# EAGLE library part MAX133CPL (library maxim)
3 3/4-digit DMM CIRCUIT

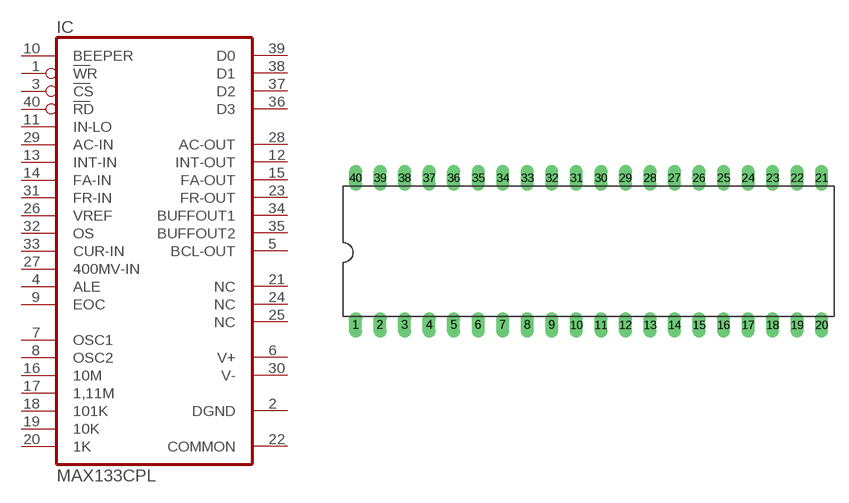
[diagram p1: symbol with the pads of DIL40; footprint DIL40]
Designator prefix IC

## MAX133CPL (MPN: MAX133CPL+; OC_FARNELL: unknown; OC_NEWARK: 99K2893)  [DIL40]
1  WR  in
2  DGND  pwr
3  CS  in
4  ALE  in
5  BCL-OUT  out
6  V+  pwr
7  OSC1  pas
8  OSC2  pas
9  EOC  in
10  BEEPER  in
11  IN-LO  in
12  INT-OUT  out
13  INT-IN  in
14  FA-IN  in
15  FA-OUT  out
16  10M  pas
17  1,11M  pas
18  101K  pas
19  10K  pas
20  1K  pas
21  NC  nc
22  COMMON  pwr
23  FR-OUT  out
24  NC  nc
25  NC  nc
26  VREF  in
27  400MV-IN  in
28  AC-OUT  out
29  AC-IN  in
30  V-  pwr
31  FR-IN  in
32  OS  in
33  CUR-IN  in
34  BUFFOUT1  out
35  BUFFOUT2  out
36  D3  out
37  D2  out
38  D1  out
39  D0  out
40  RD  in

## Footprint DIL40 (pad centres in mm)
Dual In Line Package
drill 0.813 long: 1 -24.13,-7.62; 2 -21.59,-7.62; 3 -19.05,-7.62; 4 -16.51,-7.62; 5 -13.97,-7.62; 6 -11.43,-7.62; 7 -8.89,-7.62; 8 -6.35,-7.62; 9 -3.81,-7.62; 10 -1.27,-7.62; 11 1.27,-7.62; 12 3.81,-7.62; 13 6.35,-7.62; 14 8.89,-7.62; 15 11.43,-7.62; 16 13.97,-7.62; 17 16.51,-7.62; 18 19.05,-7.62; 19 21.59,-7.62; 20 24.13,-7.62; 21 24.13,7.62; 22 21.59,7.62; 23 19.05,7.62; 24 16.51,7.62; 25 13.97,7.62; 26 11.43,7.62; 27 8.89,7.62; 28 6.35,7.62; 29 3.81,7.62; 30 1.27,7.62; 31 -1.27,7.62; 32 -3.81,7.62; 33 -6.35,7.62; 34 -8.89,7.62; 35 -11.43,7.62; 36 -13.97,7.62; 37 -16.51,7.62; 38 -19.05,7.62; 39 -21.59,7.62; 40 -24.13,7.62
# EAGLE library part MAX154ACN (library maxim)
ANALOG/DIGITAL CONVERTER

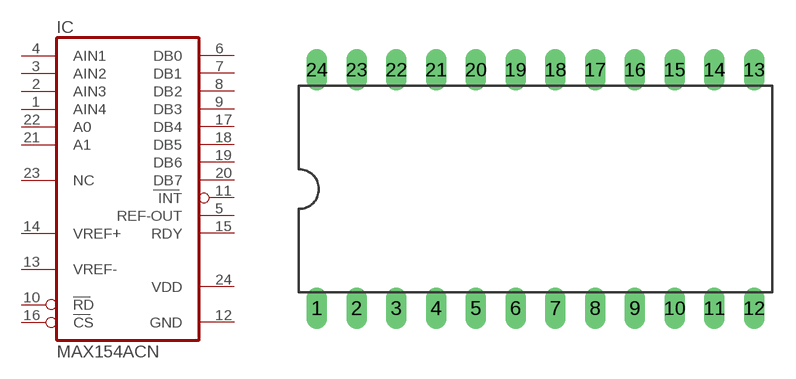
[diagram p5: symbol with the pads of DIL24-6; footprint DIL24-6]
Designator prefix IC

## MAX154ACN (MPN: MAX154ACNG+; OC_FARNELL: unknown; OC_NEWARK: 67K4138)  [DIL24-6]
1  AIN4  in
2  AIN3  in
3  AIN2  in
4  AIN1  in
5  REF-OUT  out
6  DB0  hiz
7  DB1  hiz
8  DB2  hiz
9  DB3  hiz
10  RD  in
11  INT  out
12  GND  pwr
13  VREF-  pas
14  VREF+  pas
15  RDY  out
16  CS  in
17  DB4  hiz
18  DB5  hiz
19  DB6  hiz
20  DB7  hiz
21  A1  in
22  A0  in
23  NC  nc
24  VDD  pwr

## Footprint DIL24-6 (pad centres in mm)
Dual In Line Package 0.6 inch
drill 0.813 long: 1 -13.97,-7.62; 2 -11.43,-7.62; 3 -8.89,-7.62; 4 -6.35,-7.62; 5 -3.81,-7.62; 6 -1.27,-7.62; 7 1.27,-7.62; 8 3.81,-7.62; 9 6.35,-7.62; 10 8.89,-7.62; 11 11.43,-7.62; 12 13.97,-7.62; 13 13.97,7.62; 14 11.43,7.62; 15 8.89,7.62; 16 6.35,7.62; 17 3.81,7.62; 18 1.27,7.62; 19 -1.27,7.62; 20 -3.81,7.62; 21 -6.35,7.62; 22 -8.89,7.62; 23 -11.43,7.62; 24 -13.97,7.62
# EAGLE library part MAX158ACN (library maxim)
ANALOG/DIGITAL CONVERTER

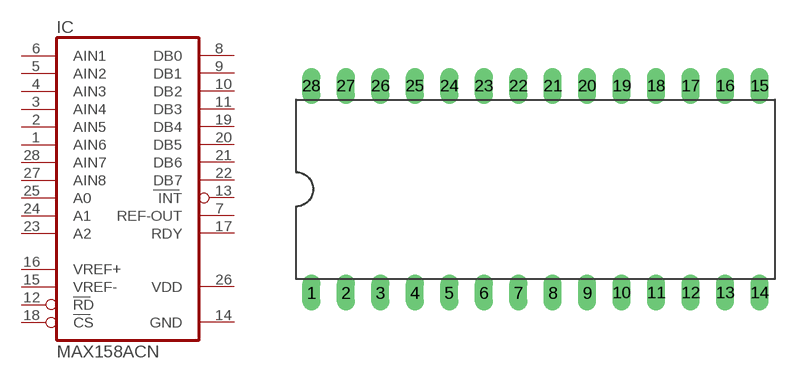
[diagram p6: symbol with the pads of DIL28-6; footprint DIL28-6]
Designator prefix IC

## MAX158ACN (OC_FARNELL: unknown; OC_NEWARK: unknown)  [DIL28-6]
1  AIN6  in
2  AIN5  in
3  AIN4  in
4  AIN3  in
5  AIN2  in
6  AIN1  in
7  REF-OUT  out
8  DB0  hiz
9  DB1  hiz
10  DB2  hiz
11  DB3  hiz
12  RD  in
13  INT  out
14  GND  pwr
15  VREF-  pas
16  VREF+  pas
17  RDY  out
18  CS  in
19  DB4  hiz
20  DB5  hiz
21  DB6  hiz
22  DB7  hiz
23  A2  in
24  A1  in
25  A0  in
26  VDD  pwr
27  AIN8  in
28  AIN7  in

## Footprint DIL28-6 (pad centres in mm)
Dual In Line Package 0.6 inch
drill 0.813 long: 1 -16.51,-7.62; 2 -13.97,-7.62; 3 -11.43,-7.62; 4 -8.89,-7.62; 5 -6.35,-7.62; 6 -3.81,-7.62; 7 -1.27,-7.62; 8 1.27,-7.62; 9 3.81,-7.62; 10 6.35,-7.62; 11 8.89,-7.62; 12 11.43,-7.62; 13 13.97,-7.62; 14 16.51,-7.62; 15 16.51,7.62; 16 13.97,7.62; 17 11.43,7.62; 18 8.89,7.62; 19 6.35,7.62; 20 3.81,7.62; 21 1.27,7.62; 22 -1.27,7.62; 23 -3.81,7.62; 24 -6.35,7.62; 25 -8.89,7.62; 26 -11.43,7.62; 27 -13.97,7.62; 28 -16.51,7.62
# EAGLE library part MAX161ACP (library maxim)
ANALOG/DIGITAL CONVERTER

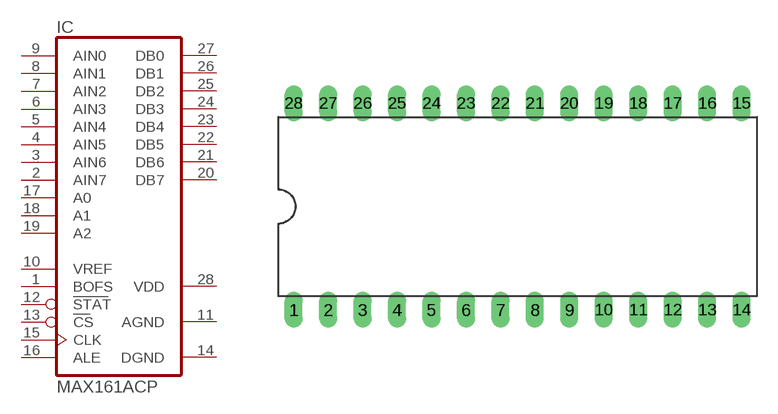
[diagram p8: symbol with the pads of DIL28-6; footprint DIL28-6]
Designator prefix IC

## MAX161ACP (MPN: MAX161ACPI+; OC_FARNELL: unknown; OC_NEWARK: 99K3007)  [DIL28-6]
1  BOFS  in
2  AIN7  in
3  AIN6  in
4  AIN5  in
5  AIN4  in
6  AIN3  in
7  AIN2  in
8  AIN1  in
9  AIN0  in
10  VREF  pas
11  AGND  pwr
12  STAT  in
13  CS  in
14  DGND  pwr
15  CLK  in
16  ALE  in
17  A0  in
18  A1  in
19  A2  in
20  DB7  hiz
21  DB6  hiz
22  DB5  hiz
23  DB4  hiz
24  DB3  hiz
25  DB2  hiz
26  DB1  hiz
27  DB0  hiz
28  VDD  pwr

## Footprint DIL28-6 (pad centres in mm)
Dual In Line Package 0.6 inch
drill 0.813 long: 1 -16.51,-7.62; 2 -13.97,-7.62; 3 -11.43,-7.62; 4 -8.89,-7.62; 5 -6.35,-7.62; 6 -3.81,-7.62; 7 -1.27,-7.62; 8 1.27,-7.62; 9 3.81,-7.62; 10 6.35,-7.62; 11 8.89,-7.62; 12 11.43,-7.62; 13 13.97,-7.62; 14 16.51,-7.62; 15 16.51,7.62; 16 13.97,7.62; 17 11.43,7.62; 18 8.89,7.62; 19 6.35,7.62; 20 3.81,7.62; 21 1.27,7.62; 22 -1.27,7.62; 23 -3.81,7.62; 24 -6.35,7.62; 25 -8.89,7.62; 26 -11.43,7.62; 27 -13.97,7.62; 28 -16.51,7.62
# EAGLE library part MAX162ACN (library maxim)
ANALOG/DIGITAL CONVERTER

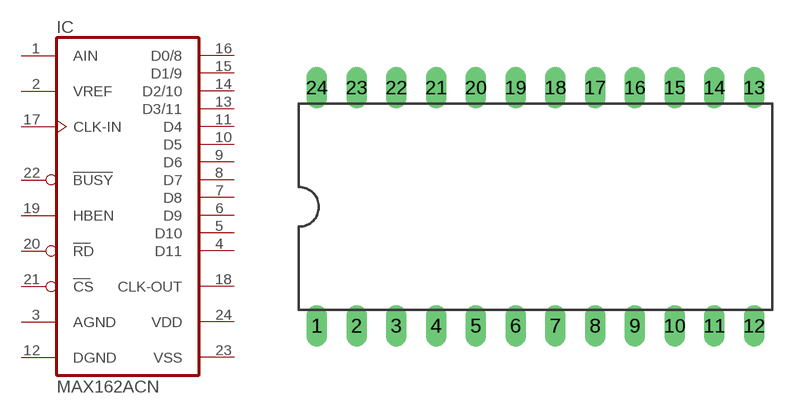
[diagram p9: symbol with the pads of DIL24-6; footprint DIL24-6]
Designator prefix IC

## MAX162ACN (MPN: MAX162ACNG+; OC_FARNELL: unknown; OC_NEWARK: 89K3211)  [DIL24-6]
1  AIN  in
2  VREF  in
3  AGND  pas
4  D11  hiz
5  D10  hiz
6  D9  hiz
7  D8  hiz
8  D7  hiz
9  D6  hiz
10  D5  hiz
11  D4  hiz
12  DGND  pas
13  D3/11  hiz
14  D2/10  hiz
15  D1/9  hiz
16  D0/8  hiz
17  CLK-IN  in
18  CLK-OUT  out
19  HBEN  in
20  RD  in
21  CS  in
22  BUSY  in
23  VSS  pwr
24  VDD  pwr

## Footprint DIL24-6 (pad centres in mm)
Dual In Line Package 0.6 inch
drill 0.813 long: 1 -13.97,-7.62; 2 -11.43,-7.62; 3 -8.89,-7.62; 4 -6.35,-7.62; 5 -3.81,-7.62; 6 -1.27,-7.62; 7 1.27,-7.62; 8 3.81,-7.62; 9 6.35,-7.62; 10 8.89,-7.62; 11 11.43,-7.62; 12 13.97,-7.62; 13 13.97,7.62; 14 11.43,7.62; 15 8.89,7.62; 16 6.35,7.62; 17 3.81,7.62; 18 1.27,7.62; 19 -1.27,7.62; 20 -3.81,7.62; 21 -6.35,7.62; 22 -8.89,7.62; 23 -11.43,7.62; 24 -13.97,7.62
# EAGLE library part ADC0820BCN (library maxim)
ANALOG/DIGITAL CONVERTER

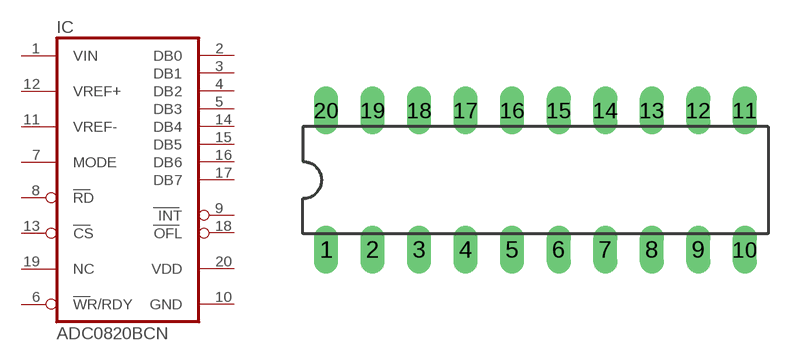
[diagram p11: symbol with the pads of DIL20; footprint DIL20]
Designator prefix IC

## ADC0820BCN (MF: NATIONAL SEMICONDUCTOR; MPN: ADC0820CCN/NOPB.; OC_FARNELL: 1189415; OC_NEWARK: unknown)  [DIL20]
1  VIN  in
2  DB0  hiz
3  DB1  hiz
4  DB2  hiz
5  DB3  hiz
6  WR/RDY
7  MODE  in
8  RD  in
9  INT  out
10  GND  pwr
11  VREF-  pas
12  VREF+  pas
13  CS  in
14  DB4  hiz
15  DB5  hiz
16  DB6  hiz
17  DB7  hiz
18  OFL  out
19  NC  nc
20  VDD  pwr

## Footprint DIL20 (pad centres in mm)
Dual In Line Package
drill 0.813 long: 1 -11.43,-3.81; 2 -8.89,-3.81; 3 -6.35,-3.81; 4 -3.81,-3.81; 5 -1.27,-3.81; 6 1.27,-3.81; 7 3.81,-3.81; 8 6.35,-3.81; 9 8.89,-3.81; 10 11.43,-3.81; 11 11.43,3.81; 12 8.89,3.81; 13 6.35,3.81; 14 3.81,3.81; 15 1.27,3.81; 16 -1.27,3.81; 17 -3.81,3.81; 18 -6.35,3.81; 19 -8.89,3.81; 20 -11.43,3.81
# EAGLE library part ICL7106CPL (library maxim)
LCD DRIVER

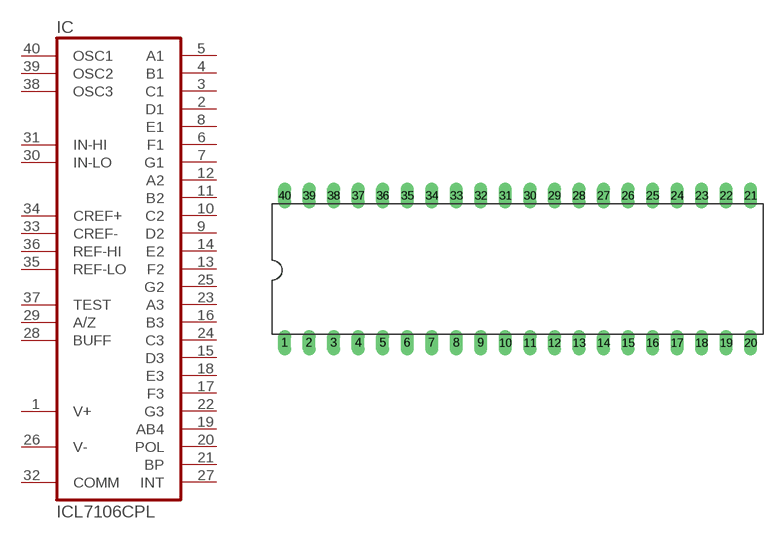
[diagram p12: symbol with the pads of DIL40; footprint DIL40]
Designator prefix IC

## ICL7106CPL (MF: INTERSIL; MPN: ICL7106CPL; OC_FARNELL: 9663550; OC_NEWARK: 06F7355)  [DIL40]
1  V+  pwr
2  D1  hiz
3  C1  hiz
4  B1  hiz
5  A1  hiz
6  F1  hiz
7  G1  hiz
8  E1  hiz
9  D2  hiz
10  C2  hiz
11  B2  hiz
12  A2  hiz
13  F2  hiz
14  E2  hiz
15  D3  hiz
16  B3  hiz
17  F3  hiz
18  E3  hiz
19  AB4  hiz
20  POL  out
21  BP  out
22  G3  hiz
23  A3  hiz
24  C3  hiz
25  G2  hiz
26  V-  pwr
27  INT  out
28  BUFF  pas
29  A/Z  pas
30  IN-LO  in
31  IN-HI  in
32  COMM  pwr
33  CREF-  pas
34  CREF+  pas
35  REF-LO  in
36  REF-HI  in
37  TEST  pas
38  OSC3  pas
39  OSC2  pas
40  OSC1  pas

## Footprint DIL40 (pad centres in mm)
Dual In Line Package
drill 0.813 long: 1 -24.13,-7.62; 2 -21.59,-7.62; 3 -19.05,-7.62; 4 -16.51,-7.62; 5 -13.97,-7.62; 6 -11.43,-7.62; 7 -8.89,-7.62; 8 -6.35,-7.62; 9 -3.81,-7.62; 10 -1.27,-7.62; 11 1.27,-7.62; 12 3.81,-7.62; 13 6.35,-7.62; 14 8.89,-7.62; 15 11.43,-7.62; 16 13.97,-7.62; 17 16.51,-7.62; 18 19.05,-7.62; 19 21.59,-7.62; 20 24.13,-7.62; 21 24.13,7.62; 22 21.59,7.62; 23 19.05,7.62; 24 16.51,7.62; 25 13.97,7.62; 26 11.43,7.62; 27 8.89,7.62; 28 6.35,7.62; 29 3.81,7.62; 30 1.27,7.62; 31 -1.27,7.62; 32 -3.81,7.62; 33 -6.35,7.62; 34 -8.89,7.62; 35 -11.43,7.62; 36 -13.97,7.62; 37 -16.51,7.62; 38 -19.05,7.62; 39 -21.59,7.62; 40 -24.13,7.62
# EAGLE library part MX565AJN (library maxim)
DIGITAL/ANALOG CONVERTER

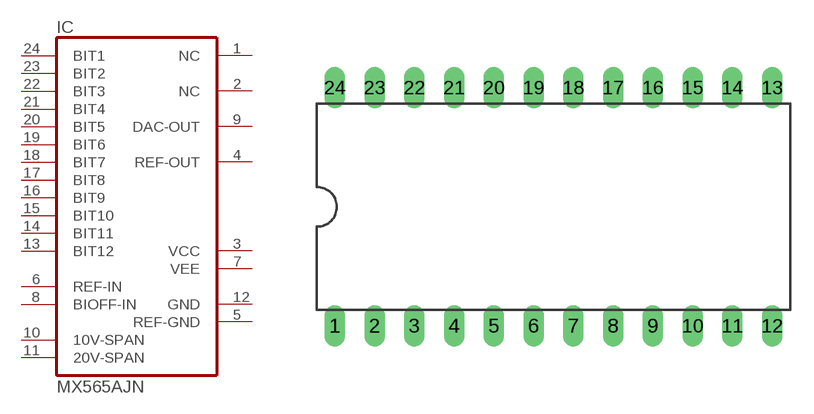
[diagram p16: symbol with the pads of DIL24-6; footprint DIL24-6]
Designator prefix IC

## MX565AJN (OC_FARNELL: unknown; OC_NEWARK: unknown)  [DIL24-6]
1  NC  nc
2  NC  nc
3  VCC  pwr
4  REF-OUT  out
5  REF-GND  pwr
6  REF-IN  in
7  VEE  pwr
8  BIOFF-IN  in
9  DAC-OUT  out
10  10V-SPAN  pas
11  20V-SPAN  pas
12  GND  pwr
13  BIT12  in
14  BIT11  in
15  BIT10  in
16  BIT9  in
17  BIT8  in
18  BIT7  in
19  BIT6  in
20  BIT5  in
21  BIT4  in
22  BIT3  in
23  BIT2  in
24  BIT1  in

## Footprint DIL24-6 (pad centres in mm)
Dual In Line Package 0.6 inch
drill 0.813 long: 1 -13.97,-7.62; 2 -11.43,-7.62; 3 -8.89,-7.62; 4 -6.35,-7.62; 5 -3.81,-7.62; 6 -1.27,-7.62; 7 1.27,-7.62; 8 3.81,-7.62; 9 6.35,-7.62; 10 8.89,-7.62; 11 11.43,-7.62; 12 13.97,-7.62; 13 13.97,7.62; 14 11.43,7.62; 15 8.89,7.62; 16 6.35,7.62; 17 3.81,7.62; 18 1.27,7.62; 19 -1.27,7.62; 20 -3.81,7.62; 21 -6.35,7.62; 22 -8.89,7.62; 23 -11.43,7.62; 24 -13.97,7.62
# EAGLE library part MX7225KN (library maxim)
DIGITAL/ANALOG CONVERTER

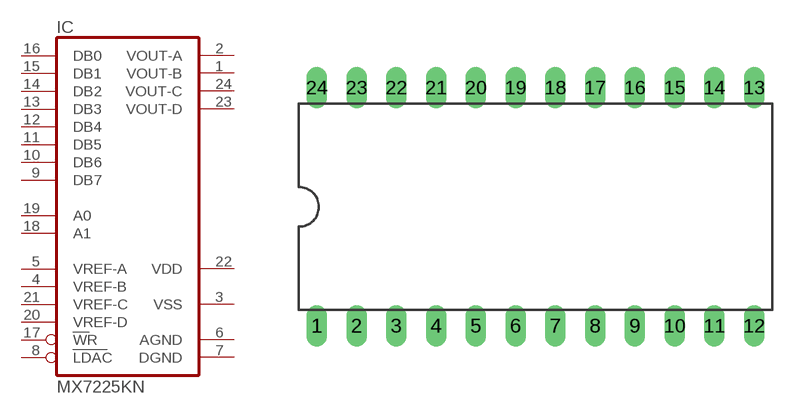
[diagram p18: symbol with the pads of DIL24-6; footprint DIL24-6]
Designator prefix IC

## MX7225KN (MPN: MX7225KN+; OC_FARNELL: unknown; OC_NEWARK: 67K7165)  [DIL24-6]
1  VOUT-B  out
2  VOUT-A  out
3  VSS  pwr
4  VREF-B  in
5  VREF-A  in
6  AGND  pwr
7  DGND  pwr
8  LDAC  in
9  DB7  in
10  DB6  in
11  DB5  in
12  DB4  in
13  DB3  in
14  DB2  in
15  DB1  in
16  DB0  in
17  WR  in
18  A1  in
19  A0  in
20  VREF-D  in
21  VREF-C  in
22  VDD  pwr
23  VOUT-D  out
24  VOUT-C  out

## Footprint DIL24-6 (pad centres in mm)
Dual In Line Package 0.6 inch
drill 0.813 long: 1 -13.97,-7.62; 2 -11.43,-7.62; 3 -8.89,-7.62; 4 -6.35,-7.62; 5 -3.81,-7.62; 6 -1.27,-7.62; 7 1.27,-7.62; 8 3.81,-7.62; 9 6.35,-7.62; 10 8.89,-7.62; 11 11.43,-7.62; 12 13.97,-7.62; 13 13.97,7.62; 14 11.43,7.62; 15 8.89,7.62; 16 6.35,7.62; 17 3.81,7.62; 18 1.27,7.62; 19 -1.27,7.62; 20 -3.81,7.62; 21 -6.35,7.62; 22 -8.89,7.62; 23 -11.43,7.62; 24 -13.97,7.62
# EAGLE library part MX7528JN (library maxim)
DIGITAL/ANALOG CONVERTER

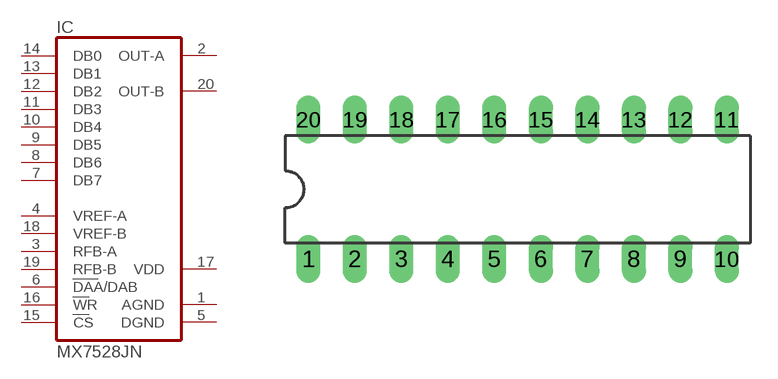
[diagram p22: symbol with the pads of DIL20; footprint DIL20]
Designator prefix IC

## MX7528JN (MPN: MX7528JN; OC_FARNELL: 1187979; OC_NEWARK: 34C4061)  [DIL20]
1  AGND  pwr
2  OUT-A  out
3  RFB-A  in
4  VREF-A  in
5  DGND  pwr
6  DAA/DAB  in
7  DB7  in
8  DB6  in
9  DB5  in
10  DB4  in
11  DB3  in
12  DB2  in
13  DB1  in
14  DB0  in
15  CS  in
16  WR  in
17  VDD  pwr
18  VREF-B  in
19  RFB-B  in
20  OUT-B  out

## Footprint DIL20 (pad centres in mm)
Dual In Line Package
drill 0.813 long: 1 -11.43,-3.81; 2 -8.89,-3.81; 3 -6.35,-3.81; 4 -3.81,-3.81; 5 -1.27,-3.81; 6 1.27,-3.81; 7 3.81,-3.81; 8 6.35,-3.81; 9 8.89,-3.81; 10 11.43,-3.81; 11 11.43,3.81; 12 8.89,3.81; 13 6.35,3.81; 14 3.81,3.81; 15 1.27,3.81; 16 -1.27,3.81; 17 -3.81,3.81; 18 -6.35,3.81; 19 -8.89,3.81; 20 -11.43,3.81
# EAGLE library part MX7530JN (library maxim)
DIGITAL/ANALOG CONVERTER

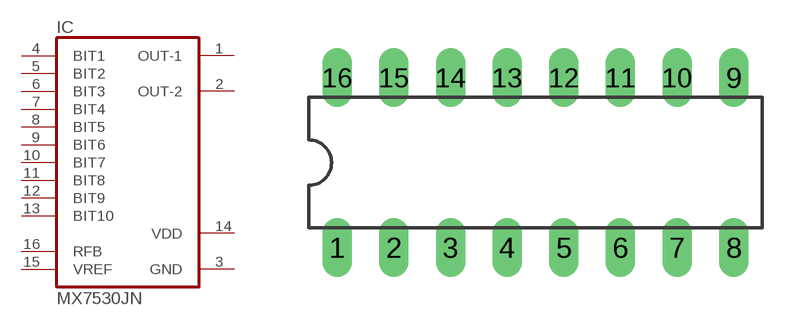
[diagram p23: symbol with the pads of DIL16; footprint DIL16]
Designator prefix IC

## MX7530JN (MPN: MX7530JN+; OC_FARNELL: unknown; OC_NEWARK: 99K3933)  [DIL16]
1  OUT-1  out
2  OUT-2  out
3  GND  pwr
4  BIT1  in
5  BIT2  in
6  BIT3  in
7  BIT4  in
8  BIT5  in
9  BIT6  in
10  BIT7  in
11  BIT8  in
12  BIT9  in
13  BIT10  in
14  VDD  pwr
15  VREF  in
16  RFB  in

## Footprint DIL16 (pad centres in mm)
Dual In Line Package
drill 0.813 long: 1 -8.89,-3.81; 2 -6.35,-3.81; 3 -3.81,-3.81; 4 -1.27,-3.81; 5 1.27,-3.81; 6 3.81,-3.81; 7 6.35,-3.81; 8 8.89,-3.81; 9 8.89,3.81; 10 6.35,3.81; 11 3.81,3.81; 12 1.27,3.81; 13 -1.27,3.81; 14 -3.81,3.81; 15 -6.35,3.81; 16 -8.89,3.81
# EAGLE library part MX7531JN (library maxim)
DIGITAL/ANALOG CONVERTER

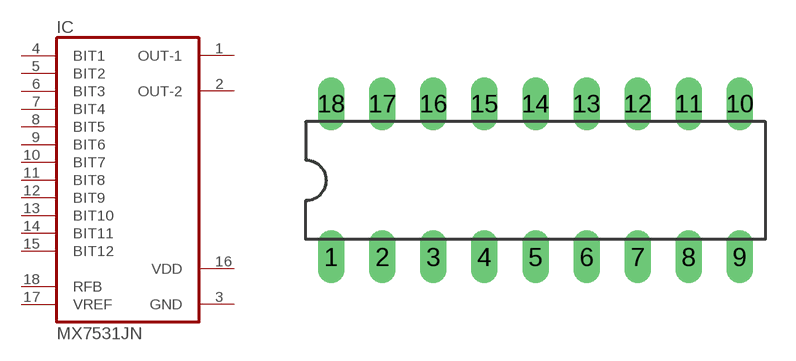
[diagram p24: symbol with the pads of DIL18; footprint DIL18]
Designator prefix IC

## MX7531JN (OC_FARNELL: unknown; OC_NEWARK: unknown)  [DIL18]
1  OUT-1  out
2  OUT-2  out
3  GND  pwr
4  BIT1  in
5  BIT2  in
6  BIT3  in
7  BIT4  in
8  BIT5  in
9  BIT6  in
10  BIT7  in
11  BIT8  in
12  BIT9  in
13  BIT10  in
14  BIT11  in
15  BIT12  in
16  VDD  pwr
17  VREF  in
18  RFB  in

## Footprint DIL18 (pad centres in mm)
Dual In Line Package
drill 0.813 long: 1 -10.16,-3.81; 2 -7.62,-3.81; 3 -5.08,-3.81; 4 -2.54,-3.81; 5 0,-3.81; 6 2.54,-3.81; 7 5.08,-3.81; 8 7.62,-3.81; 9 10.16,-3.81; 10 10.16,3.81; 11 7.62,3.81; 12 5.08,3.81; 13 2.54,3.81; 14 0,3.81; 15 -2.54,3.81; 16 -5.08,3.81; 17 -7.62,3.81; 18 -10.16,3.81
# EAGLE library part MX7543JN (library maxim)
DIGITAL/ANALOG CONVERTER

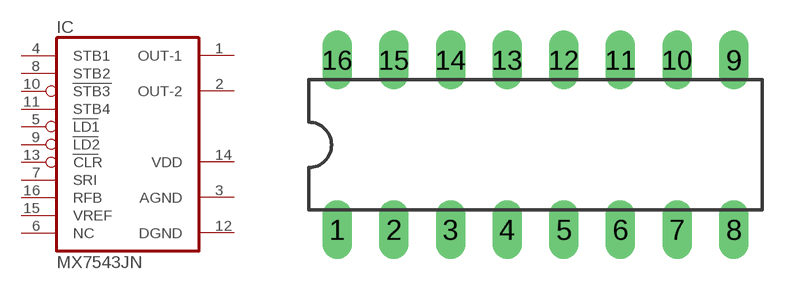
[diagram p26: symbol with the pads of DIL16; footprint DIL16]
Designator prefix IC

## MX7543JN (MF: MAXIM; MPN: MX7543JN; OC_FARNELL: 1187981; OC_NEWARK: 91C3519)  [DIL16]
1  OUT-1  out
2  OUT-2  out
3  AGND  pwr
4  STB1  in
5  LD1  in
6  NC  nc
7  SRI  in
8  STB2  in
9  LD2  in
10  STB3  in
11  STB4  in
12  DGND  pwr
13  CLR  in
14  VDD  pwr
15  VREF  in
16  RFB  in

## Footprint DIL16 (pad centres in mm)
Dual In Line Package
drill 0.813 long: 1 -8.89,-3.81; 2 -6.35,-3.81; 3 -3.81,-3.81; 4 -1.27,-3.81; 5 1.27,-3.81; 6 3.81,-3.81; 7 6.35,-3.81; 8 8.89,-3.81; 9 8.89,3.81; 10 6.35,3.81; 11 3.81,3.81; 12 1.27,3.81; 13 -1.27,3.81; 14 -3.81,3.81; 15 -6.35,3.81; 16 -8.89,3.81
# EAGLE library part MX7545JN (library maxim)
DIGITAL/ANALOG CONVERTER

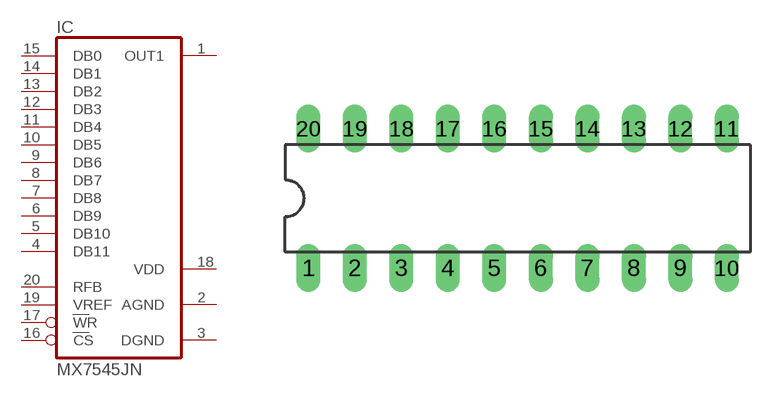
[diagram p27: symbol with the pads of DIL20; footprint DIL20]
Designator prefix IC

## MX7545JN (MPN: MX7545JN+; OC_FARNELL: unknown; OC_NEWARK: 61K1015)  [DIL20]
1  OUT1  out
2  AGND  pwr
3  DGND  pwr
4  DB11  in
5  DB10  in
6  DB9  in
7  DB8  in
8  DB7  in
9  DB6  in
10  DB5  in
11  DB4  in
12  DB3  in
13  DB2  in
14  DB1  in
15  DB0  in
16  CS  in
17  WR  in
18  VDD  pwr
19  VREF  in
20  RFB  in

## Footprint DIL20 (pad centres in mm)
Dual In Line Package
drill 0.813 long: 1 -11.43,-3.81; 2 -8.89,-3.81; 3 -6.35,-3.81; 4 -3.81,-3.81; 5 -1.27,-3.81; 6 1.27,-3.81; 7 3.81,-3.81; 8 6.35,-3.81; 9 8.89,-3.81; 10 11.43,-3.81; 11 11.43,3.81; 12 8.89,3.81; 13 6.35,3.81; 14 3.81,3.81; 15 1.27,3.81; 16 -1.27,3.81; 17 -3.81,3.81; 18 -6.35,3.81; 19 -8.89,3.81; 20 -11.43,3.81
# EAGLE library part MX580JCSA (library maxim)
VOLTAGE REFERENCE

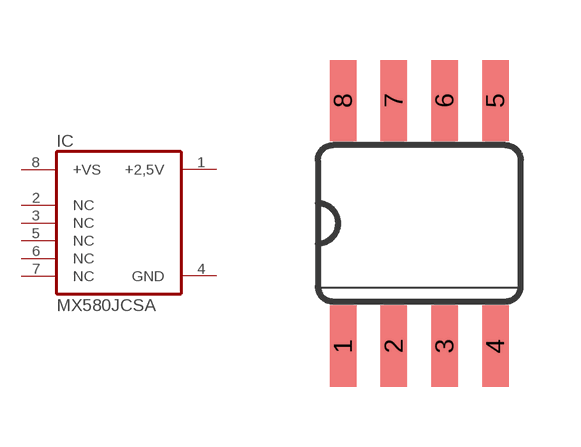
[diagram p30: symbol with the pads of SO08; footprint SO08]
Designator prefix IC

## MX580JCSA (OC_FARNELL: unknown; OC_NEWARK: unknown)  [SO08]
1  +2,5V  out
2  NC  nc
3  NC  nc
4  GND  pwr
5  NC  nc
6  NC  nc
7  NC  nc
8  +VS  in

## Footprint SO08 (pad centres in mm)
Small Outline Package SOIC 150 mil
smd 0.66 x 2.032: 1 -1.905,-3.073; 2 -0.635,-3.073; 3 0.635,-3.073; 4 1.905,-3.073; 5 1.905,3.073; 6 0.635,3.073; 7 -0.635,3.073; 8 -1.905,3.073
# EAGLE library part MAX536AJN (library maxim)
DIGITAL/ANALOG CONVERTER

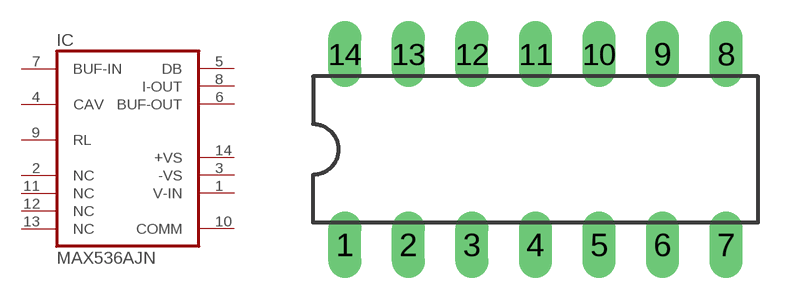
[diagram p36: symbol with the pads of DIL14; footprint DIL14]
Designator prefix IC

## MAX536AJN (OC_FARNELL: unknown; OC_NEWARK: unknown)  [DIL14]
1  V-IN  pwr
2  NC  nc
3  -VS  pwr
4  CAV  pas
5  DB  out
6  BUF-OUT  out
7  BUF-IN  in
8  I-OUT  out
9  RL  pas
10  COMM  pwr
11  NC  nc
12  NC  nc
13  NC  nc
14  +VS  pwr

## Footprint DIL14 (pad centres in mm)
Dual In Line Package
drill 0.813 long: 1 -7.62,-3.81; 2 -5.08,-3.81; 3 -2.54,-3.81; 4 0,-3.81; 5 2.54,-3.81; 6 5.08,-3.81; 7 7.62,-3.81; 8 7.62,3.81; 9 5.08,3.81; 10 2.54,3.81; 11 0,3.81; 12 -2.54,3.81; 13 -5.08,3.81; 14 -7.62,3.81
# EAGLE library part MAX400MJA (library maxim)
OP AMP

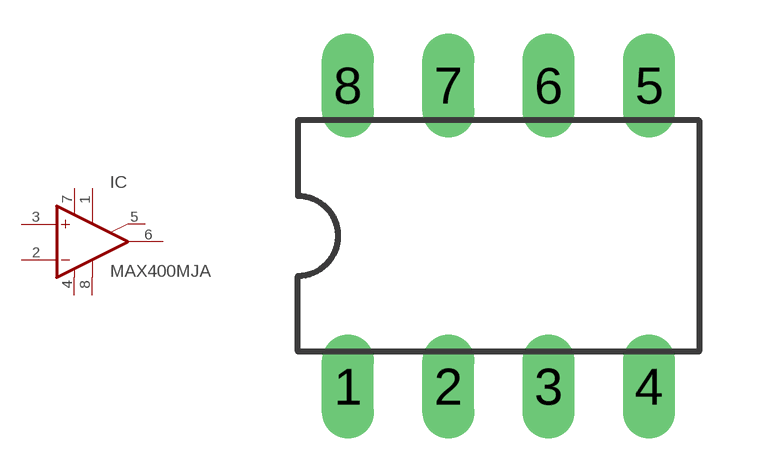
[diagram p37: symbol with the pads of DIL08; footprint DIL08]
Designator prefix IC

## MAX400MJA (OC_FARNELL: unknown; OC_NEWARK: unknown)  [DIL08]
1  VOS  pas
2  -IN  in
3  +IN  in
4  V-  pwr
5  NC  nc
6  OUT  out
7  V+  pwr
8  VOS  pas

## Footprint DIL08 (pad centres in mm)
Dual In Line Package
drill 0.813 long: 1 -3.81,-3.81; 2 -1.27,-3.81; 3 1.27,-3.81; 4 3.81,-3.81; 5 3.81,3.81; 6 1.27,3.81; 7 -1.27,3.81; 8 -3.81,3.81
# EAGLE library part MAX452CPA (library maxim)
VIDEO AMPLIFIER

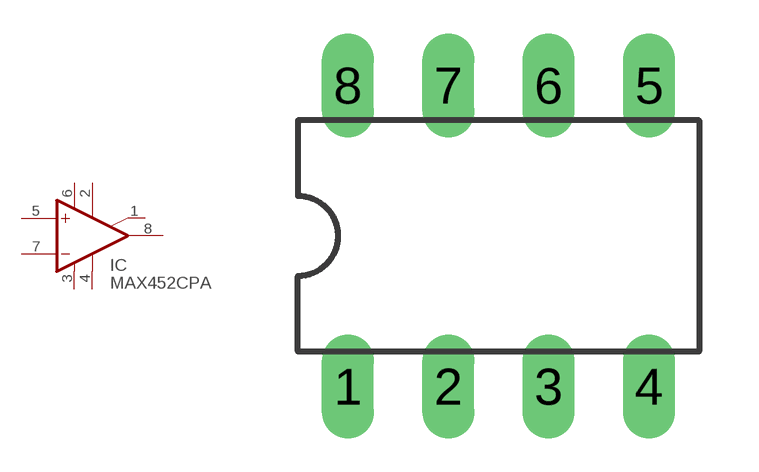
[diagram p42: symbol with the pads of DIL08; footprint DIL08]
Designator prefix IC

## MAX452CPA (MPN: MAX452CPA+; OC_FARNELL: 788910; OC_NEWARK: 99K3387)  [DIL08]
1  NC  nc
2  NC  nc
3  V-  pwr
4  NC  nc
5  +IN  in
6  V+  pwr
7  -IN  in
8  OUT  out

## Footprint DIL08 (pad centres in mm)
Dual In Line Package
drill 0.813 long: 1 -3.81,-3.81; 2 -1.27,-3.81; 3 1.27,-3.81; 4 3.81,-3.81; 5 3.81,3.81; 6 1.27,3.81; 7 -1.27,3.81; 8 -3.81,3.81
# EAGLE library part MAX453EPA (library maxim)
MULTIPLEXER

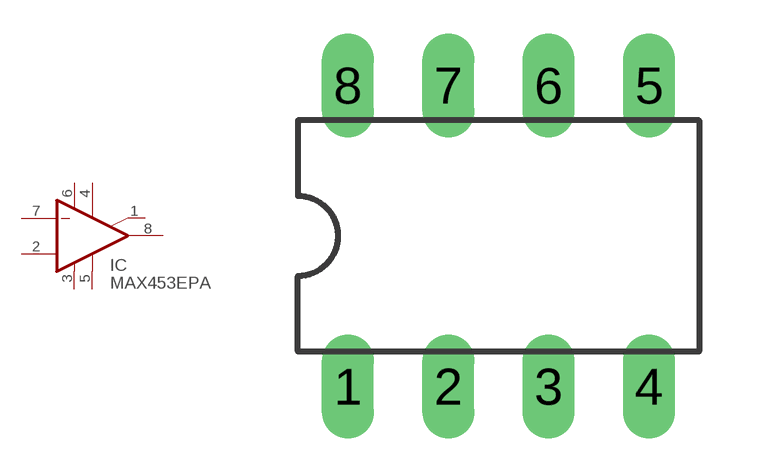
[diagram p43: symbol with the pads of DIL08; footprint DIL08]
Designator prefix IC

## MAX453EPA (OC_FARNELL: unknown; OC_NEWARK: unknown)  [DIL08]
1  A0  in
2  GND  pwr
3  V-  pwr
4  IN0  in
5  IN1  in
6  V+  pwr
7  -IN  in
8  OUT  out

## Footprint DIL08 (pad centres in mm)
Dual In Line Package
drill 0.813 long: 1 -3.81,-3.81; 2 -1.27,-3.81; 3 1.27,-3.81; 4 3.81,-3.81; 5 3.81,3.81; 6 1.27,3.81; 7 -1.27,3.81; 8 -3.81,3.81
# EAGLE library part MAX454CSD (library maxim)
MULTIPLEXER

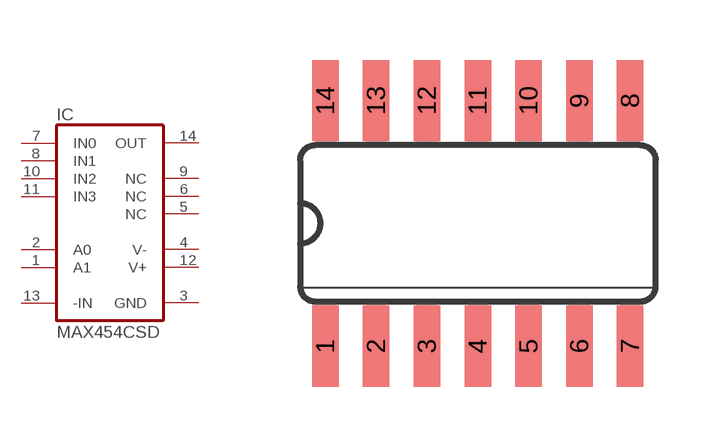
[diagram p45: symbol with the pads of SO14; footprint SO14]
Designator prefix IC

## MAX454CSD (MPN: MAX454CSD+; OC_FARNELL: unknown; OC_NEWARK: 67K5327)  [SO14]
1  A1  in
2  A0  in
3  GND  pwr
4  V-  pwr
5  NC  nc
6  NC  nc
7  IN0  in
8  IN1  in
9  NC  nc
10  IN2  in
11  IN3  in
12  V+  pwr
13  -IN  in
14  OUT  out

## Footprint SO14 (pad centres in mm)
Small Outline Package
smd 0.66 x 2.032: 1 -3.81,-3.073; 2 -2.54,-3.073; 3 -1.27,-3.073; 4 0,-3.073; 5 1.27,-3.073; 6 2.54,-3.073; 7 3.81,-3.073; 8 3.81,3.073; 9 2.54,3.073; 10 1.27,3.073; 11 0,3.073; 12 -1.27,3.073; 13 -2.54,3.073; 14 -3.81,3.073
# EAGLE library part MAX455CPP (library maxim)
MULTIPLEXER

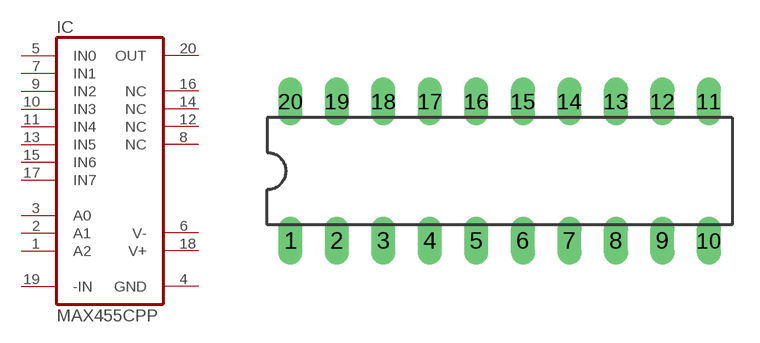
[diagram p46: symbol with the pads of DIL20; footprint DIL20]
Designator prefix IC

## MAX455CPP (MF: MAXIM; MPN: MAX455CPP+; OC_FARNELL: 1422330; OC_NEWARK: 68K4740)  [DIL20]
1  A2  in
2  A1  in
3  A0  in
4  GND  pwr
5  IN0  in
6  V-  pwr
7  IN1  in
8  NC  nc
9  IN2  in
10  IN3  in
11  IN4  in
12  NC  nc
13  IN5  in
14  NC  nc
15  IN6  in
16  NC  nc
17  IN7  in
18  V+  pwr
19  -IN  in
20  OUT  out

## Footprint DIL20 (pad centres in mm)
Dual In Line Package
drill 0.813 long: 1 -11.43,-3.81; 2 -8.89,-3.81; 3 -6.35,-3.81; 4 -3.81,-3.81; 5 -1.27,-3.81; 6 1.27,-3.81; 7 3.81,-3.81; 8 6.35,-3.81; 9 8.89,-3.81; 10 11.43,-3.81; 11 11.43,3.81; 12 8.89,3.81; 13 6.35,3.81; 14 3.81,3.81; 15 1.27,3.81; 16 -1.27,3.81; 17 -3.81,3.81; 18 -6.35,3.81; 19 -8.89,3.81; 20 -11.43,3.81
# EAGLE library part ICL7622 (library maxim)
Dual Operational Amplifiers Source: http://datasheets.maxim-ic.com/en/ds/ICL7612-ICL764X.pdf

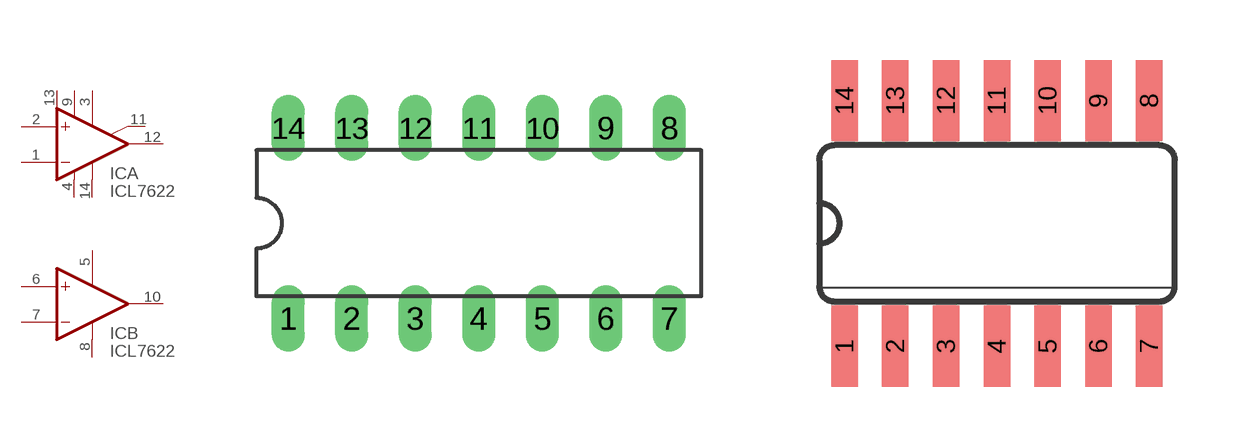
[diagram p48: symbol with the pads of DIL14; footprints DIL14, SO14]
Designator prefix IC; gates A=OPOFF+NC P=2V+V- B=OPOFF

## ICL7622PD (OC_FARNELL: unknown; OC_NEWARK: unknown)  [DIL14]
1  A:-IN  in
2  A:+IN  in
3  A:OFF1  pas
4  P:V-  pwr
5  B:OFF1  pas
6  B:+IN  in
7  B:-IN  in
8  B:OFF2  pas
9  P:V+  pwr
10  B:OUT  out
11  A:NC  pas
12  A:OUT  out
13  P:V+  pwr
14  A:OFF2  pas

## ICL7622SA (OC_FARNELL: unknown; OC_NEWARK: unknown)  [SO14]
Pads as for DIL14

## Footprint DIL14 (pad centres in mm)
Dual In Line Package
drill 0.813 long: 1 -7.62,-3.81; 2 -5.08,-3.81; 3 -2.54,-3.81; 4 0,-3.81; 5 2.54,-3.81; 6 5.08,-3.81; 7 7.62,-3.81; 8 7.62,3.81; 9 5.08,3.81; 10 2.54,3.81; 11 0,3.81; 12 -2.54,3.81; 13 -5.08,3.81; 14 -7.62,3.81

## Footprint SO14 (pad centres in mm)
Small Outline Package
smd 0.66 x 2.032: 1 -3.81,-3.073; 2 -2.54,-3.073; 3 -1.27,-3.073; 4 0,-3.073; 5 1.27,-3.073; 6 2.54,-3.073; 7 3.81,-3.073; 8 3.81,3.073; 9 2.54,3.073; 10 1.27,3.073; 11 0,3.073; 12 -1.27,3.073; 13 -2.54,3.073; 14 -3.81,3.073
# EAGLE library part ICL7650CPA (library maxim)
OP AMP

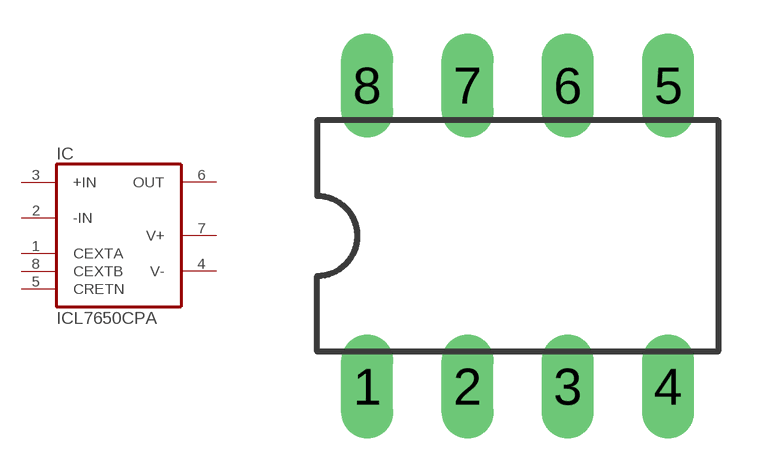
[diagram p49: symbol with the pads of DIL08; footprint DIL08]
Designator prefix IC

## ICL7650CPA (MPN: ICL7650CPA-1; OC_FARNELL: unknown; OC_NEWARK: 06F7424)  [DIL08]
1  CEXTA  pas
2  -IN  in
3  +IN  in
4  V-  pwr
5  CRETN  pas
6  OUT  out
7  V+  pwr
8  CEXTB  pas

## Footprint DIL08 (pad centres in mm)
Dual In Line Package
drill 0.813 long: 1 -3.81,-3.81; 2 -1.27,-3.81; 3 1.27,-3.81; 4 3.81,-3.81; 5 3.81,3.81; 6 1.27,3.81; 7 -1.27,3.81; 8 -3.81,3.81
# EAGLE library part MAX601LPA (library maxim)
AC-DC REGULATOR

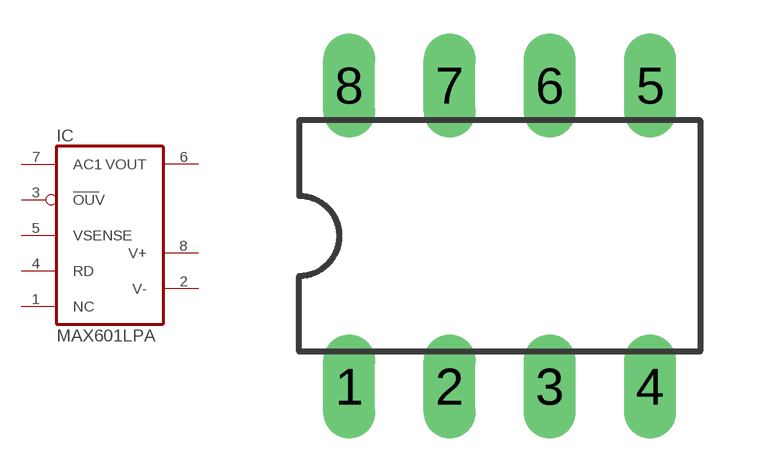
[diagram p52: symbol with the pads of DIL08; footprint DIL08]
Designator prefix IC

## MAX601LPA (OC_FARNELL: unknown; OC_NEWARK: unknown)  [DIL08]
1  NC  nc
2  V-  pwr
3  OUV  in
4  RD  pas
5  VSENSE  in
6  VOUT  out
7  AC1  in
8  V+  pwr

## Footprint DIL08 (pad centres in mm)
Dual In Line Package
drill 0.813 long: 1 -3.81,-3.81; 2 -1.27,-3.81; 3 1.27,-3.81; 4 3.81,-3.81; 5 3.81,3.81; 6 1.27,3.81; 7 -1.27,3.81; 8 -3.81,3.81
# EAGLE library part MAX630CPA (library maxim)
Step-up SWITCHING REGULATOR

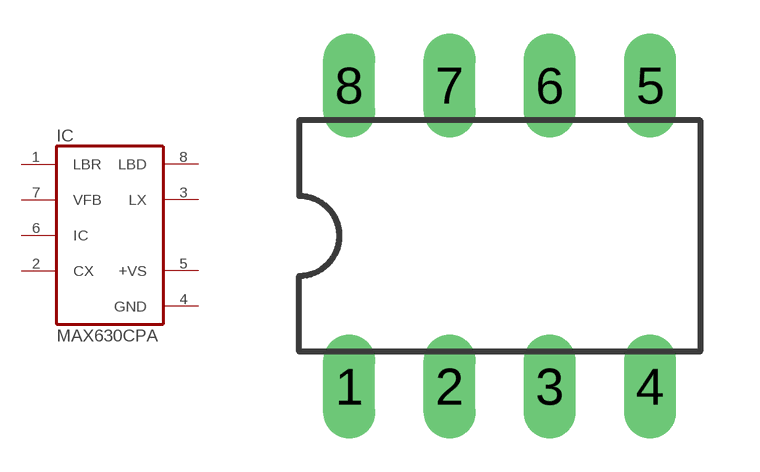
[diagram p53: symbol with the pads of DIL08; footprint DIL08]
Designator prefix IC

## MAX630CPA (MF: MAXIM; MPN: MAX630CPA; OC_FARNELL: unknown; OC_NEWARK: 34C3947)  [DIL08]
1  LBR  in
2  CX  pas
3  LX  out
4  GND  pwr
5  +VS  pwr
6  IC  in
7  VFB  in
8  LBD  out

## Footprint DIL08 (pad centres in mm)
Dual In Line Package
drill 0.813 long: 1 -3.81,-3.81; 2 -1.27,-3.81; 3 1.27,-3.81; 4 3.81,-3.81; 5 3.81,3.81; 6 1.27,3.81; 7 -1.27,3.81; 8 -3.81,3.81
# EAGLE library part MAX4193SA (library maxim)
Step-up SWITCHING REGULATOR

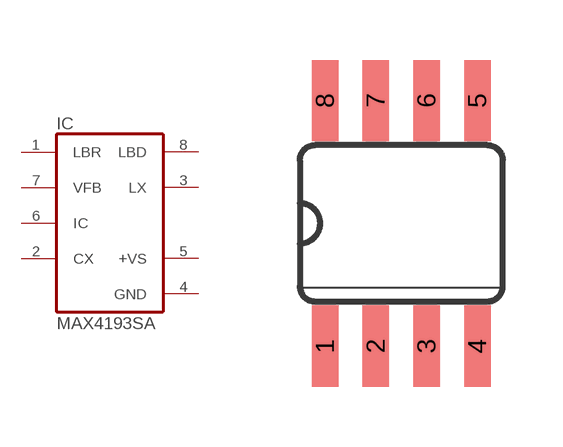
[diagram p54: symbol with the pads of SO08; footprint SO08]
Designator prefix IC

## MAX4193SA (OC_FARNELL: unknown; OC_NEWARK: unknown)  [SO08]
1  LBR  in
2  CX  pas
3  LX  out
4  GND  pwr
5  +VS  pwr
6  IC  in
7  VFB  in
8  LBD  out

## Footprint SO08 (pad centres in mm)
Small Outline Package SOIC 150 mil
smd 0.66 x 2.032: 1 -1.905,-3.073; 2 -0.635,-3.073; 3 0.635,-3.073; 4 1.905,-3.073; 5 1.905,3.073; 6 0.635,3.073; 7 -0.635,3.073; 8 -1.905,3.073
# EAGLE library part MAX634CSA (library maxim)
SWITCHING REGULATOR

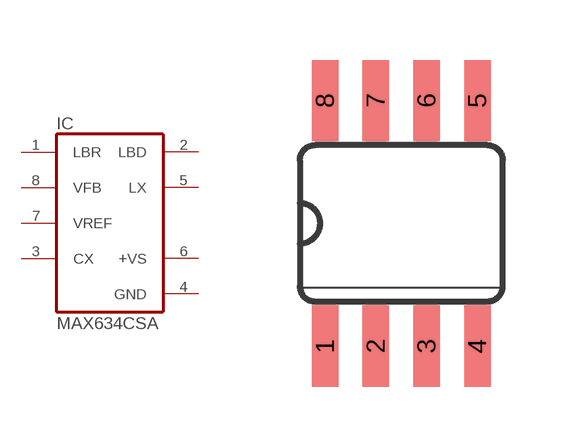
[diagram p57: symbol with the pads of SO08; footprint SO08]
Designator prefix IC

## MAX634CSA (MPN: MAX634CSA+; OC_FARNELL: 1673203; OC_NEWARK: 68K4925)  [SO08]
1  LBR  in
2  LBD  out
3  CX  pas
4  GND  pwr
5  LX  out
6  +VS  pwr
7  VREF  in
8  VFB  in

## Footprint SO08 (pad centres in mm)
Small Outline Package SOIC 150 mil
smd 0.66 x 2.032: 1 -1.905,-3.073; 2 -0.635,-3.073; 3 0.635,-3.073; 4 1.905,-3.073; 5 1.905,3.073; 6 0.635,3.073; 7 -0.635,3.073; 8 -1.905,3.073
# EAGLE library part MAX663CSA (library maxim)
Positive VOLTAGE REGULATOR

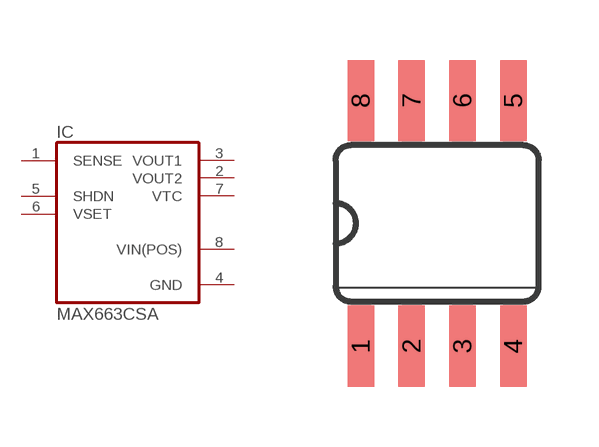
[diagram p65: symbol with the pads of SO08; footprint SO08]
Designator prefix IC

## MAX663CSA (MF: MAXIM; MPN: MAX663CSA; OC_FARNELL: 1188015; OC_NEWARK: 34C3969)  [SO08]
1  SENSE  in
2  VOUT2  out
3  VOUT1  out
4  GND  pwr
5  SHDN  in
6  VSET  in
7  VTC  out
8  VIN(POS)  pwr

## Footprint SO08 (pad centres in mm)
Small Outline Package SOIC 150 mil
smd 0.66 x 2.032: 1 -1.905,-3.073; 2 -0.635,-3.073; 3 0.635,-3.073; 4 1.905,-3.073; 5 1.905,3.073; 6 0.635,3.073; 7 -0.635,3.073; 8 -1.905,3.073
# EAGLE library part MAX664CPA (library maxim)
Negative VOLTAGE REGULATOR

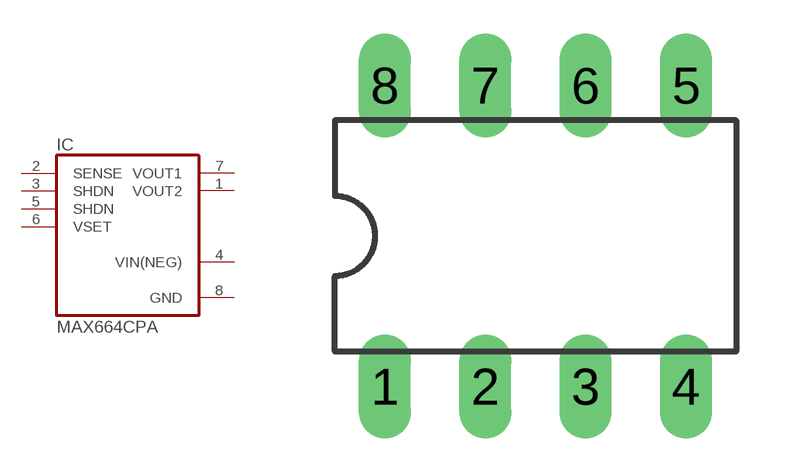
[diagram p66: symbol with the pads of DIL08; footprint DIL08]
Designator prefix IC

## MAX664CPA (MPN: MAX664CPA+; OC_FARNELL: 642617; OC_NEWARK: 76K7012)  [DIL08]
1  VOUT2  out
2  SENSE  in
3  SHDN  in
4  VIN(NEG)  pwr
5  SHDN  in
6  VSET  in
7  VOUT1  out
8  GND  pwr

## Footprint DIL08 (pad centres in mm)
Dual In Line Package
drill 0.813 long: 1 -3.81,-3.81; 2 -1.27,-3.81; 3 1.27,-3.81; 4 3.81,-3.81; 5 3.81,3.81; 6 1.27,3.81; 7 -1.27,3.81; 8 -3.81,3.81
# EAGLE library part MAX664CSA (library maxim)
Negative VOLTAGE REGULATOR

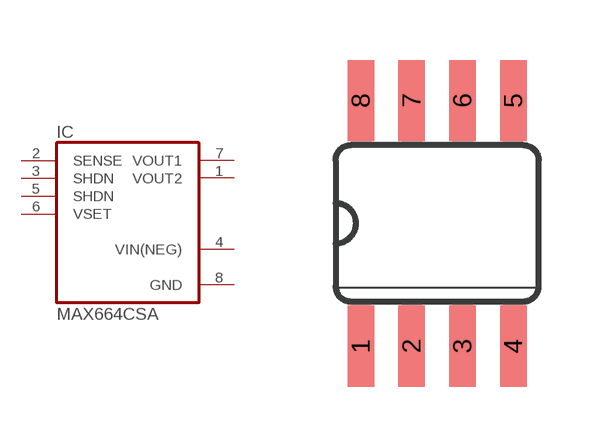
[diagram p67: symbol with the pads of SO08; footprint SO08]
Designator prefix IC

## MAX664CSA (MPN: MAX664CSA; OC_FARNELL: unknown; OC_NEWARK: 78C8112)  [SO08]
1  VOUT2  out
2  SENSE  in
3  SHDN  in
4  VIN(NEG)  pwr
5  SHDN  in
6  VSET  in
7  VOUT1  out
8  GND  pwr

## Footprint SO08 (pad centres in mm)
Small Outline Package SOIC 150 mil
smd 0.66 x 2.032: 1 -1.905,-3.073; 2 -0.635,-3.073; 3 0.635,-3.073; 4 1.905,-3.073; 5 1.905,3.073; 6 0.635,3.073; 7 -0.635,3.073; 8 -1.905,3.073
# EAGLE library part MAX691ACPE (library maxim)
WATCHDOG

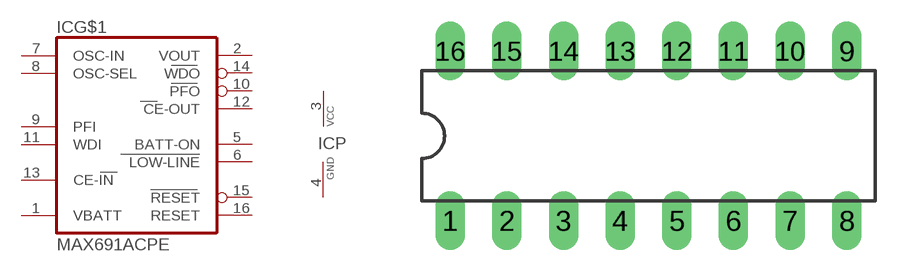
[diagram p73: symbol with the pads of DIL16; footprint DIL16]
Designator prefix IC; gates G$1=MAX691 P=VCC-GND

## MAX691ACPE (MF: MAXIM; MPN: MAX691ACPE+; OC_FARNELL: 1523912; OC_NEWARK: 68K4991)  [DIL16]
1  G$1:VBATT  in
2  G$1:VOUT  out
3  P:VCC  pwr
4  P:GND  pwr
5  G$1:BATT-ON  out
6  G$1:LOW-LINE  out
7  G$1:OSC-IN  pas
8  G$1:OSC-SEL  pas
9  G$1:PFI  in
10  G$1:PFO  out
11  G$1:WDI  in
12  G$1:CE-OUT  out
13  G$1:CE-IN  in
14  G$1:WDO  out
15  G$1:RESET  out
16  G$1:RESET  out

## Footprint DIL16 (pad centres in mm)
Dual In Line Package
drill 0.813 long: 1 -8.89,-3.81; 2 -6.35,-3.81; 3 -3.81,-3.81; 4 -1.27,-3.81; 5 1.27,-3.81; 6 3.81,-3.81; 7 6.35,-3.81; 8 8.89,-3.81; 9 8.89,3.81; 10 6.35,3.81; 11 3.81,3.81; 12 1.27,3.81; 13 -1.27,3.81; 14 -3.81,3.81; 15 -6.35,3.81; 16 -8.89,3.81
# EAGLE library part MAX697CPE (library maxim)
SUPERVISORY CIRCUIT

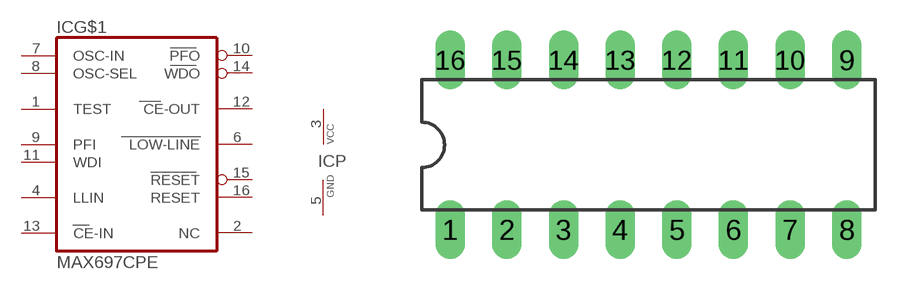
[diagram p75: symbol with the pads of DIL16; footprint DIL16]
Designator prefix IC; gates G$1=MAX697 P=VCC-GND

## MAX697CPE (MPN: MAX697CPE+; OC_FARNELL: unknown; OC_NEWARK: 89K6041)  [DIL16]
1  G$1:TEST  pas
2  G$1:NC  nc
3  P:VCC  pwr
4  G$1:LLIN  in
5  P:GND  pwr
6  G$1:LOW-LINE  out
7  G$1:OSC-IN  pas
8  G$1:OSC-SEL  pas
9  G$1:PFI  in
10  G$1:PFO  out
11  G$1:WDI  in
12  G$1:CE-OUT  out
13  G$1:CE-IN  in
14  G$1:WDO  out
15  G$1:RESET  out
16  G$1:RESET  out

## Footprint DIL16 (pad centres in mm)
Dual In Line Package
drill 0.813 long: 1 -8.89,-3.81; 2 -6.35,-3.81; 3 -3.81,-3.81; 4 -1.27,-3.81; 5 1.27,-3.81; 6 3.81,-3.81; 7 6.35,-3.81; 8 8.89,-3.81; 9 8.89,3.81; 10 6.35,3.81; 11 3.81,3.81; 12 1.27,3.81; 13 -1.27,3.81; 14 -3.81,3.81; 15 -6.35,3.81; 16 -8.89,3.81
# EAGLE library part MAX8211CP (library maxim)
VOLTAGE MONITOR

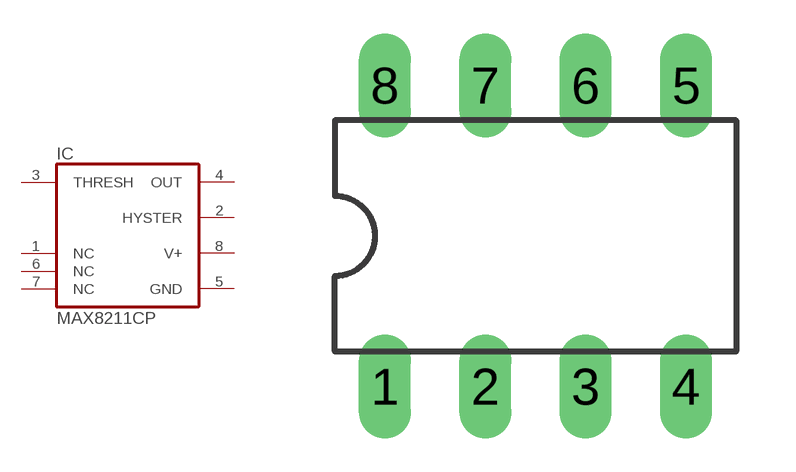
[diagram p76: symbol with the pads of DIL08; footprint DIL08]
Designator prefix IC

## MAX8211CP (MF: MAXIM; MPN: MAX8211CPA+; OC_FARNELL: 1187924; OC_NEWARK: 68K5030)  [DIL08]
1  NC  nc
2  HYSTER  out
3  THRESH  in
4  OUT  out
5  GND  pwr
6  NC  nc
7  NC  nc
8  V+  pwr

## Footprint DIL08 (pad centres in mm)
Dual In Line Package
drill 0.813 long: 1 -3.81,-3.81; 2 -1.27,-3.81; 3 1.27,-3.81; 4 3.81,-3.81; 5 3.81,3.81; 6 1.27,3.81; 7 -1.27,3.81; 8 -3.81,3.81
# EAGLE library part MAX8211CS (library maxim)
VOLTAGE MONITOR

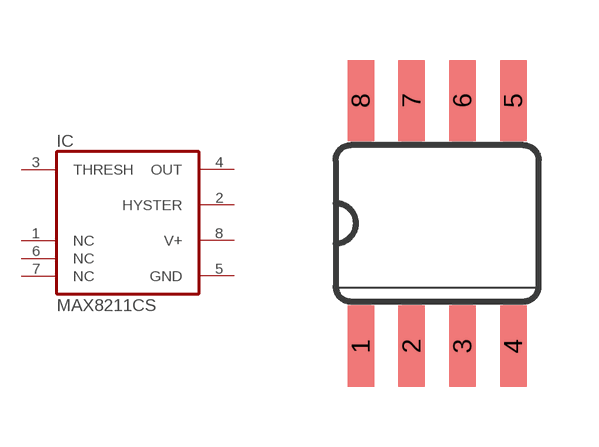
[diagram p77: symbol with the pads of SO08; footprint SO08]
Designator prefix IC

## MAX8211CS (MF: MAXIM; MPN: MAX8211CSA+; OC_FARNELL: 9725911; OC_NEWARK: 68K5031)  [SO08]
1  NC  nc
2  HYSTER  out
3  THRESH  in
4  OUT  out
5  GND  pwr
6  NC  nc
7  NC  nc
8  V+  pwr

## Footprint SO08 (pad centres in mm)
Small Outline Package SOIC 150 mil
smd 0.66 x 2.032: 1 -1.905,-3.073; 2 -0.635,-3.073; 3 0.635,-3.073; 4 1.905,-3.073; 5 1.905,3.073; 6 0.635,3.073; 7 -0.635,3.073; 8 -1.905,3.073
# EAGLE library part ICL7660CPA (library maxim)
VOLTAGE CONVERTER

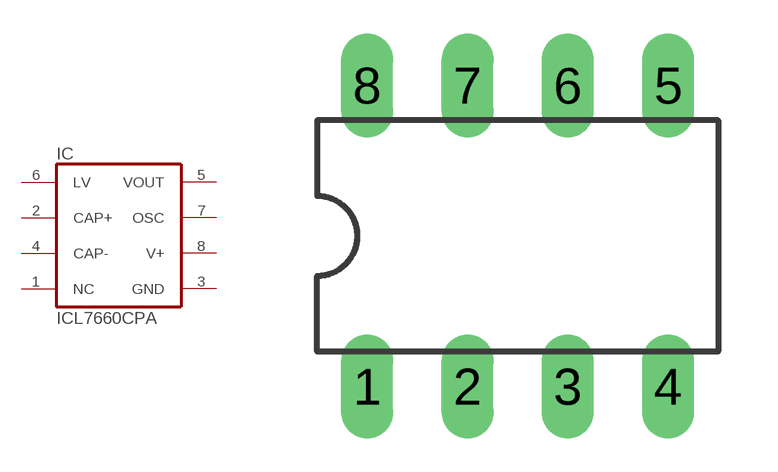
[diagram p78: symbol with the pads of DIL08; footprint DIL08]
Designator prefix IC

## ICL7660CPA (MF: INTERSIL; MPN: ICL7660CPA; OC_FARNELL: 1018170; OC_NEWARK: 06F7441)  [DIL08]
1  NC  nc
2  CAP+  pas
3  GND  pwr
4  CAP-  pas
5  VOUT  out
6  LV  pas
7  OSC  out
8  V+  pwr

## Footprint DIL08 (pad centres in mm)
Dual In Line Package
drill 0.813 long: 1 -3.81,-3.81; 2 -1.27,-3.81; 3 1.27,-3.81; 4 3.81,-3.81; 5 3.81,3.81; 6 1.27,3.81; 7 -1.27,3.81; 8 -3.81,3.81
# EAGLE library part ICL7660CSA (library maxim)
VOLTAGE CONVERTER

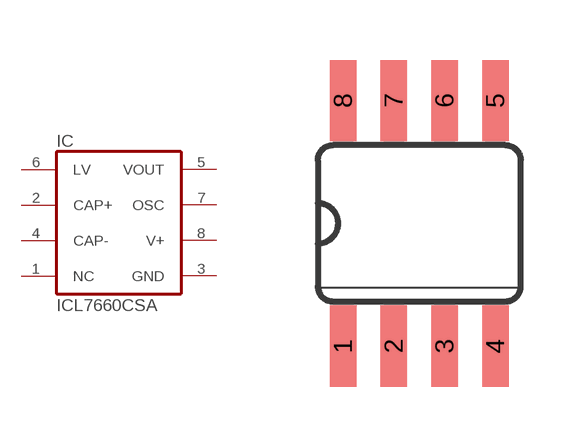
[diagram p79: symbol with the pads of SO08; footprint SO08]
Designator prefix IC

## ICL7660CSA (MF: MAXIM; MPN: ICL7660CSA; OC_FARNELL: 9724710; OC_NEWARK: 34C3732)  [SO08]
1  NC  nc
2  CAP+  pas
3  GND  pwr
4  CAP-  pas
5  VOUT  out
6  LV  pas
7  OSC  out
8  V+  pwr

## Footprint SO08 (pad centres in mm)
Small Outline Package SOIC 150 mil
smd 0.66 x 2.032: 1 -1.905,-3.073; 2 -0.635,-3.073; 3 0.635,-3.073; 4 1.905,-3.073; 5 1.905,3.073; 6 0.635,3.073; 7 -0.635,3.073; 8 -1.905,3.073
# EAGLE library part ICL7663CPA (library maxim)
Positive VOLTAGE REGULATOR

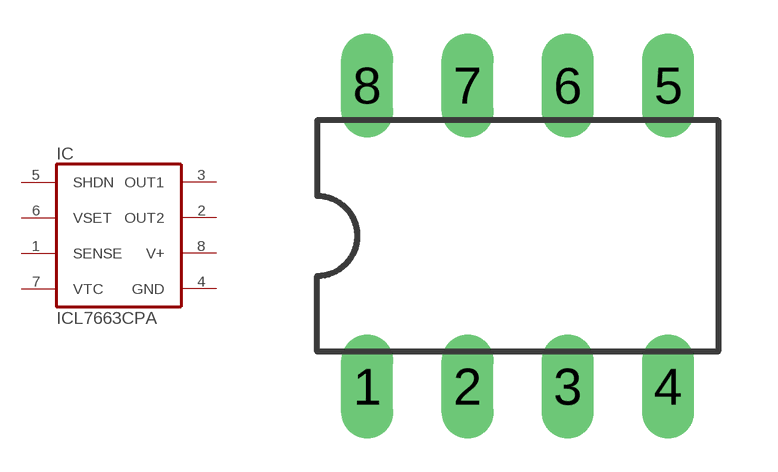
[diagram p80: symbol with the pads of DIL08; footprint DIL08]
Designator prefix IC

## ICL7663CPA (OC_FARNELL: unknown; OC_NEWARK: unknown)  [DIL08]
1  SENSE  in
2  OUT2  out
3  OUT1  out
4  GND  pwr
5  SHDN  in
6  VSET  in
7  VTC  pas
8  V+  pwr

## Footprint DIL08 (pad centres in mm)
Dual In Line Package
drill 0.813 long: 1 -3.81,-3.81; 2 -1.27,-3.81; 3 1.27,-3.81; 4 3.81,-3.81; 5 3.81,3.81; 6 1.27,3.81; 7 -1.27,3.81; 8 -3.81,3.81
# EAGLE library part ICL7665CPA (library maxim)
UNDER/OVER VOLTAGE DETECTOR

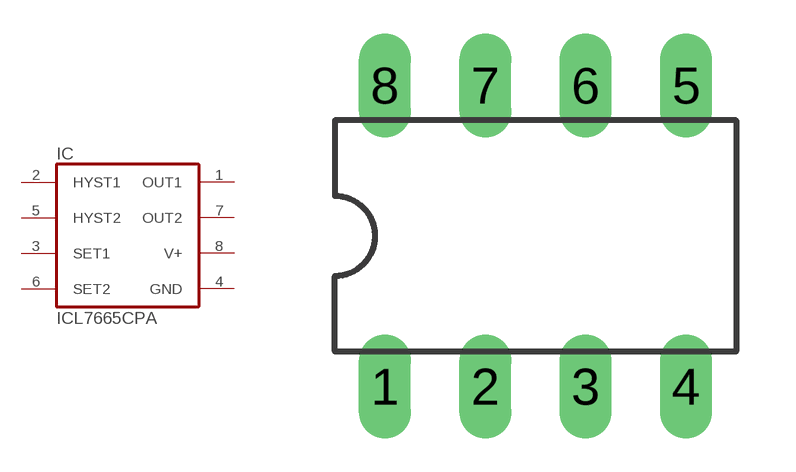
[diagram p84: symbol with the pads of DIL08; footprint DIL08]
Designator prefix IC

## ICL7665CPA (OC_FARNELL: unknown; OC_NEWARK: unknown)  [DIL08]
1  OUT1  out
2  HYST1  in
3  SET1  in
4  GND  pwr
5  HYST2  in
6  SET2  in
7  OUT2  out
8  V+  pwr

## Footprint DIL08 (pad centres in mm)
Dual In Line Package
drill 0.813 long: 1 -3.81,-3.81; 2 -1.27,-3.81; 3 1.27,-3.81; 4 3.81,-3.81; 5 3.81,3.81; 6 1.27,3.81; 7 -1.27,3.81; 8 -3.81,3.81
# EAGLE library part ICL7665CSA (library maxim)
UNDER/OVER VOLTAGE DETECTOR

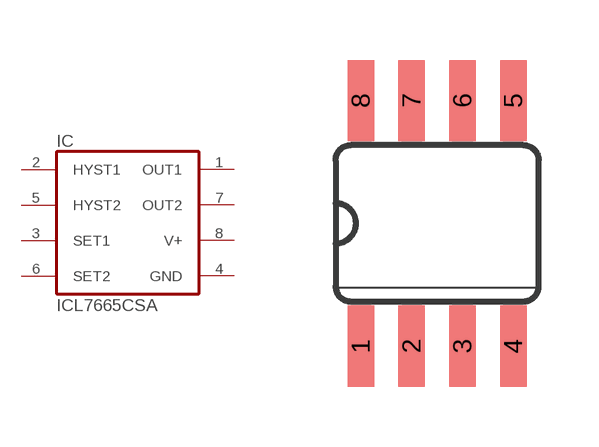
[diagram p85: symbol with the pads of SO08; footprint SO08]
Designator prefix IC

## ICL7665CSA (MPN: ICL7665CSA+; OC_FARNELL: unknown; OC_NEWARK: 19M9537)  [SO08]
1  OUT1  out
2  HYST1  in
3  SET1  in
4  GND  pwr
5  HYST2  in
6  SET2  in
7  OUT2  out
8  V+  pwr

## Footprint SO08 (pad centres in mm)
Small Outline Package SOIC 150 mil
smd 0.66 x 2.032: 1 -1.905,-3.073; 2 -0.635,-3.073; 3 0.635,-3.073; 4 1.905,-3.073; 5 1.905,3.073; 6 0.635,3.073; 7 -0.635,3.073; 8 -1.905,3.073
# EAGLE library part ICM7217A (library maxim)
COUNTER

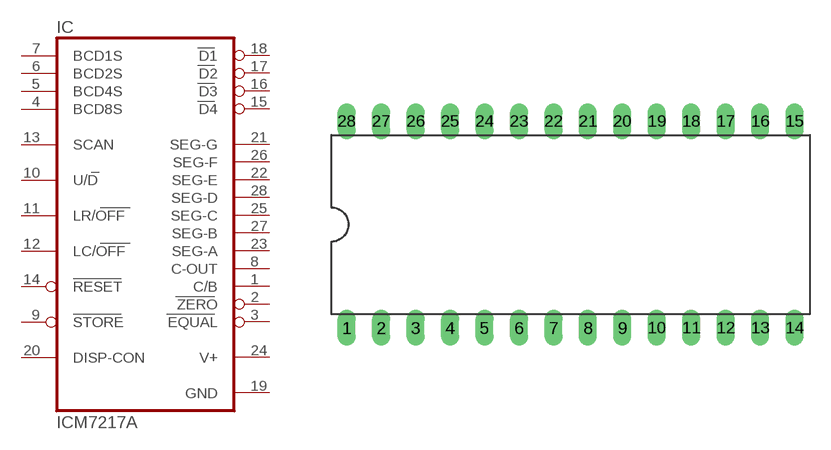
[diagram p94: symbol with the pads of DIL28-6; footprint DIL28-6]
Designator prefix IC

## ICM7217A (MF: MAXIM; MPN: ICM7217AIPI+; OC_FARNELL: unknown; OC_NEWARK: 65K5764)  [DIL28-6]
1  C/B  out
2  ZERO  out
3  EQUAL  out
4  BCD8S
5  BCD4S
6  BCD2S
7  BCD1S
8  C-OUT  out
9  STORE  in
10  U/D  in
11  LR/OFF  in
12  LC/OFF
13  SCAN  pas
14  RESET  in
15  D4  out
16  D3  out
17  D2  out
18  D1  out
19  GND  pwr
20  DISP-CON  in
21  SEG-G  out
22  SEG-E  out
23  SEG-A  out
24  V+  pwr
25  SEG-C  out
26  SEG-F  out
27  SEG-B  out
28  SEG-D  out

## Footprint DIL28-6 (pad centres in mm)
Dual In Line Package 0.6 inch
drill 0.813 long: 1 -16.51,-7.62; 2 -13.97,-7.62; 3 -11.43,-7.62; 4 -8.89,-7.62; 5 -6.35,-7.62; 6 -3.81,-7.62; 7 -1.27,-7.62; 8 1.27,-7.62; 9 3.81,-7.62; 10 6.35,-7.62; 11 8.89,-7.62; 12 11.43,-7.62; 13 13.97,-7.62; 14 16.51,-7.62; 15 16.51,7.62; 16 13.97,7.62; 17 11.43,7.62; 18 8.89,7.62; 19 6.35,7.62; 20 3.81,7.62; 21 1.27,7.62; 22 -1.27,7.62; 23 -3.81,7.62; 24 -6.35,7.62; 25 -8.89,7.62; 26 -11.43,7.62; 27 -13.97,7.62; 28 -16.51,7.62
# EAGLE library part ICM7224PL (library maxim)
LCD COUNTER/DECODER/ DRIVER

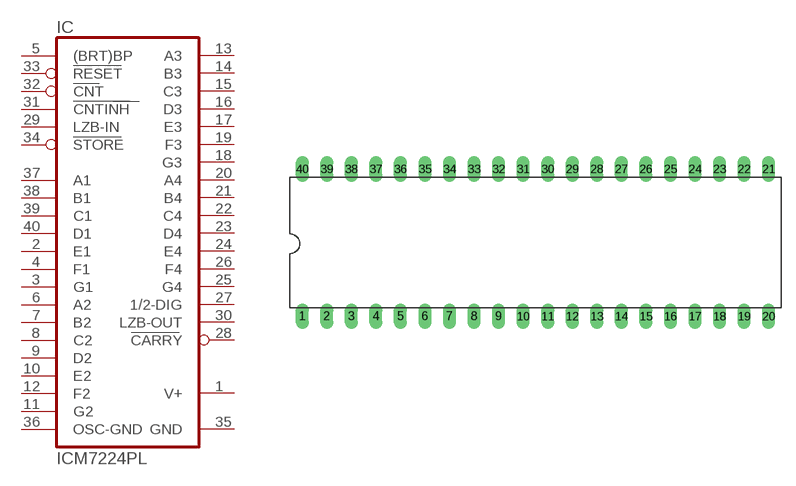
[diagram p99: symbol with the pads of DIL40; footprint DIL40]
Designator prefix IC

## ICM7224PL (OC_FARNELL: unknown; OC_NEWARK: unknown)  [DIL40]
1  V+  pwr
2  E1  out
3  G1  out
4  F1  out
5  (BRT)BP
6  A2  out
7  B2  out
8  C2  out
9  D2  out
10  E2  out
11  G2  out
12  F2  out
13  A3  out
14  B3  out
15  C3  out
16  D3  out
17  E3  out
18  G3  out
19  F3  out
20  A4  out
21  B4  out
22  C4  out
23  D4  out
24  E4  out
25  G4  out
26  F4  out
27  1/2-DIG  out
28  CARRY  out
29  LZB-IN  in
30  LZB-OUT  out
31  !CNTINH  in
32  CNT  in
33  RESET  in
34  STORE  pas
35  GND  pwr
36  OSC-GND  pwr
37  A1  out
38  B1  out
39  C1  out
40  D1  out

## Footprint DIL40 (pad centres in mm)
Dual In Line Package
drill 0.813 long: 1 -24.13,-7.62; 2 -21.59,-7.62; 3 -19.05,-7.62; 4 -16.51,-7.62; 5 -13.97,-7.62; 6 -11.43,-7.62; 7 -8.89,-7.62; 8 -6.35,-7.62; 9 -3.81,-7.62; 10 -1.27,-7.62; 11 1.27,-7.62; 12 3.81,-7.62; 13 6.35,-7.62; 14 8.89,-7.62; 15 11.43,-7.62; 16 13.97,-7.62; 17 16.51,-7.62; 18 19.05,-7.62; 19 21.59,-7.62; 20 24.13,-7.62; 21 24.13,7.62; 22 21.59,7.62; 23 19.05,7.62; 24 16.51,7.62; 25 13.97,7.62; 26 11.43,7.62; 27 8.89,7.62; 28 6.35,7.62; 29 3.81,7.62; 30 1.27,7.62; 31 -1.27,7.62; 32 -3.81,7.62; 33 -6.35,7.62; 34 -8.89,7.62; 35 -11.43,7.62; 36 -13.97,7.62; 37 -16.51,7.62; 38 -19.05,7.62; 39 -21.59,7.62; 40 -24.13,7.62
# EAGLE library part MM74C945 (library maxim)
COUNTER

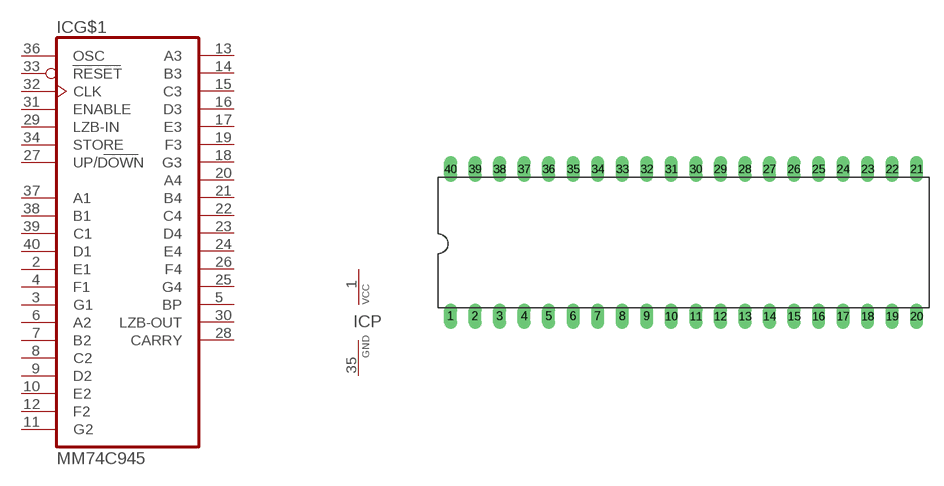
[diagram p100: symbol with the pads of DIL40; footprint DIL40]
Designator prefix IC; gates G$1=MM74C945 P=VCC-GND

## MM74C945 (OC_FARNELL: unknown; OC_NEWARK: unknown)  [DIL40]
1  P:VCC  pwr
2  G$1:E1  out
3  G$1:G1  out
4  G$1:F1  out
5  G$1:BP
6  G$1:A2  out
7  G$1:B2  out
8  G$1:C2  out
9  G$1:D2  out
10  G$1:E2  out
11  G$1:G2  out
12  G$1:F2  out
13  G$1:A3  out
14  G$1:B3  out
15  G$1:C3  out
16  G$1:D3  out
17  G$1:E3  out
18  G$1:G3  out
19  G$1:F3  out
20  G$1:A4  out
21  G$1:B4  out
22  G$1:C4  out
23  G$1:D4  out
24  G$1:E4  out
25  G$1:G4  out
26  G$1:F4  out
27  G$1:UP/DOWN  in
28  G$1:CARRY  out
29  G$1:LZB-IN  in
30  G$1:LZB-OUT  out
31  G$1:ENABLE  in
32  G$1:CLK  in
33  G$1:RESET  in
34  G$1:STORE  in
35  P:GND  pwr
36  G$1:OSC  pas
37  G$1:A1  out
38  G$1:B1  out
39  G$1:C1  out
40  G$1:D1  out

## Footprint DIL40 (pad centres in mm)
Dual In Line Package
drill 0.813 long: 1 -24.13,-7.62; 2 -21.59,-7.62; 3 -19.05,-7.62; 4 -16.51,-7.62; 5 -13.97,-7.62; 6 -11.43,-7.62; 7 -8.89,-7.62; 8 -6.35,-7.62; 9 -3.81,-7.62; 10 -1.27,-7.62; 11 1.27,-7.62; 12 3.81,-7.62; 13 6.35,-7.62; 14 8.89,-7.62; 15 11.43,-7.62; 16 13.97,-7.62; 17 16.51,-7.62; 18 19.05,-7.62; 19 21.59,-7.62; 20 24.13,-7.62; 21 24.13,7.62; 22 21.59,7.62; 23 19.05,7.62; 24 16.51,7.62; 25 13.97,7.62; 26 11.43,7.62; 27 8.89,7.62; 28 6.35,7.62; 29 3.81,7.62; 30 1.27,7.62; 31 -1.27,7.62; 32 -3.81,7.62; 33 -6.35,7.62; 34 -8.89,7.62; 35 -11.43,7.62; 36 -13.97,7.62; 37 -16.51,7.62; 38 -19.05,7.62; 39 -21.59,7.62; 40 -24.13,7.62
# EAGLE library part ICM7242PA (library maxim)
TIMER/COUNTER

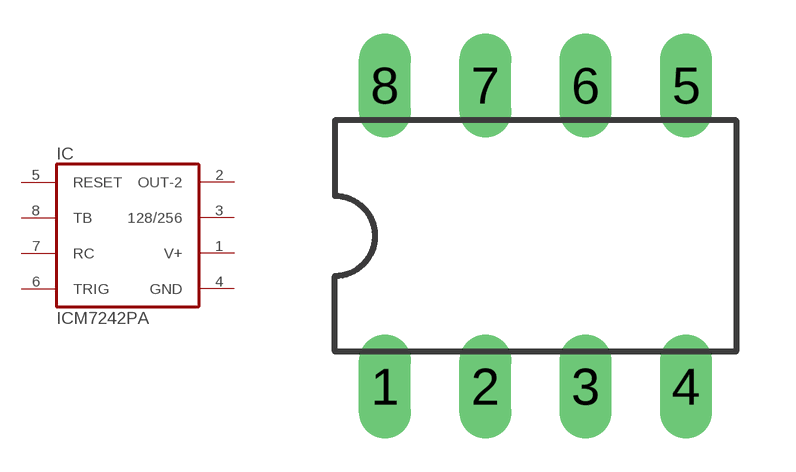
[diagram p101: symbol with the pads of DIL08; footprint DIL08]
Designator prefix IC

## ICM7242PA (OC_FARNELL: unknown; OC_NEWARK: unknown)  [DIL08]
1  V+  pwr
2  OUT-2  out
3  128/256  out
4  GND  pwr
5  RESET  in
6  TRIG
7  RC  pas
8  TB

## Footprint DIL08 (pad centres in mm)
Dual In Line Package
drill 0.813 long: 1 -3.81,-3.81; 2 -1.27,-3.81; 3 1.27,-3.81; 4 3.81,-3.81; 5 3.81,3.81; 6 1.27,3.81; 7 -1.27,3.81; 8 -3.81,3.81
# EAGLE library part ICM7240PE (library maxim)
LCD COUNTER/DECODER/ DRIVER

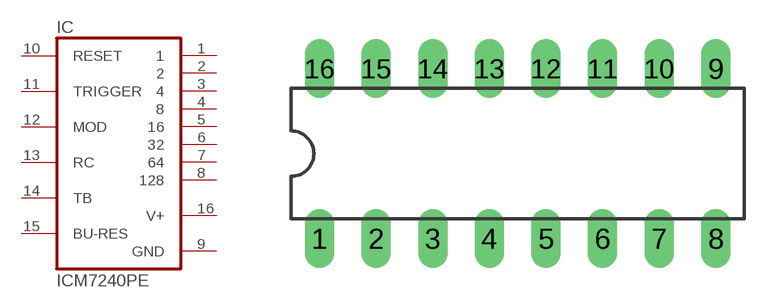
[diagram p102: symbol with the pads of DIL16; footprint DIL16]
Designator prefix IC

## ICM7240PE (OC_FARNELL: unknown; OC_NEWARK: unknown)  [DIL16]
1  1  out
2  2  out
3  4  out
4  8  out
5  16  out
6  32  out
7  64  out
8  128  out
9  GND  pwr
10  RESET  in
11  TRIGGER  in
12  MOD  in
13  RC  pas
14  TB
15  BU-RES  in
16  V+  pwr

## Footprint DIL16 (pad centres in mm)
Dual In Line Package
drill 0.813 long: 1 -8.89,-3.81; 2 -6.35,-3.81; 3 -3.81,-3.81; 4 -1.27,-3.81; 5 1.27,-3.81; 6 3.81,-3.81; 7 6.35,-3.81; 8 8.89,-3.81; 9 8.89,3.81; 10 6.35,3.81; 11 3.81,3.81; 12 1.27,3.81; 13 -1.27,3.81; 14 -3.81,3.81; 15 -6.35,3.81; 16 -8.89,3.81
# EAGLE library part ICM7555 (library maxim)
TIMER

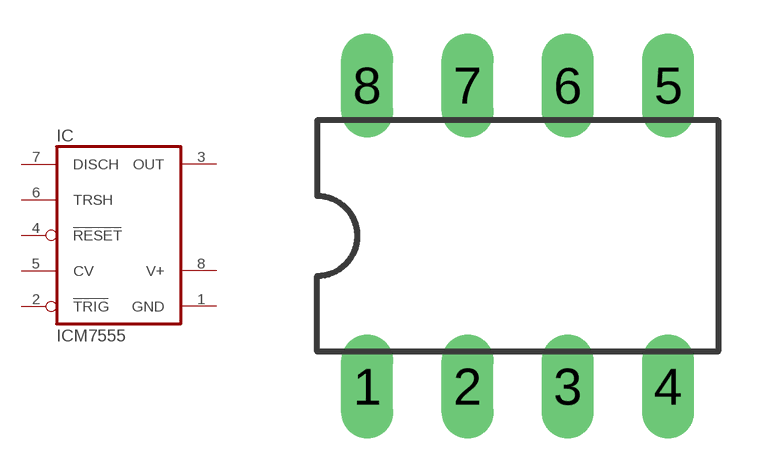
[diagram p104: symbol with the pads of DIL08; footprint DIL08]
Designator prefix IC

## ICM7555 (MF: MAXIM; MPN: ICM7555IPA+; OC_FARNELL: 9663762; OC_NEWARK: 68K4387)  [DIL08]
1  GND  pwr
2  TRIG
3  OUT  out
4  RESET  in
5  CV  pas
6  TRSH  in
7  DISCH  in
8  V+  pwr

## Footprint DIL08 (pad centres in mm)
Dual In Line Package
drill 0.813 long: 1 -3.81,-3.81; 2 -1.27,-3.81; 3 1.27,-3.81; 4 3.81,-3.81; 5 3.81,3.81; 6 1.27,3.81; 7 -1.27,3.81; 8 -3.81,3.81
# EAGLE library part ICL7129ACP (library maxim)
ANALOG/DIGITAL CONVERTER

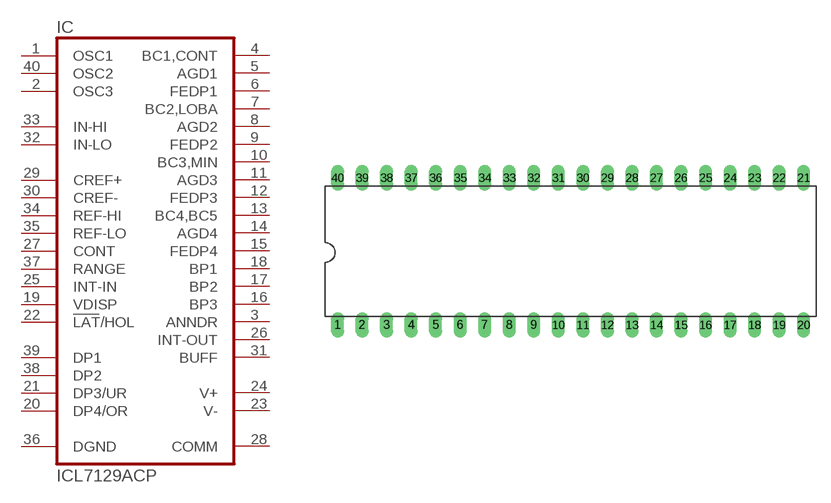
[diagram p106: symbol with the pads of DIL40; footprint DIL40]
Designator prefix IC

## ICL7129ACP (MPN: ICL7129ACPL+; OC_FARNELL: unknown; OC_NEWARK: 89K2377)  [DIL40]
1  OSC1  pas
2  OSC3  pas
3  ANNDR  out
4  BC1,CONT  out
5  AGD1  out
6  FEDP1  out
7  BC2,LOBA  out
8  AGD2  out
9  FEDP2  out
10  BC3,MIN  out
11  AGD3  out
12  FEDP3  out
13  BC4,BC5  out
14  AGD4  out
15  FEDP4  out
16  BP3  out
17  BP2  out
18  BP1  out
19  VDISP  in
20  DP4/OR  in
21  DP3/UR  in
22  LAT/HOL  in
23  V-  pwr
24  V+  pwr
25  INT-IN  pas
26  INT-OUT  out
27  CONT  in
28  COMM  pwr
29  CREF+  pas
30  CREF-  pas
31  BUFF  out
32  IN-LO  in
33  IN-HI  in
34  REF-HI  in
35  REF-LO  in
36  DGND  pwr
37  RANGE  pas
38  DP2  in
39  DP1  in
40  OSC2  pas

## Footprint DIL40 (pad centres in mm)
Dual In Line Package
drill 0.813 long: 1 -24.13,-7.62; 2 -21.59,-7.62; 3 -19.05,-7.62; 4 -16.51,-7.62; 5 -13.97,-7.62; 6 -11.43,-7.62; 7 -8.89,-7.62; 8 -6.35,-7.62; 9 -3.81,-7.62; 10 -1.27,-7.62; 11 1.27,-7.62; 12 3.81,-7.62; 13 6.35,-7.62; 14 8.89,-7.62; 15 11.43,-7.62; 16 13.97,-7.62; 17 16.51,-7.62; 18 19.05,-7.62; 19 21.59,-7.62; 20 24.13,-7.62; 21 24.13,7.62; 22 21.59,7.62; 23 19.05,7.62; 24 16.51,7.62; 25 13.97,7.62; 26 11.43,7.62; 27 8.89,7.62; 28 6.35,7.62; 29 3.81,7.62; 30 1.27,7.62; 31 -1.27,7.62; 32 -3.81,7.62; 33 -6.35,7.62; 34 -8.89,7.62; 35 -11.43,7.62; 36 -13.97,7.62; 37 -16.51,7.62; 38 -19.05,7.62; 39 -21.59,7.62; 40 -24.13,7.62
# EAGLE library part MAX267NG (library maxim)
Switched-capacitor FILTER

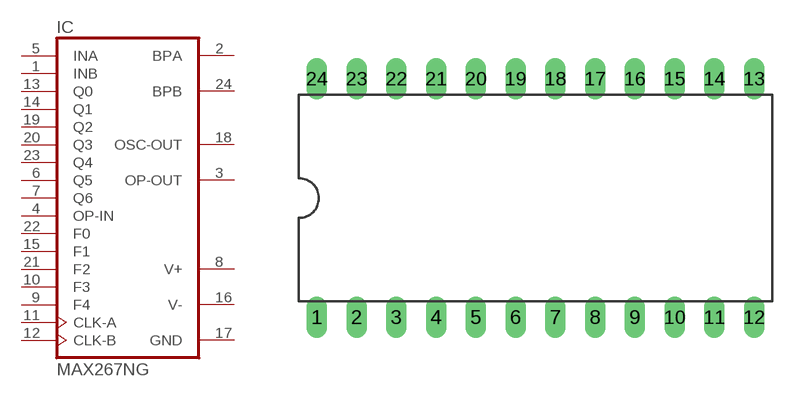
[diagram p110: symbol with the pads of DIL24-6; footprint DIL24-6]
Designator prefix IC

## MAX267NG (OC_FARNELL: unknown; OC_NEWARK: unknown)  [DIL24-6]
1  INB  in
2  BPA  out
3  OP-OUT  out
4  OP-IN  in
5  INA  in
6  Q5  in
7  Q6  in
8  V+  pwr
9  F4  in
10  F3  in
11  CLK-A  in
12  CLK-B  in
13  Q0  in
14  Q1  in
15  F1  in
16  V-  pwr
17  GND  pwr
18  OSC-OUT  out
19  Q2  in
20  Q3  in
21  F2  in
22  F0  in
23  Q4  in
24  BPB  out

## Footprint DIL24-6 (pad centres in mm)
Dual In Line Package 0.6 inch
drill 0.813 long: 1 -13.97,-7.62; 2 -11.43,-7.62; 3 -8.89,-7.62; 4 -6.35,-7.62; 5 -3.81,-7.62; 6 -1.27,-7.62; 7 1.27,-7.62; 8 3.81,-7.62; 9 6.35,-7.62; 10 8.89,-7.62; 11 11.43,-7.62; 12 13.97,-7.62; 13 13.97,7.62; 14 11.43,7.62; 15 8.89,7.62; 16 6.35,7.62; 17 3.81,7.62; 18 1.27,7.62; 19 -1.27,7.62; 20 -3.81,7.62; 21 -6.35,7.62; 22 -8.89,7.62; 23 -11.43,7.62; 24 -13.97,7.62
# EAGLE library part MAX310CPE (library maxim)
MULTIPLEXER

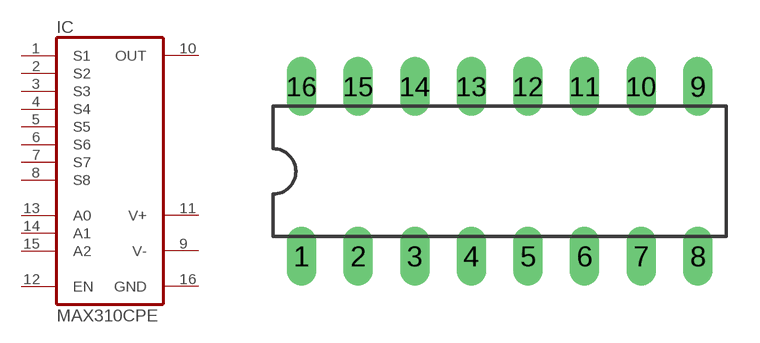
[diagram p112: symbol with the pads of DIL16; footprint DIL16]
Designator prefix IC

## MAX310CPE (MPN: MAX310CPE+; OC_FARNELL: unknown; OC_NEWARK: 76K6683)  [DIL16]
1  S1  pas
2  S2  pas
3  S3  pas
4  S4  pas
5  S5  pas
6  S6  pas
7  S7  pas
8  S8  pas
9  V-  pwr
10  OUT  pas
11  V+  pwr
12  EN  in
13  A0  in
14  A1  in
15  A2  in
16  GND  pwr

## Footprint DIL16 (pad centres in mm)
Dual In Line Package
drill 0.813 long: 1 -8.89,-3.81; 2 -6.35,-3.81; 3 -3.81,-3.81; 4 -1.27,-3.81; 5 1.27,-3.81; 6 3.81,-3.81; 7 6.35,-3.81; 8 8.89,-3.81; 9 8.89,3.81; 10 6.35,3.81; 11 3.81,3.81; 12 1.27,3.81; 13 -1.27,3.81; 14 -3.81,3.81; 15 -6.35,3.81; 16 -8.89,3.81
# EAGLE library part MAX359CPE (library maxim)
MULTIPLEXER

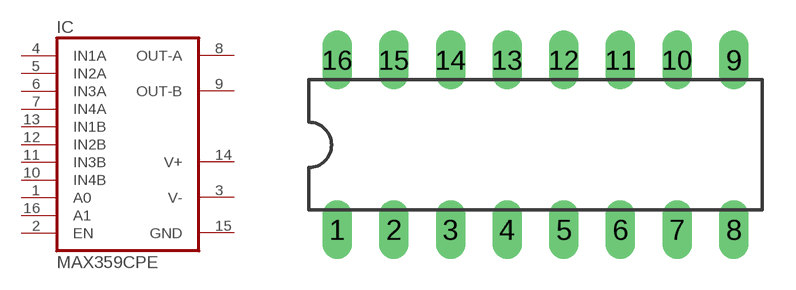
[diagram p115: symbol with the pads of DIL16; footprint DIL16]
Designator prefix IC

## MAX359CPE (MPN: MAX359CPE; OC_FARNELL: unknown; OC_NEWARK: 72C4143)  [DIL16]
1  A0  in
2  EN  in
3  V-  pwr
4  IN1A  pas
5  IN2A  pas
6  IN3A  pas
7  IN4A  pas
8  OUT-A  pas
9  OUT-B  pas
10  IN4B  pas
11  IN3B  pas
12  IN2B  pas
13  IN1B  pas
14  V+  pwr
15  GND  pwr
16  A1  in

## Footprint DIL16 (pad centres in mm)
Dual In Line Package
drill 0.813 long: 1 -8.89,-3.81; 2 -6.35,-3.81; 3 -3.81,-3.81; 4 -1.27,-3.81; 5 1.27,-3.81; 6 3.81,-3.81; 7 6.35,-3.81; 8 8.89,-3.81; 9 8.89,3.81; 10 6.35,3.81; 11 3.81,3.81; 12 1.27,3.81; 13 -1.27,3.81; 14 -3.81,3.81; 15 -6.35,3.81; 16 -8.89,3.81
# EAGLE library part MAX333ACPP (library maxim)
ANALOG SWITCH

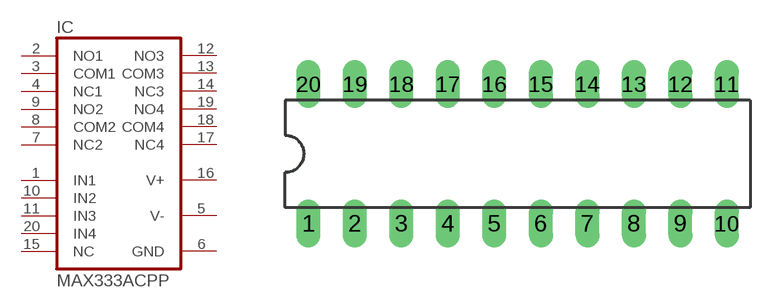
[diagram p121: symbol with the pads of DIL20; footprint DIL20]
Designator prefix IC

## MAX333ACPP (MF: MAXIM; MPN: MAX333ACPP; OC_FARNELL: unknown; OC_NEWARK: 77C9354)  [DIL20]
1  IN1  in
2  NO1  pas
3  COM1  pas
4  NC1  pas
5  V-  pwr
6  GND  pwr
7  NC2  pas
8  COM2  pas
9  NO2  pas
10  IN2  in
11  IN3  in
12  NO3  pas
13  COM3  pas
14  NC3  pas
15  NC  nc
16  V+  pwr
17  NC4  pas
18  COM4  pas
19  NO4  pas
20  IN4  in

## Footprint DIL20 (pad centres in mm)
Dual In Line Package
drill 0.813 long: 1 -11.43,-3.81; 2 -8.89,-3.81; 3 -6.35,-3.81; 4 -3.81,-3.81; 5 -1.27,-3.81; 6 1.27,-3.81; 7 3.81,-3.81; 8 6.35,-3.81; 9 8.89,-3.81; 10 11.43,-3.81; 11 11.43,3.81; 12 8.89,3.81; 13 6.35,3.81; 14 3.81,3.81; 15 1.27,3.81; 16 -1.27,3.81; 17 -3.81,3.81; 18 -6.35,3.81; 19 -8.89,3.81; 20 -11.43,3.81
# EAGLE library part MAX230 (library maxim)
RS232 TRANMITTER

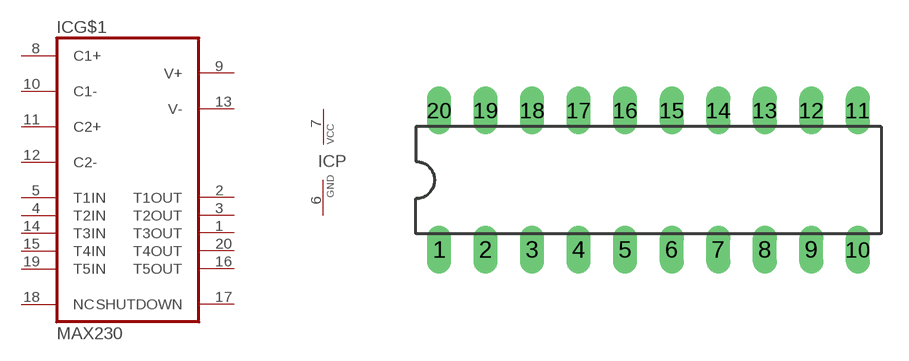
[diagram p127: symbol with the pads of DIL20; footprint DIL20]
Designator prefix IC; gates G$1=MAX230 P=VCC-GND

## MAX230 (MPN: MAX230CPP+; OC_FARNELL: unknown; OC_NEWARK: 28M0326)  [DIL20]
1  G$1:T3OUT  out
2  G$1:T1OUT  out
3  G$1:T2OUT  out
4  G$1:T2IN  in
5  G$1:T1IN  in
6  P:GND  pwr
7  P:VCC  pwr
8  G$1:C1+
9  G$1:V+
10  G$1:C1-
11  G$1:C2+
12  G$1:C2-
13  G$1:V-
14  G$1:T3IN  in
15  G$1:T4IN  in
16  G$1:T5OUT  out
17  G$1:SHUTDOWN  pas
18  G$1:NC  nc
19  G$1:T5IN  in
20  G$1:T4OUT  out

## Footprint DIL20 (pad centres in mm)
Dual In Line Package
drill 0.813 long: 1 -11.43,-3.81; 2 -8.89,-3.81; 3 -6.35,-3.81; 4 -3.81,-3.81; 5 -1.27,-3.81; 6 1.27,-3.81; 7 3.81,-3.81; 8 6.35,-3.81; 9 8.89,-3.81; 10 11.43,-3.81; 11 11.43,3.81; 12 8.89,3.81; 13 6.35,3.81; 14 3.81,3.81; 15 1.27,3.81; 16 -1.27,3.81; 17 -3.81,3.81; 18 -6.35,3.81; 19 -8.89,3.81; 20 -11.43,3.81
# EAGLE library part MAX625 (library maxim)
POWER SUPPLY

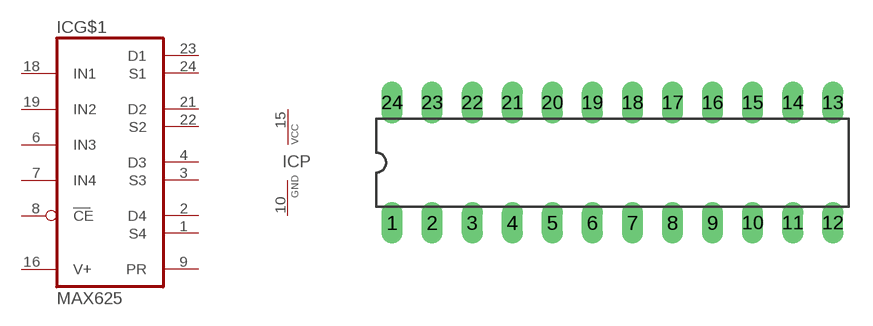
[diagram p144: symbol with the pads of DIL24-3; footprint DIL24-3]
Designator prefix IC; gates G$1=MAX625 P=VCC-GND

## MAX625 (MPN: MAX6250AEPA+; OC_FARNELL: 1714966; OC_NEWARK: 89K4247)  [DIL24-3]
1  G$1:S4  out
2  G$1:D4  in
3  G$1:S3  out
4  G$1:D3  in
6  G$1:IN3  in
7  G$1:IN4  in
8  G$1:CE  in
9  G$1:PR  out
10  P:GND  pwr
15  P:VCC  pwr
16  G$1:V+  pwr
18  G$1:IN1  in
19  G$1:IN2  in
21  G$1:D2  in
22  G$1:S2  out
23  G$1:D1  in
24  G$1:S1  out

## Footprint DIL24-3 (pad centres in mm)
Dual In Line Package 0.3 inch
drill 0.813 long: 1 -13.97,-3.81; 2 -11.43,-3.81; 3 -8.89,-3.81; 4 -6.35,-3.81; 5 -3.81,-3.81; 6 -1.27,-3.81; 7 1.27,-3.81; 8 3.81,-3.81; 9 6.35,-3.81; 10 8.89,-3.81; 11 11.43,-3.81; 12 13.97,-3.81; 13 13.97,3.81; 14 11.43,3.81; 15 8.89,3.81; 16 6.35,3.81; 17 3.81,3.81; 18 1.27,3.81; 19 -1.27,3.81; 20 -3.81,3.81; 21 -6.35,3.81; 22 -8.89,3.81; 23 -11.43,3.81; 24 -13.97,3.81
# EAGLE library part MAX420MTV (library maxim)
OP AMP

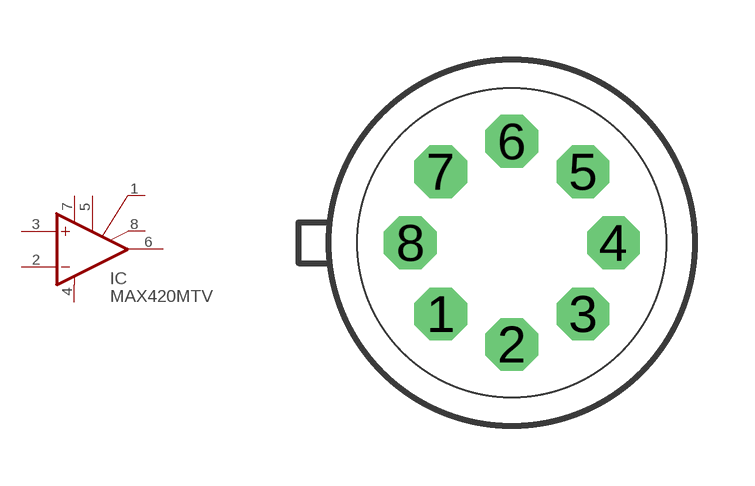
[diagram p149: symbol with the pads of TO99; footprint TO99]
Designator prefix IC

## MAX420MTV (OC_FARNELL: unknown; OC_NEWARK: unknown)  [TO99]
1  CEXT1  pas
2  -IN  in
3  +IN  in
4  V-  pwr
5  CRET  pas
6  OUT  out
7  V+  pwr
8  CEXT2  pas

## Footprint TO99 (pad centres in mm)
TO-99
drill 0.813 octagon: 1 -1.778,-1.778; 2 0,-2.54; 3 1.778,-1.778; 4 2.54,0; 5 1.778,1.778; 6 0,2.54; 7 -1.778,1.778; 8 -2.54,0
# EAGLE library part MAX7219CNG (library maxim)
LED DISPLAY DRIVER

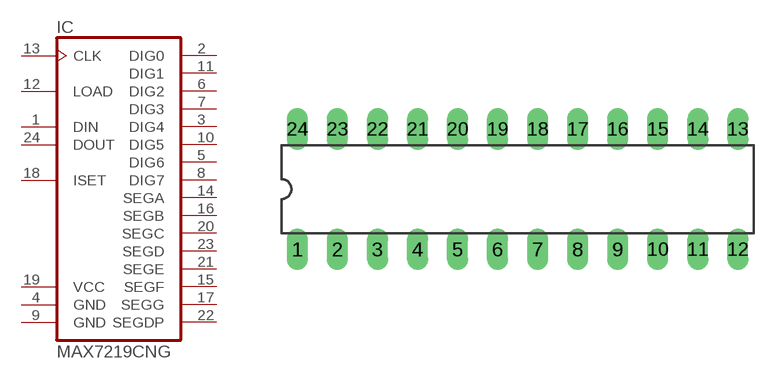
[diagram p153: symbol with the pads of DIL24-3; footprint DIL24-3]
Designator prefix IC

## MAX7219CNG (MF: MAXIM; MPN: MAX7219CNG; OC_FARNELL: 1523914; OC_NEWARK: 34C4018)  [DIL24-3]
1  DIN  in
2  DIG0  out
3  DIG4  out
4  GND  pwr
5  DIG6  out
6  DIG2  out
7  DIG3  out
8  DIG7  out
9  GND  pwr
10  DIG5  out
11  DIG1  out
12  LOAD  in
13  CLK  in
14  SEGA  out
15  SEGF  out
16  SEGB  out
17  SEGG  out
18  ISET  in
19  VCC  pwr
20  SEGC  out
21  SEGE  out
22  SEGDP  out
23  SEGD  out
24  DOUT  out

## Footprint DIL24-3 (pad centres in mm)
Dual In Line Package 0.3 inch
drill 0.813 long: 1 -13.97,-3.81; 2 -11.43,-3.81; 3 -8.89,-3.81; 4 -6.35,-3.81; 5 -3.81,-3.81; 6 -1.27,-3.81; 7 1.27,-3.81; 8 3.81,-3.81; 9 6.35,-3.81; 10 8.89,-3.81; 11 11.43,-3.81; 12 13.97,-3.81; 13 13.97,3.81; 14 11.43,3.81; 15 8.89,3.81; 16 6.35,3.81; 17 3.81,3.81; 18 1.27,3.81; 19 -1.27,3.81; 20 -3.81,3.81; 21 -6.35,3.81; 22 -8.89,3.81; 23 -11.43,3.81; 24 -13.97,3.81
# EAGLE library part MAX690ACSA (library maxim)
WATCHDOG

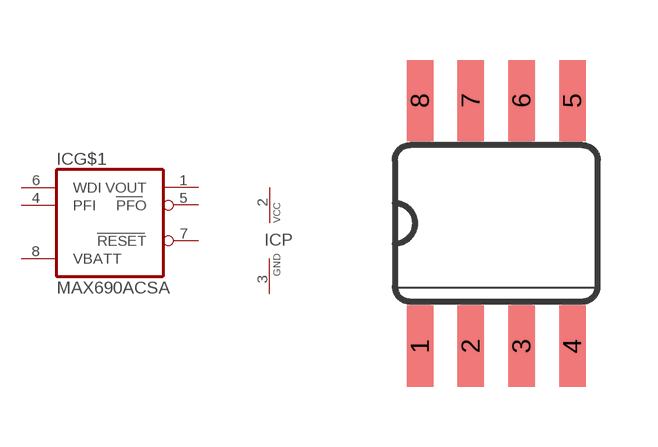
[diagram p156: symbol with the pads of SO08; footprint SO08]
Designator prefix IC; gates G$1=MAX690 P=VCC-GND

## MAX690ACSA (MF: MAXIM; MPN: MAX690ACSA+; OC_FARNELL: 9725938; OC_NEWARK: 59J6361)  [SO08]
1  G$1:VOUT  out
2  P:VCC  pwr
3  P:GND  pwr
4  G$1:PFI  in
5  G$1:PFO  out
6  G$1:WDI  in
7  G$1:RESET  out
8  G$1:VBATT  in

## Footprint SO08 (pad centres in mm)
Small Outline Package SOIC 150 mil
smd 0.66 x 2.032: 1 -1.905,-3.073; 2 -0.635,-3.073; 3 0.635,-3.073; 4 1.905,-3.073; 5 1.905,3.073; 6 0.635,3.073; 7 -0.635,3.073; 8 -1.905,3.073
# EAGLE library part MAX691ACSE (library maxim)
WATCHDOG

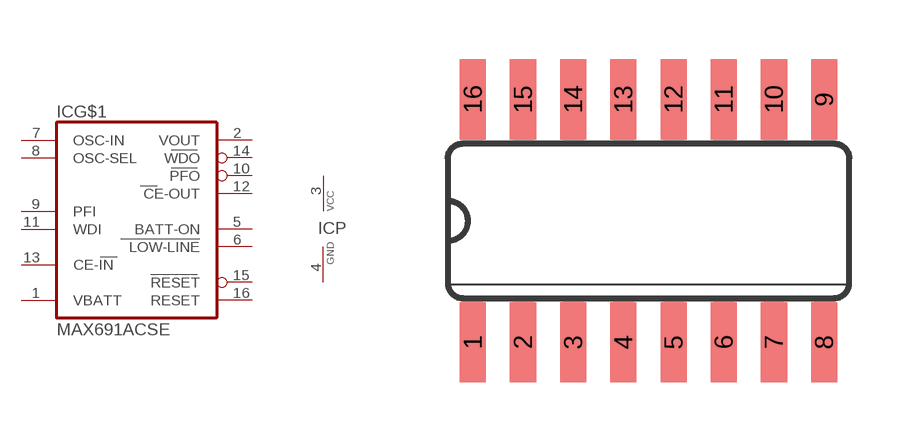
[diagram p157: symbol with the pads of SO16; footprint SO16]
Designator prefix IC; gates G$1=MAX691 P=VCC-GND

## MAX691ACSE (MF: MAXIM; MPN: MAX691ACSE+; OC_FARNELL: 9725946; OC_NEWARK: 67K6559)  [SO16]
1  G$1:VBATT  in
2  G$1:VOUT  out
3  P:VCC  pwr
4  P:GND  pwr
5  G$1:BATT-ON  out
6  G$1:LOW-LINE  out
7  G$1:OSC-IN  pas
8  G$1:OSC-SEL  pas
9  G$1:PFI  in
10  G$1:PFO  out
11  G$1:WDI  in
12  G$1:CE-OUT  out
13  G$1:CE-IN  in
14  G$1:WDO  out
15  G$1:RESET  out
16  G$1:RESET  out

## Footprint SO16 (pad centres in mm)
Small Outline Package .150 SIOC Source: http://www.maxim-ic.com/package_drawings/21-0041B.pdf
smd 0.66 x 2.032: 1 -4.445,-3.073; 2 -3.175,-3.073; 3 -1.905,-3.073; 4 -0.635,-3.073; 5 0.635,-3.073; 6 1.905,-3.073; 7 3.175,-3.073; 8 4.445,-3.073; 9 4.445,3.073; 10 3.175,3.073; 11 1.905,3.073; 12 0.635,3.073; 13 -0.635,3.073; 14 -1.905,3.073; 15 -3.175,3.073; 16 -4.445,3.073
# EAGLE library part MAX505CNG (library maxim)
DIGITAL/ANALOG CONVERTER

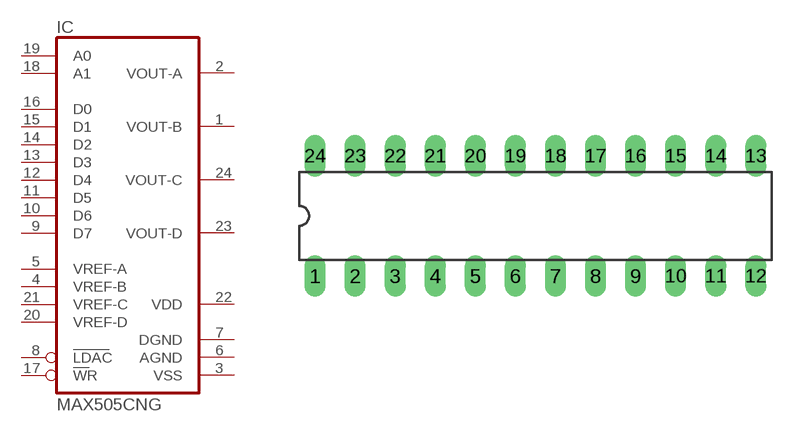
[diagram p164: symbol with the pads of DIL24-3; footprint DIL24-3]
Designator prefix IC

## MAX505CNG (OC_FARNELL: unknown; OC_NEWARK: unknown)  [DIL24-3]
1  VOUT-B  out
2  VOUT-A  out
3  VSS  pwr
4  VREF-B  in
5  VREF-A  in
6  AGND  pwr
7  DGND  pwr
8  LDAC  in
9  D7  in
10  D6  in
11  D5  in
12  D4  in
13  D3  in
14  D2  in
15  D1  in
16  D0  in
17  WR  in
18  A1  in
19  A0  in
20  VREF-D  in
21  VREF-C  in
22  VDD  pwr
23  VOUT-D  out
24  VOUT-C  out

## Footprint DIL24-3 (pad centres in mm)
Dual In Line Package 0.3 inch
drill 0.813 long: 1 -13.97,-3.81; 2 -11.43,-3.81; 3 -8.89,-3.81; 4 -6.35,-3.81; 5 -3.81,-3.81; 6 -1.27,-3.81; 7 1.27,-3.81; 8 3.81,-3.81; 9 6.35,-3.81; 10 8.89,-3.81; 11 11.43,-3.81; 12 13.97,-3.81; 13 13.97,3.81; 14 11.43,3.81; 15 8.89,3.81; 16 6.35,3.81; 17 3.81,3.81; 18 1.27,3.81; 19 -1.27,3.81; 20 -3.81,3.81; 21 -6.35,3.81; 22 -8.89,3.81; 23 -11.43,3.81; 24 -13.97,3.81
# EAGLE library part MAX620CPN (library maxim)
MOSFET DRIVER

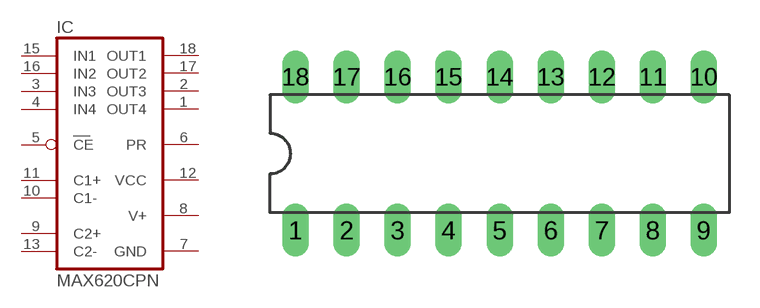
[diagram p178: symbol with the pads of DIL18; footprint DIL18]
Designator prefix IC

## MAX620CPN (MPN: MAX620CPN+; OC_FARNELL: unknown; OC_NEWARK: 27M4142)  [DIL18]
1  OUT4  out
2  OUT3  out
3  IN3  in
4  IN4  in
5  CE  in
6  PR  out
7  GND  pwr
8  V+  sup
9  C2+  pas
10  C1-  pas
11  C1+  pas
12  VCC  pwr
13  C2-  pas
15  IN1  in
16  IN2  in
17  OUT2  out
18  OUT1  out

## Footprint DIL18 (pad centres in mm)
Dual In Line Package
drill 0.813 long: 1 -10.16,-3.81; 2 -7.62,-3.81; 3 -5.08,-3.81; 4 -2.54,-3.81; 5 0,-3.81; 6 2.54,-3.81; 7 5.08,-3.81; 8 7.62,-3.81; 9 10.16,-3.81; 10 10.16,3.81; 11 7.62,3.81; 12 5.08,3.81; 13 2.54,3.81; 14 0,3.81; 15 -2.54,3.81; 16 -5.08,3.81; 17 -7.62,3.81; 18 -10.16,3.81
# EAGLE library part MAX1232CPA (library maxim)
MONITOR DEVICE

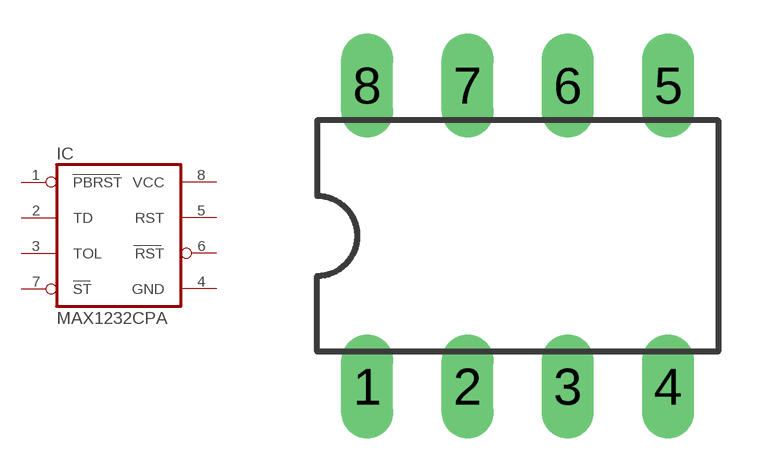
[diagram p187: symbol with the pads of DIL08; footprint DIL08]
Designator prefix IC

## MAX1232CPA (MPN: MAX1232CPA; OC_FARNELL: 9723757; OC_NEWARK: 34C3766)  [DIL08]
1  PBRST  in
2  TD  in
3  TOL  in
4  GND  pwr
5  RST  out
6  RST  out
7  ST  in
8  VCC  pwr

## Footprint DIL08 (pad centres in mm)
Dual In Line Package
drill 0.813 long: 1 -3.81,-3.81; 2 -1.27,-3.81; 3 1.27,-3.81; 4 3.81,-3.81; 5 3.81,3.81; 6 1.27,3.81; 7 -1.27,3.81; 8 -3.81,3.81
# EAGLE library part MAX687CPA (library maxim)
Positive VOLTAGE REGULATOR

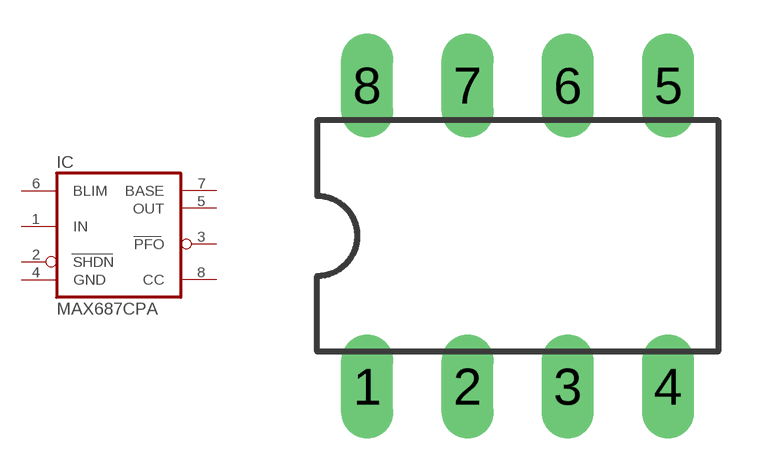
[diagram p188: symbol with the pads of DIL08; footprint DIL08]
Designator prefix IC

## MAX687CPA (OC_FARNELL: unknown; OC_NEWARK: unknown)  [DIL08]
1  IN  in
2  SHDN  in
3  PFO  out
4  GND  pwr
5  OUT  out
6  BLIM  in
7  BASE  out
8  CC  out

## Footprint DIL08 (pad centres in mm)
Dual In Line Package
drill 0.813 long: 1 -3.81,-3.81; 2 -1.27,-3.81; 3 1.27,-3.81; 4 3.81,-3.81; 5 3.81,3.81; 6 1.27,3.81; 7 -1.27,3.81; 8 -3.81,3.81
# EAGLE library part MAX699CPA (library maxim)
WATCHDOG

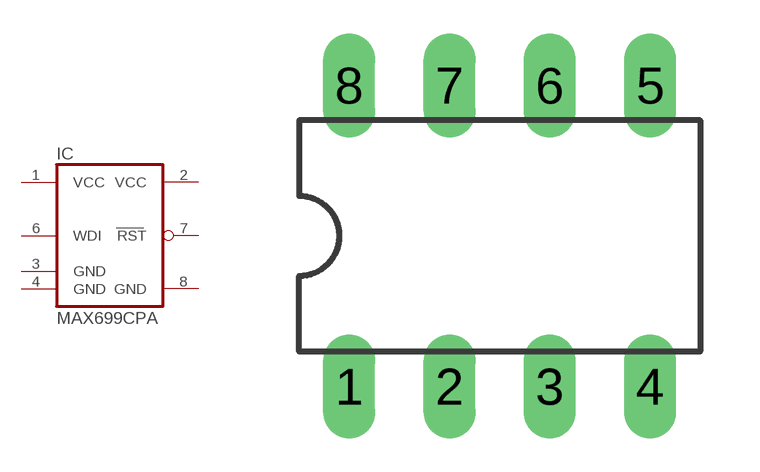
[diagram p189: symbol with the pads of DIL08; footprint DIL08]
Designator prefix IC

## MAX699CPA (MF: MAXIM; MPN: MAX699CPA+; OC_FARNELL: unknown; OC_NEWARK: 65K7644)  [DIL08]
1  VCC  pwr
2  VCC  pwr
3  GND  pwr
4  GND  pwr
6  WDI  in
7  RST  out
8  GND  pwr

## Footprint DIL08 (pad centres in mm)
Dual In Line Package
drill 0.813 long: 1 -3.81,-3.81; 2 -1.27,-3.81; 3 1.27,-3.81; 4 3.81,-3.81; 5 3.81,3.81; 6 1.27,3.81; 7 -1.27,3.81; 8 -3.81,3.81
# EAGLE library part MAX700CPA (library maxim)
POWER SUPPLY MONITOR

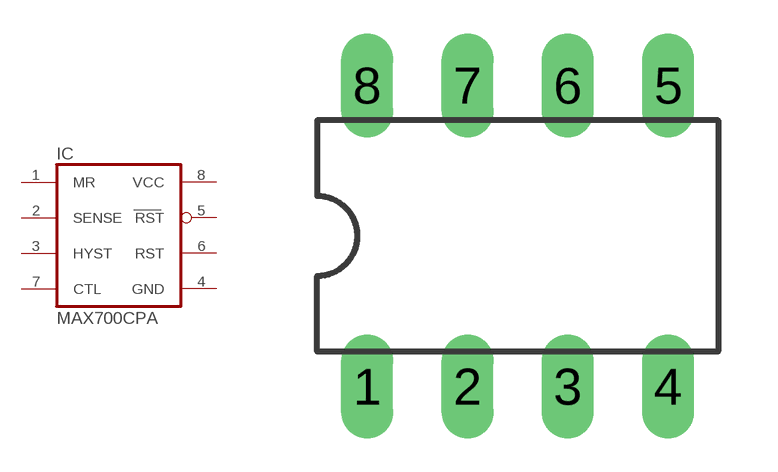
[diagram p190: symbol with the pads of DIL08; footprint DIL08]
Designator prefix IC

## MAX700CPA (MF: MAXIM; MPN: MAX700CPA+; OC_FARNELL: 1187927; OC_NEWARK: 68K4995)  [DIL08]
1  MR  in
2  SENSE  in
3  HYST  pas
4  GND  pwr
5  RST  out
6  RST  out
7  CTL  in
8  VCC  pwr

## Footprint DIL08 (pad centres in mm)
Dual In Line Package
drill 0.813 long: 1 -3.81,-3.81; 2 -1.27,-3.81; 3 1.27,-3.81; 4 3.81,-3.81; 5 3.81,3.81; 6 1.27,3.81; 7 -1.27,3.81; 8 -3.81,3.81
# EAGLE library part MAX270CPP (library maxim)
DIGITAL FILTER

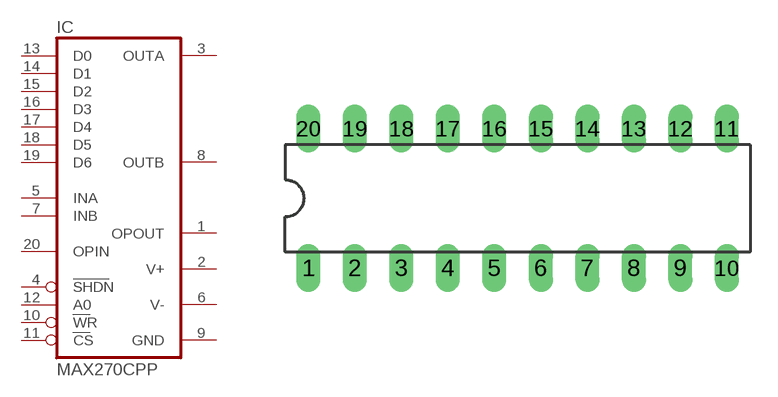
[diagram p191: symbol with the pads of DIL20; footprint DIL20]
Designator prefix IC

## MAX270CPP (OC_FARNELL: unknown; OC_NEWARK: unknown)  [DIL20]
1  OPOUT  out
2  V+  pwr
3  OUTA  out
4  SHDN  in
5  INA  in
6  V-  pwr
7  INB  in
8  OUTB  out
9  GND  pwr
10  WR  in
11  CS  in
12  A0  in
13  D0  in
14  D1  in
15  D2  in
16  D3  in
17  D4  in
18  D5  in
19  D6  in
20  OPIN  in

## Footprint DIL20 (pad centres in mm)
Dual In Line Package
drill 0.813 long: 1 -11.43,-3.81; 2 -8.89,-3.81; 3 -6.35,-3.81; 4 -3.81,-3.81; 5 -1.27,-3.81; 6 1.27,-3.81; 7 3.81,-3.81; 8 6.35,-3.81; 9 8.89,-3.81; 10 11.43,-3.81; 11 11.43,3.81; 12 8.89,3.81; 13 6.35,3.81; 14 3.81,3.81; 15 1.27,3.81; 16 -1.27,3.81; 17 -3.81,3.81; 18 -6.35,3.81; 19 -8.89,3.81; 20 -11.43,3.81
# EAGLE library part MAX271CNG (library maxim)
DIGITAL FILTER

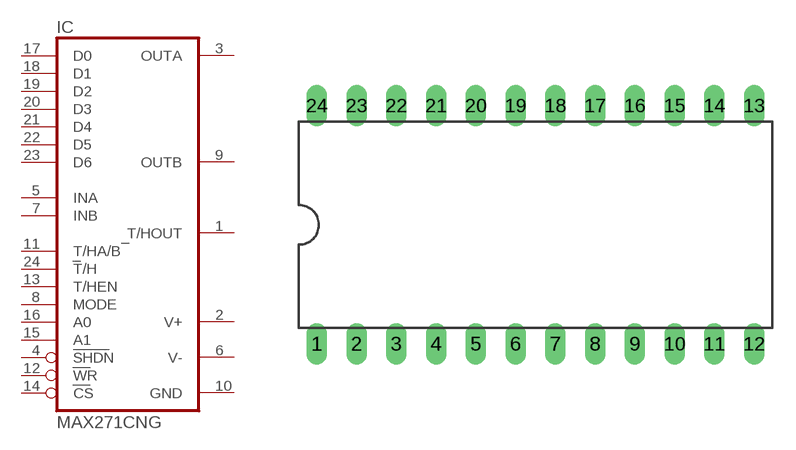
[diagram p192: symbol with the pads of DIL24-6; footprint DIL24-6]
Designator prefix IC

## MAX271CNG (MPN: MAX271CNG+; OC_FARNELL: unknown; OC_NEWARK: 89K3556)  [DIL24-6]
1  T/HOUT  out
2  V+  pwr
3  OUTA  out
4  SHDN  in
5  INA  in
6  V-  pwr
7  INB  in
8  MODE  in
9  OUTB  out
10  GND  pwr
11  T/HA/B  in
12  WR  in
13  T/HEN  in
14  CS  in
15  A1  in
16  A0  in
17  D0  in
18  D1  in
19  D2  in
20  D3  in
21  D4  in
22  D5  in
23  D6  in
24  T/H  in

## Footprint DIL24-6 (pad centres in mm)
Dual In Line Package 0.6 inch
drill 0.813 long: 1 -13.97,-7.62; 2 -11.43,-7.62; 3 -8.89,-7.62; 4 -6.35,-7.62; 5 -3.81,-7.62; 6 -1.27,-7.62; 7 1.27,-7.62; 8 3.81,-7.62; 9 6.35,-7.62; 10 8.89,-7.62; 11 11.43,-7.62; 12 13.97,-7.62; 13 13.97,7.62; 14 11.43,7.62; 15 8.89,7.62; 16 6.35,7.62; 17 3.81,7.62; 18 1.27,7.62; 19 -1.27,7.62; 20 -3.81,7.62; 21 -6.35,7.62; 22 -8.89,7.62; 23 -11.43,7.62; 24 -13.97,7.62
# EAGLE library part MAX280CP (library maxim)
Switched-capacitor FILTER

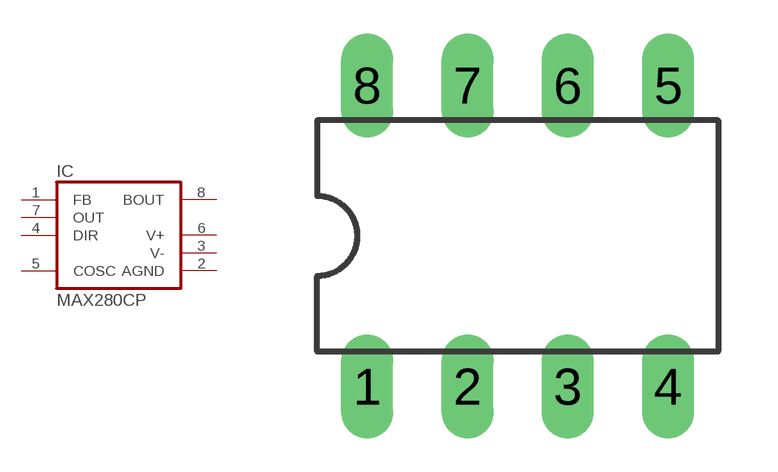
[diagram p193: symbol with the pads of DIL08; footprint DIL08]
Designator prefix IC

## MAX280CP (MPN: MAX280CPA+; OC_FARNELL: unknown; OC_NEWARK: 89K3562)  [DIL08]
1  FB  in
2  AGND  pwr
3  V-  pwr
4  DIR  in
5  COSC  in
6  V+  pwr
7  OUT  in
8  BOUT  out

## Footprint DIL08 (pad centres in mm)
Dual In Line Package
drill 0.813 long: 1 -3.81,-3.81; 2 -1.27,-3.81; 3 1.27,-3.81; 4 3.81,-3.81; 5 3.81,3.81; 6 1.27,3.81; 7 -1.27,3.81; 8 -3.81,3.81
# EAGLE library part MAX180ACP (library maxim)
ANALOG/DIGITAL CONVERTER

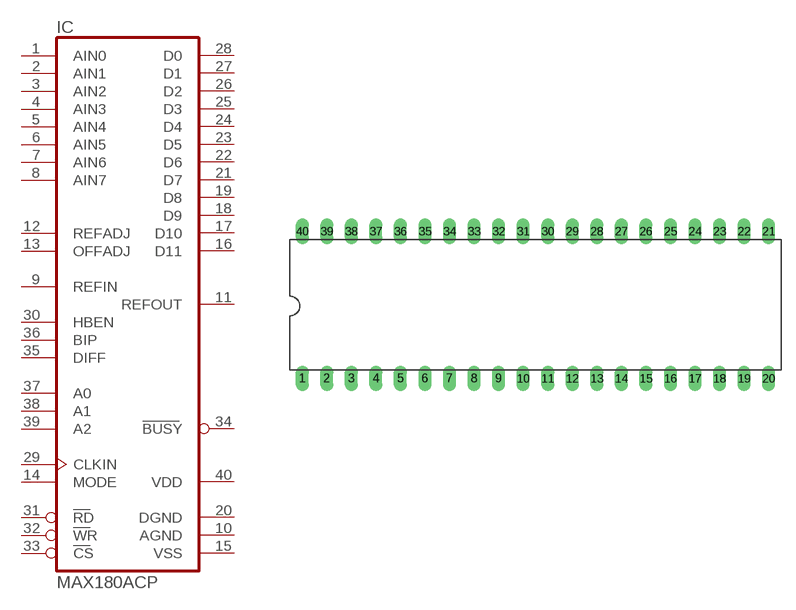
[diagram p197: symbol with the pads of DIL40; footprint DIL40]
Designator prefix IC

## MAX180ACP (MPN: MAX180ACPL+; OC_FARNELL: unknown; OC_NEWARK: 99K3055)  [DIL40]
1  AIN0  in
2  AIN1  in
3  AIN2  in
4  AIN3  in
5  AIN4  in
6  AIN5  in
7  AIN6  in
8  AIN7  in
9  REFIN  in
10  AGND  pwr
11  REFOUT  sup
12  REFADJ  in
13  OFFADJ  in
14  MODE  in
15  VSS  pwr
16  D11  hiz
17  D10  hiz
18  D9  hiz
19  D8  hiz
20  DGND  pwr
21  D7  hiz
22  D6  hiz
23  D5  hiz
24  D4  hiz
25  D3  hiz
26  D2  hiz
27  D1  hiz
28  D0  hiz
29  CLKIN  in
30  HBEN  in
31  RD  in
32  WR  in
33  CS  in
34  BUSY  out
35  DIFF  in
36  BIP  in
37  A0  in
38  A1  in
39  A2  in
40  VDD  pwr

## Footprint DIL40 (pad centres in mm)
Dual In Line Package
drill 0.813 long: 1 -24.13,-7.62; 2 -21.59,-7.62; 3 -19.05,-7.62; 4 -16.51,-7.62; 5 -13.97,-7.62; 6 -11.43,-7.62; 7 -8.89,-7.62; 8 -6.35,-7.62; 9 -3.81,-7.62; 10 -1.27,-7.62; 11 1.27,-7.62; 12 3.81,-7.62; 13 6.35,-7.62; 14 8.89,-7.62; 15 11.43,-7.62; 16 13.97,-7.62; 17 16.51,-7.62; 18 19.05,-7.62; 19 21.59,-7.62; 20 24.13,-7.62; 21 24.13,7.62; 22 21.59,7.62; 23 19.05,7.62; 24 16.51,7.62; 25 13.97,7.62; 26 11.43,7.62; 27 8.89,7.62; 28 6.35,7.62; 29 3.81,7.62; 30 1.27,7.62; 31 -1.27,7.62; 32 -3.81,7.62; 33 -6.35,7.62; 34 -8.89,7.62; 35 -11.43,7.62; 36 -13.97,7.62; 37 -16.51,7.62; 38 -19.05,7.62; 39 -21.59,7.62; 40 -24.13,7.62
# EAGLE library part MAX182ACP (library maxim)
ANALOG/DIGITAL CONVERTER

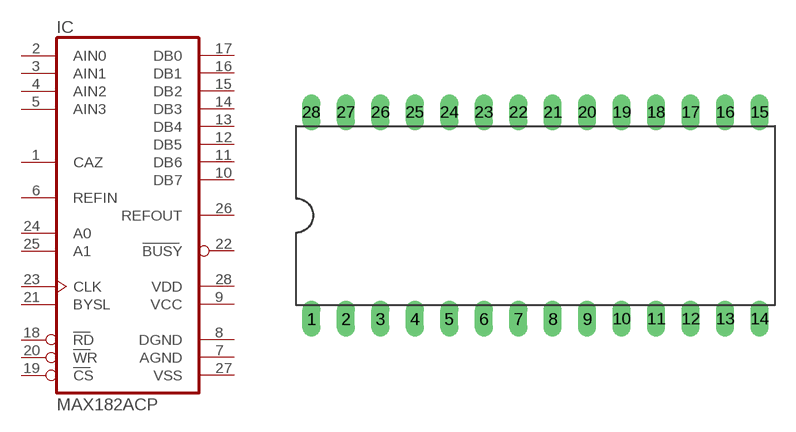
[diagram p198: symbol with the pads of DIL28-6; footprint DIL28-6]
Designator prefix IC

## MAX182ACP (MPN: MAX182ACPI+; OC_FARNELL: unknown; OC_NEWARK: 89K3312)  [DIL28-6]
1  CAZ  in
2  AIN0  in
3  AIN1  in
4  AIN2  in
5  AIN3  in
6  REFIN  in
7  AGND  pwr
8  DGND  pwr
9  VCC  pwr
10  DB7  hiz
11  DB6  hiz
12  DB5  hiz
13  DB4  hiz
14  DB3  hiz
15  DB2  hiz
16  DB1  hiz
17  DB0  hiz
18  RD  in
19  CS  in
20  WR  in
21  BYSL  in
22  BUSY  out
23  CLK  in
24  A0  in
25  A1  in
26  REFOUT  sup
27  VSS  pwr
28  VDD  pwr

## Footprint DIL28-6 (pad centres in mm)
Dual In Line Package 0.6 inch
drill 0.813 long: 1 -16.51,-7.62; 2 -13.97,-7.62; 3 -11.43,-7.62; 4 -8.89,-7.62; 5 -6.35,-7.62; 6 -3.81,-7.62; 7 -1.27,-7.62; 8 1.27,-7.62; 9 3.81,-7.62; 10 6.35,-7.62; 11 8.89,-7.62; 12 11.43,-7.62; 13 13.97,-7.62; 14 16.51,-7.62; 15 16.51,7.62; 16 13.97,7.62; 17 11.43,7.62; 18 8.89,7.62; 19 6.35,7.62; 20 3.81,7.62; 21 1.27,7.62; 22 -1.27,7.62; 23 -3.81,7.62; 24 -6.35,7.62; 25 -8.89,7.62; 26 -11.43,7.62; 27 -13.97,7.62; 28 -16.51,7.62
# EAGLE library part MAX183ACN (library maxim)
ANALOG/DIGITAL CONVERTER

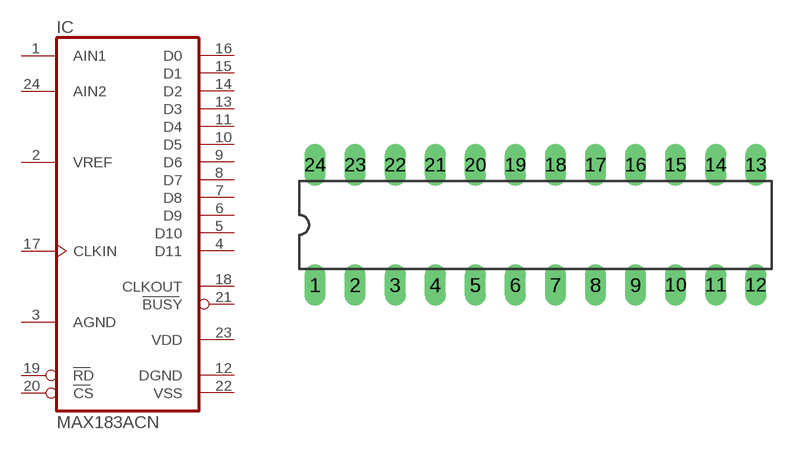
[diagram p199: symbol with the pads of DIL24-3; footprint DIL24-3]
Designator prefix IC

## MAX183ACN (OC_FARNELL: unknown; OC_NEWARK: unknown)  [DIL24-3]
1  AIN1  in
2  VREF  in
3  AGND  pwr
4  D11  hiz
5  D10  hiz
6  D9  hiz
7  D8  hiz
8  D7  hiz
9  D6  hiz
10  D5  hiz
11  D4  hiz
12  DGND  pwr
13  D3  hiz
14  D2  hiz
15  D1  hiz
16  D0  hiz
17  CLKIN  in
18  CLKOUT  out
19  RD  in
20  CS  in
21  BUSY  out
22  VSS  pwr
23  VDD  pwr
24  AIN2  in

## Footprint DIL24-3 (pad centres in mm)
Dual In Line Package 0.3 inch
drill 0.813 long: 1 -13.97,-3.81; 2 -11.43,-3.81; 3 -8.89,-3.81; 4 -6.35,-3.81; 5 -3.81,-3.81; 6 -1.27,-3.81; 7 1.27,-3.81; 8 3.81,-3.81; 9 6.35,-3.81; 10 8.89,-3.81; 11 11.43,-3.81; 12 13.97,-3.81; 13 13.97,3.81; 14 11.43,3.81; 15 8.89,3.81; 16 6.35,3.81; 17 3.81,3.81; 18 1.27,3.81; 19 -1.27,3.81; 20 -3.81,3.81; 21 -6.35,3.81; 22 -8.89,3.81; 23 -11.43,3.81; 24 -13.97,3.81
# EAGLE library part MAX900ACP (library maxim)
VOLTAGE COMPARATOR

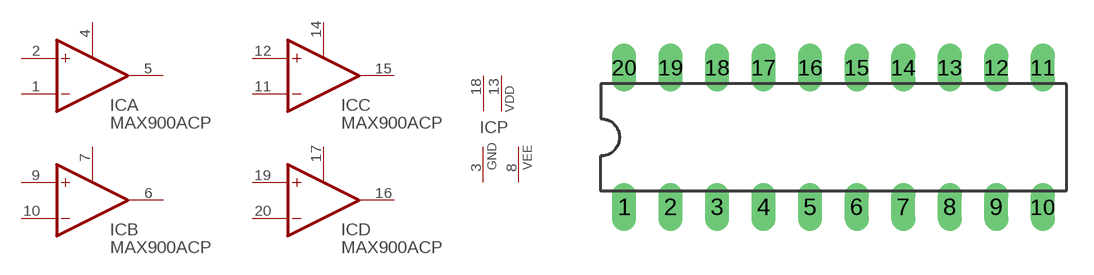
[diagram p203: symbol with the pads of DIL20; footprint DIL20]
Designator prefix IC; gates A=MAX900 B=MAX900 C=MAX900 D=MAX900 P=PWR1

## MAX900ACP (OC_FARNELL: unknown; OC_NEWARK: unknown)  [DIL20]
1  A:-IN  in
2  A:+IN  in
3  P:GND  pwr
4  A:LATCH  pas
5  A:OUT  out
6  B:OUT  out
7  B:LATCH  pas
8  P:VEE  pwr
9  B:+IN  in
10  B:-IN  in
11  C:-IN  in
12  C:+IN  in
13  P:VDD  pwr
14  C:LATCH  pas
15  C:OUT  out
16  D:OUT  out
17  D:LATCH  pas
18  P:VCC  pwr
19  D:+IN  in
20  D:-IN  in

## Footprint DIL20 (pad centres in mm)
Dual In Line Package
drill 0.813 long: 1 -11.43,-3.81; 2 -8.89,-3.81; 3 -6.35,-3.81; 4 -3.81,-3.81; 5 -1.27,-3.81; 6 1.27,-3.81; 7 3.81,-3.81; 8 6.35,-3.81; 9 8.89,-3.81; 10 11.43,-3.81; 11 11.43,3.81; 12 8.89,3.81; 13 6.35,3.81; 14 3.81,3.81; 15 1.27,3.81; 16 -1.27,3.81; 17 -3.81,3.81; 18 -6.35,3.81; 19 -8.89,3.81; 20 -11.43,3.81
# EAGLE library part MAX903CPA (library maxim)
VOLTAGE COMPARATOR

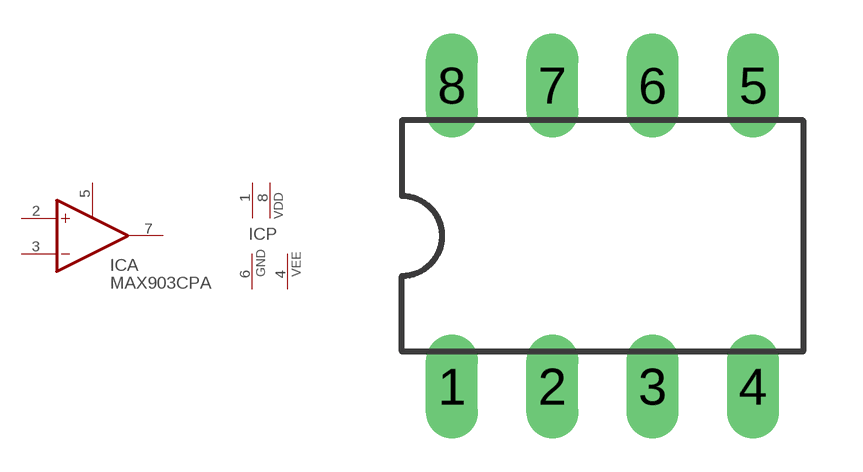
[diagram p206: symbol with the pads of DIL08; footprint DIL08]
Designator prefix IC; gates A=MAX900 P=PWR1

## MAX903CPA (MF: MAXIM; MPN: MAX903CPA+; OC_FARNELL: unknown; OC_NEWARK: 68K5059)  [DIL08]
1  P:VCC  pwr
2  A:+IN  in
3  A:-IN  in
4  P:VEE  pwr
5  A:LATCH  pas
6  P:GND  pwr
7  A:OUT  out
8  P:VDD  pwr

## Footprint DIL08 (pad centres in mm)
Dual In Line Package
drill 0.813 long: 1 -3.81,-3.81; 2 -1.27,-3.81; 3 1.27,-3.81; 4 3.81,-3.81; 5 3.81,3.81; 6 1.27,3.81; 7 -1.27,3.81; 8 -3.81,3.81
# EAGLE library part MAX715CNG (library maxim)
SUPPLY SYSTEM

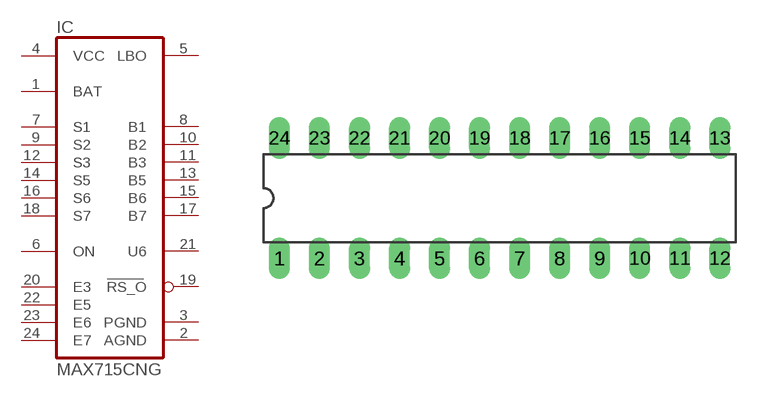
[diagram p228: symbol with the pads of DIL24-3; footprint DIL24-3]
Designator prefix IC

## MAX715CNG (OC_FARNELL: unknown; OC_NEWARK: unknown)  [DIL24-3]
1  BAT  in
2  AGND  pwr
3  PGND  pwr
4  VCC  pwr
5  LBO  out
6  ON  pas
7  S1  in
8  B1  out
9  S2  in
10  B2  out
11  B3  out
12  S3  in
13  B5  out
14  S5  in
15  B6  out
16  S6  in
17  B7  out
18  S7  in
19  RS_O  out
20  E3  pas
21  U6  out
22  E5  pas
23  E6  pas
24  E7  pas

## Footprint DIL24-3 (pad centres in mm)
Dual In Line Package 0.3 inch
drill 0.813 long: 1 -13.97,-3.81; 2 -11.43,-3.81; 3 -8.89,-3.81; 4 -6.35,-3.81; 5 -3.81,-3.81; 6 -1.27,-3.81; 7 1.27,-3.81; 8 3.81,-3.81; 9 6.35,-3.81; 10 8.89,-3.81; 11 11.43,-3.81; 12 13.97,-3.81; 13 13.97,3.81; 14 11.43,3.81; 15 8.89,3.81; 16 6.35,3.81; 17 3.81,3.81; 18 1.27,3.81; 19 -1.27,3.81; 20 -3.81,3.81; 21 -6.35,3.81; 22 -8.89,3.81; 23 -11.43,3.81; 24 -13.97,3.81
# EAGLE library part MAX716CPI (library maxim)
SUPPLY SYSTEM

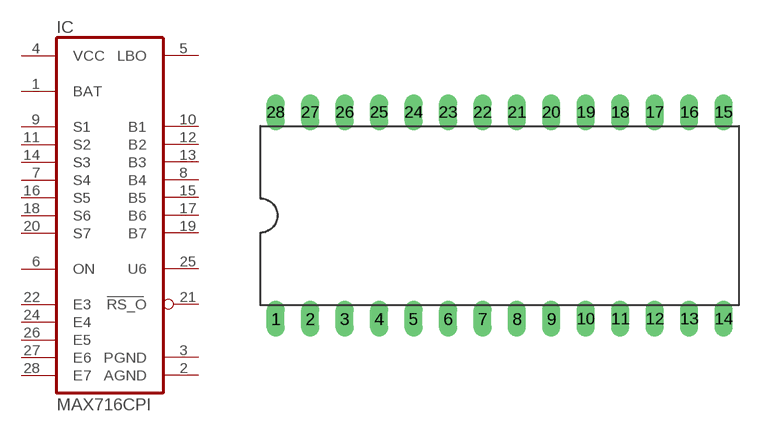
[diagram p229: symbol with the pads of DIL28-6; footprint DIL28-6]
Designator prefix IC

## MAX716CPI (OC_FARNELL: unknown; OC_NEWARK: unknown)  [DIL28-6]
1  BAT  in
2  AGND  pwr
3  PGND  pwr
4  VCC  pwr
5  LBO  out
6  ON  pas
7  S4  in
8  B4  out
9  S1  in
10  B1  out
11  S2  in
12  B2  out
13  B3  out
14  S3  in
15  B5  out
16  S5  in
17  B6  out
18  S6  in
19  B7  out
20  S7  in
21  RS_O  out
22  E3  pas
24  E4  pas
25  U6  out
26  E5  pas
27  E6  pas
28  E7  pas

## Footprint DIL28-6 (pad centres in mm)
Dual In Line Package 0.6 inch
drill 0.813 long: 1 -16.51,-7.62; 2 -13.97,-7.62; 3 -11.43,-7.62; 4 -8.89,-7.62; 5 -6.35,-7.62; 6 -3.81,-7.62; 7 -1.27,-7.62; 8 1.27,-7.62; 9 3.81,-7.62; 10 6.35,-7.62; 11 8.89,-7.62; 12 11.43,-7.62; 13 13.97,-7.62; 14 16.51,-7.62; 15 16.51,7.62; 16 13.97,7.62; 17 11.43,7.62; 18 8.89,7.62; 19 6.35,7.62; 20 3.81,7.62; 21 1.27,7.62; 22 -1.27,7.62; 23 -3.81,7.62; 24 -6.35,7.62; 25 -8.89,7.62; 26 -11.43,7.62; 27 -13.97,7.62; 28 -16.51,7.62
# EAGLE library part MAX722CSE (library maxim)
Positive VOLTAGE REGULATOR

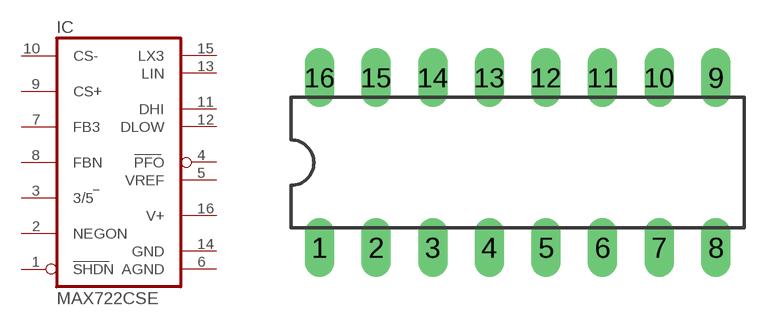
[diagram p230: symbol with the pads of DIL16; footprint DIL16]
Designator prefix IC

## MAX722CSE (MPN: MAX722CSE+; OC_FARNELL: unknown; OC_NEWARK: 28M3052)  [DIL16]
1  SHDN  in
2  NEGON  in
3  3/5  in
4  PFO  out
5  VREF  out
6  AGND  pwr
7  FB3  in
8  FBN  in
9  CS+  in
10  CS-  in
11  DHI  out
12  DLOW  out
13  LIN  out
14  GND  pwr
15  LX3  out
16  V+  pwr

## Footprint DIL16 (pad centres in mm)
Dual In Line Package
drill 0.813 long: 1 -8.89,-3.81; 2 -6.35,-3.81; 3 -3.81,-3.81; 4 -1.27,-3.81; 5 1.27,-3.81; 6 3.81,-3.81; 7 6.35,-3.81; 8 8.89,-3.81; 9 8.89,3.81; 10 6.35,3.81; 11 3.81,3.81; 12 1.27,3.81; 13 -1.27,3.81; 14 -3.81,3.81; 15 -6.35,3.81; 16 -8.89,3.81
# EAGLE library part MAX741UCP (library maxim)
PWM CONTROLLER

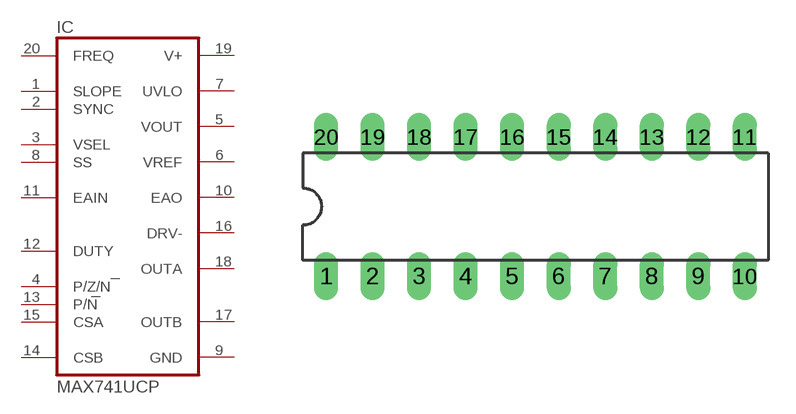
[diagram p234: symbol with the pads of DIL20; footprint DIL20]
Designator prefix IC

## MAX741UCP (OC_FARNELL: unknown; OC_NEWARK: unknown)  [DIL20]
1  SLOPE  pas
2  SYNC  pas
3  VSEL  in
4  P/Z/N  in
5  VOUT  out
6  VREF  out
7  UVLO  out
8  SS  in
9  GND  pwr
10  EAO  out
11  EAIN  in
12  DUTY  in
13  P/N  in
14  CSB  in
15  CSA  in
16  DRV-  out
17  OUTB  out
18  OUTA  out
19  V+  pwr
20  FREQ  in

## Footprint DIL20 (pad centres in mm)
Dual In Line Package
drill 0.813 long: 1 -11.43,-3.81; 2 -8.89,-3.81; 3 -6.35,-3.81; 4 -3.81,-3.81; 5 -1.27,-3.81; 6 1.27,-3.81; 7 3.81,-3.81; 8 6.35,-3.81; 9 8.89,-3.81; 10 11.43,-3.81; 11 11.43,3.81; 12 8.89,3.81; 13 6.35,3.81; 14 3.81,3.81; 15 1.27,3.81; 16 -1.27,3.81; 17 -3.81,3.81; 18 -6.35,3.81; 19 -8.89,3.81; 20 -11.43,3.81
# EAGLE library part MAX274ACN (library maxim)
ANALOG FILTER

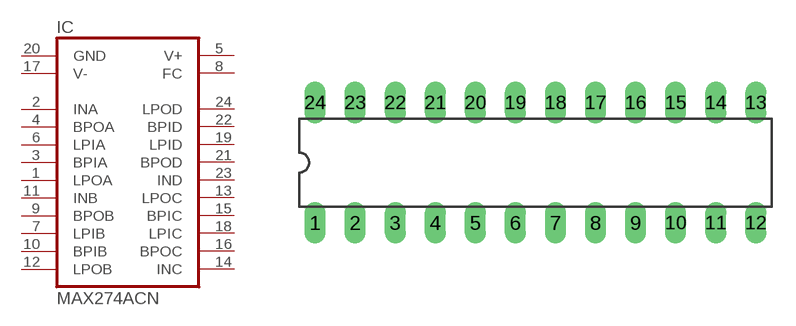
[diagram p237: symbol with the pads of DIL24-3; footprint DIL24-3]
Designator prefix IC

## MAX274ACN (OC_FARNELL: unknown; OC_NEWARK: unknown)  [DIL24-3]
1  LPOA  out
2  INA  in
3  BPIA  in
4  BPOA  out
5  V+  pwr
6  LPIA  in
7  LPIB  in
8  FC  pas
9  BPOB  out
10  BPIB  in
11  INB  in
12  LPOB  out
13  LPOC  out
14  INC  out
15  BPIC  in
16  BPOC  in
17  V-  pwr
18  LPIC  in
19  LPID  in
20  GND  pwr
21  BPOD  out
22  BPID  in
23  IND  in
24  LPOD  out

## Footprint DIL24-3 (pad centres in mm)
Dual In Line Package 0.3 inch
drill 0.813 long: 1 -13.97,-3.81; 2 -11.43,-3.81; 3 -8.89,-3.81; 4 -6.35,-3.81; 5 -3.81,-3.81; 6 -1.27,-3.81; 7 1.27,-3.81; 8 3.81,-3.81; 9 6.35,-3.81; 10 8.89,-3.81; 11 11.43,-3.81; 12 13.97,-3.81; 13 13.97,3.81; 14 11.43,3.81; 15 8.89,3.81; 16 6.35,3.81; 17 3.81,3.81; 18 1.27,3.81; 19 -1.27,3.81; 20 -3.81,3.81; 21 -6.35,3.81; 22 -8.89,3.81; 23 -11.43,3.81; 24 -13.97,3.81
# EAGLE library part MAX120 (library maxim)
ANALOG/DIGITAL CONVERTER

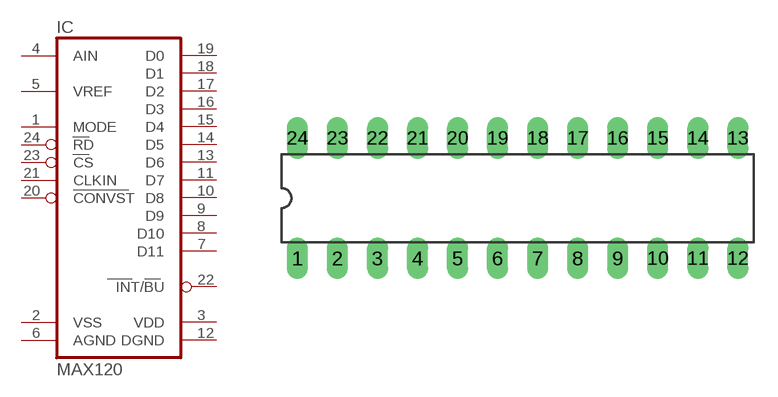
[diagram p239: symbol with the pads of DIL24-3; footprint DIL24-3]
Designator prefix IC

## MAX120 (MPN: MAX120CNG+; OC_FARNELL: unknown; OC_NEWARK: 65K6573)  [DIL24-3]
1  MODE  in
2  VSS  pwr
3  VDD  pwr
4  AIN  in
5  VREF  out
6  AGND  pwr
7  D11  out
8  D10  out
9  D9  out
10  D8  out
11  D7  out
12  DGND  pwr
13  D6  out
14  D5  out
15  D4  out
16  D3  out
17  D2  out
18  D1  out
19  D0  out
20  CONVST  in
21  CLKIN  in
22  INT/BU  out
23  CS  in
24  RD  in

## Footprint DIL24-3 (pad centres in mm)
Dual In Line Package 0.3 inch
drill 0.813 long: 1 -13.97,-3.81; 2 -11.43,-3.81; 3 -8.89,-3.81; 4 -6.35,-3.81; 5 -3.81,-3.81; 6 -1.27,-3.81; 7 1.27,-3.81; 8 3.81,-3.81; 9 6.35,-3.81; 10 8.89,-3.81; 11 11.43,-3.81; 12 13.97,-3.81; 13 13.97,3.81; 14 11.43,3.81; 15 8.89,3.81; 16 6.35,3.81; 17 3.81,3.81; 18 1.27,3.81; 19 -1.27,3.81; 20 -3.81,3.81; 21 -6.35,3.81; 22 -8.89,3.81; 23 -11.43,3.81; 24 -13.97,3.81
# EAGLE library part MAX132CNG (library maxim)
ANALOG/DIGITAL CONVERTER

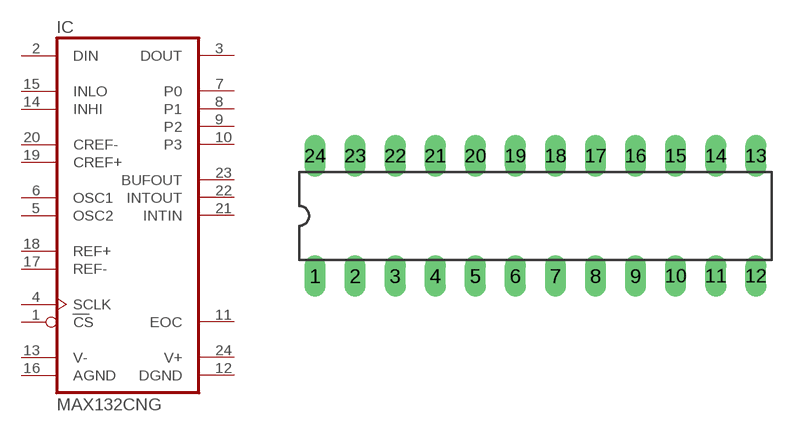
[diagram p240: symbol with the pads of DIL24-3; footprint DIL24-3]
Designator prefix IC

## MAX132CNG (MPN: MAX132CNG+; OC_FARNELL: 1187950; OC_NEWARK: 67K4009)  [DIL24-3]
1  CS  in
2  DIN  in
3  DOUT  out
4  SCLK  in
5  OSC2  pas
6  OSC1  pas
7  P0  out
8  P1  out
9  P2  out
10  P3  out
11  EOC  out
12  DGND  pwr
13  V-  pwr
14  INHI  in
15  INLO  in
16  AGND  pwr
17  REF-  in
18  REF+  in
19  CREF+  pas
20  CREF-  pas
21  INTIN  in
22  INTOUT  out
23  BUFOUT  out
24  V+  pwr

## Footprint DIL24-3 (pad centres in mm)
Dual In Line Package 0.3 inch
drill 0.813 long: 1 -13.97,-3.81; 2 -11.43,-3.81; 3 -8.89,-3.81; 4 -6.35,-3.81; 5 -3.81,-3.81; 6 -1.27,-3.81; 7 1.27,-3.81; 8 3.81,-3.81; 9 6.35,-3.81; 10 8.89,-3.81; 11 11.43,-3.81; 12 13.97,-3.81; 13 13.97,3.81; 14 11.43,3.81; 15 8.89,3.81; 16 6.35,3.81; 17 3.81,3.81; 18 1.27,3.81; 19 -1.27,3.81; 20 -3.81,3.81; 21 -6.35,3.81; 22 -8.89,3.81; 23 -11.43,3.81; 24 -13.97,3.81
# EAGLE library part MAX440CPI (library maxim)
MULTIPLEXER

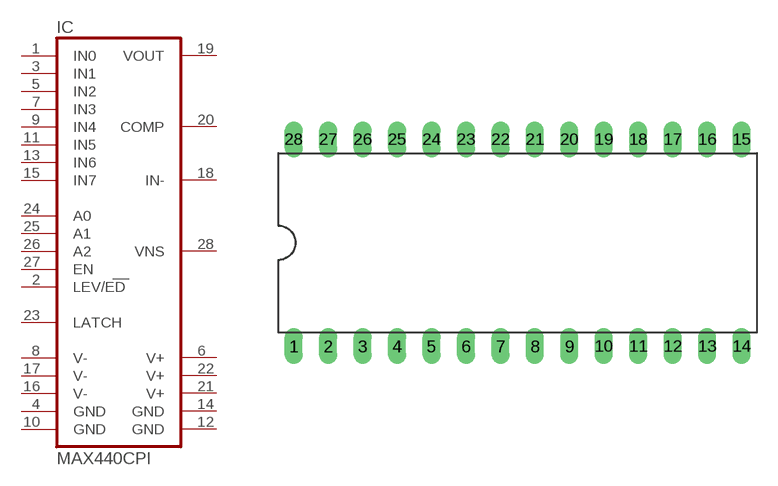
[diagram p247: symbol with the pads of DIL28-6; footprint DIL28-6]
Designator prefix IC

## MAX440CPI (OC_FARNELL: unknown; OC_NEWARK: unknown)  [DIL28-6]
1  IN0  in
2  LEV/ED  in
3  IN1  in
4  GND  pwr
5  IN2  in
6  V+  pwr
7  IN3  in
8  V-  pwr
9  IN4  in
10  GND  pwr
11  IN5  in
12  GND  pwr
13  IN6  in
14  GND  pwr
15  IN7  in
16  V-  pwr
17  V-  pwr
18  IN-  in
19  VOUT  out
20  COMP  nc
21  V+  pwr
22  V+  pwr
23  LATCH  in
24  A0  in
25  A1  in
26  A2  in
27  EN  in
28  VNS  pas

## Footprint DIL28-6 (pad centres in mm)
Dual In Line Package 0.6 inch
drill 0.813 long: 1 -16.51,-7.62; 2 -13.97,-7.62; 3 -11.43,-7.62; 4 -8.89,-7.62; 5 -6.35,-7.62; 6 -3.81,-7.62; 7 -1.27,-7.62; 8 1.27,-7.62; 9 3.81,-7.62; 10 6.35,-7.62; 11 8.89,-7.62; 12 11.43,-7.62; 13 13.97,-7.62; 14 16.51,-7.62; 15 16.51,7.62; 16 13.97,7.62; 17 11.43,7.62; 18 8.89,7.62; 19 6.35,7.62; 20 3.81,7.62; 21 1.27,7.62; 22 -1.27,7.62; 23 -3.81,7.62; 24 -6.35,7.62; 25 -8.89,7.62; 26 -11.43,7.62; 27 -13.97,7.62; 28 -16.51,7.62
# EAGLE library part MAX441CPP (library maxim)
MULTIPLEXER

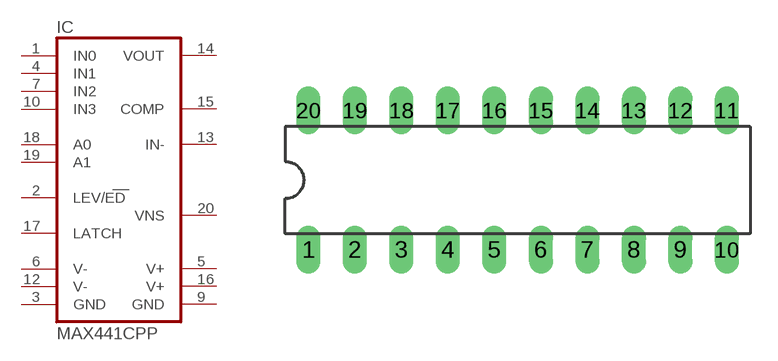
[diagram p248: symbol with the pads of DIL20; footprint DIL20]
Designator prefix IC

## MAX441CPP (OC_FARNELL: unknown; OC_NEWARK: unknown)  [DIL20]
1  IN0  in
2  LEV/ED  in
3  GND  pwr
4  IN1  in
5  V+  pwr
6  V-  pwr
7  IN2  in
9  GND  pwr
10  IN3  in
12  V-  pwr
13  IN-  in
14  VOUT  out
15  COMP  nc
16  V+  pwr
17  LATCH  in
18  A0  in
19  A1  in
20  VNS  pas

## Footprint DIL20 (pad centres in mm)
Dual In Line Package
drill 0.813 long: 1 -11.43,-3.81; 2 -8.89,-3.81; 3 -6.35,-3.81; 4 -3.81,-3.81; 5 -1.27,-3.81; 6 1.27,-3.81; 7 3.81,-3.81; 8 6.35,-3.81; 9 8.89,-3.81; 10 11.43,-3.81; 11 11.43,3.81; 12 8.89,3.81; 13 6.35,3.81; 14 3.81,3.81; 15 1.27,3.81; 16 -1.27,3.81; 17 -3.81,3.81; 18 -6.35,3.81; 19 -8.89,3.81; 20 -11.43,3.81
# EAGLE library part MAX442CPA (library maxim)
MULTIPLEXER

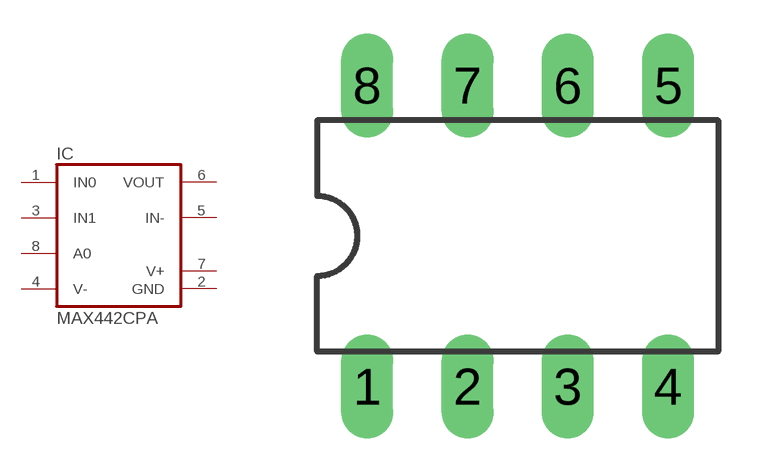
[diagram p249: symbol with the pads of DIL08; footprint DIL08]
Designator prefix IC

## MAX442CPA (OC_FARNELL: unknown; OC_NEWARK: unknown)  [DIL08]
1  IN0  in
2  GND  pwr
3  IN1  in
4  V-  pwr
5  IN-  in
6  VOUT  out
7  V+  pwr
8  A0  in

## Footprint DIL08 (pad centres in mm)
Dual In Line Package
drill 0.813 long: 1 -3.81,-3.81; 2 -1.27,-3.81; 3 1.27,-3.81; 4 3.81,-3.81; 5 3.81,3.81; 6 1.27,3.81; 7 -1.27,3.81; 8 -3.81,3.81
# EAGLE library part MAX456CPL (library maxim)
8 x 8 crosspoint VIDEO SWITCH

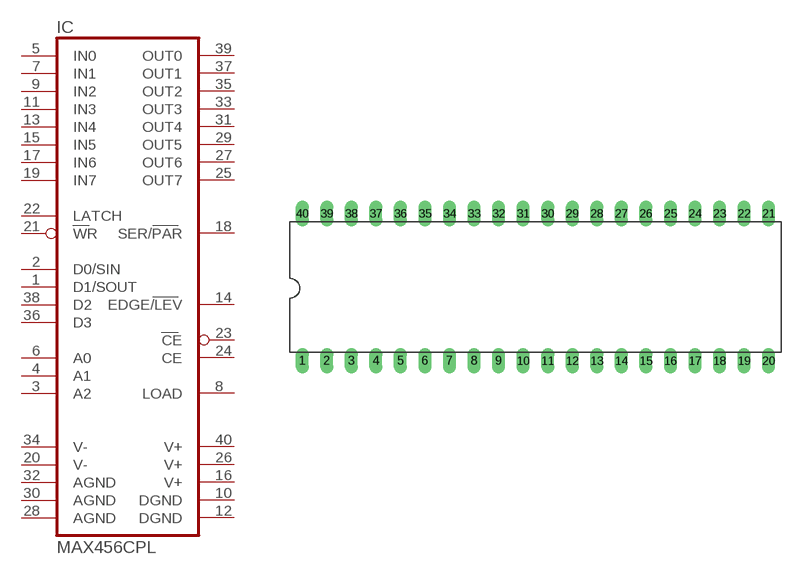
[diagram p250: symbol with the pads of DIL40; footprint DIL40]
Designator prefix IC

## MAX456CPL (MPN: MAX456CPL+; OC_FARNELL: unknown; OC_NEWARK: 65K6903)  [DIL40]
1  D1/SOUT  in
2  D0/SIN  in
3  A2  out
4  A1  out
5  IN0  in
6  A0  out
7  IN1  in
8  LOAD  in
9  IN2  in
10  DGND  pwr
11  IN3  in
12  DGND  pwr
13  IN4  in
14  EDGE/LEV  in
15  IN5  in
16  V+  pwr
17  IN6  in
18  SER/PAR  in
19  IN7  in
20  V-  pwr
21  WR  in
22  LATCH  in
23  CE  in
24  CE  in
25  OUT7  out
26  V+  pwr
27  OUT6  out
28  AGND  pwr
29  OUT5  out
30  AGND  pwr
31  OUT4  out
32  AGND  pwr
33  OUT3  out
34  V-  pwr
35  OUT2  out
36  D3  in
37  OUT1  out
38  D2  in
39  OUT0  out
40  V+  pwr

## Footprint DIL40 (pad centres in mm)
Dual In Line Package
drill 0.813 long: 1 -24.13,-7.62; 2 -21.59,-7.62; 3 -19.05,-7.62; 4 -16.51,-7.62; 5 -13.97,-7.62; 6 -11.43,-7.62; 7 -8.89,-7.62; 8 -6.35,-7.62; 9 -3.81,-7.62; 10 -1.27,-7.62; 11 1.27,-7.62; 12 3.81,-7.62; 13 6.35,-7.62; 14 8.89,-7.62; 15 11.43,-7.62; 16 13.97,-7.62; 17 16.51,-7.62; 18 19.05,-7.62; 19 21.59,-7.62; 20 24.13,-7.62; 21 24.13,7.62; 22 21.59,7.62; 23 19.05,7.62; 24 16.51,7.62; 25 13.97,7.62; 26 11.43,7.62; 27 8.89,7.62; 28 6.35,7.62; 29 3.81,7.62; 30 1.27,7.62; 31 -1.27,7.62; 32 -3.81,7.62; 33 -6.35,7.62; 34 -8.89,7.62; 35 -11.43,7.62; 36 -13.97,7.62; 37 -16.51,7.62; 38 -19.05,7.62; 39 -21.59,7.62; 40 -24.13,7.62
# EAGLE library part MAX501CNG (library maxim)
DIGITAL/ANALOG CONVERTER

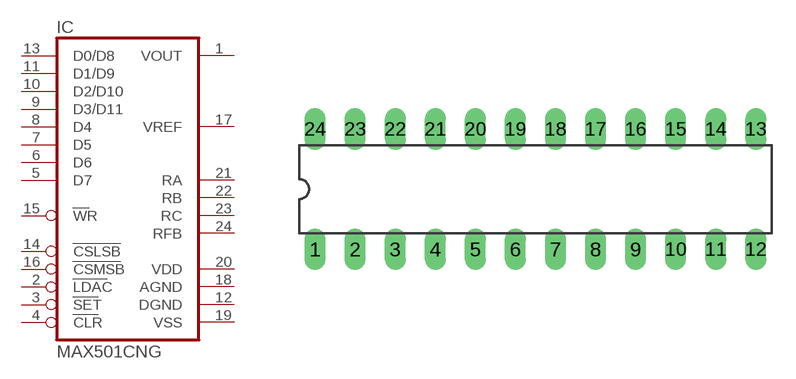
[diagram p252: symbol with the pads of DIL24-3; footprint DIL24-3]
Designator prefix IC

## MAX501CNG (OC_FARNELL: unknown; OC_NEWARK: unknown)  [DIL24-3]
1  VOUT  out
2  LDAC  in
3  SET  in
4  CLR  in
5  D7  in
6  D6  in
7  D5  in
8  D4  in
9  D3/D11  in
10  D2/D10  in
11  D1/D9  in
12  DGND  pwr
13  D0/D8  in
14  CSLSB  in
15  WR  in
16  CSMSB  in
17  VREF  in
18  AGND  pwr
19  VSS  pwr
20  VDD  pwr
21  RA  pas
22  RB  pas
23  RC  pas
24  RFB  pas

## Footprint DIL24-3 (pad centres in mm)
Dual In Line Package 0.3 inch
drill 0.813 long: 1 -13.97,-3.81; 2 -11.43,-3.81; 3 -8.89,-3.81; 4 -6.35,-3.81; 5 -3.81,-3.81; 6 -1.27,-3.81; 7 1.27,-3.81; 8 3.81,-3.81; 9 6.35,-3.81; 10 8.89,-3.81; 11 11.43,-3.81; 12 13.97,-3.81; 13 13.97,3.81; 14 11.43,3.81; 15 8.89,3.81; 16 6.35,3.81; 17 3.81,3.81; 18 1.27,3.81; 19 -1.27,3.81; 20 -3.81,3.81; 21 -6.35,3.81; 22 -8.89,3.81; 23 -11.43,3.81; 24 -13.97,3.81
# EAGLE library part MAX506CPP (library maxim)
DIGITAL/ANALOG CONVERTER

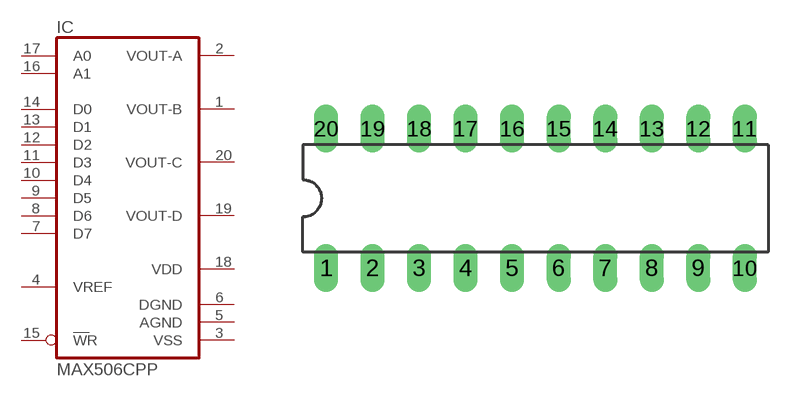
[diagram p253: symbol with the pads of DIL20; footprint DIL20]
Designator prefix IC

## MAX506CPP (OC_FARNELL: unknown; OC_NEWARK: unknown)  [DIL20]
1  VOUT-B  out
2  VOUT-A  out
3  VSS  pwr
4  VREF  in
5  AGND  pwr
6  DGND  pwr
7  D7  in
8  D6  in
9  D5  in
10  D4  in
11  D3  in
12  D2  in
13  D1  in
14  D0  in
15  WR  in
16  A1  in
17  A0  in
18  VDD  pwr
19  VOUT-D  out
20  VOUT-C  out

## Footprint DIL20 (pad centres in mm)
Dual In Line Package
drill 0.813 long: 1 -11.43,-3.81; 2 -8.89,-3.81; 3 -6.35,-3.81; 4 -3.81,-3.81; 5 -1.27,-3.81; 6 1.27,-3.81; 7 3.81,-3.81; 8 6.35,-3.81; 9 8.89,-3.81; 10 11.43,-3.81; 11 11.43,3.81; 12 8.89,3.81; 13 6.35,3.81; 14 3.81,3.81; 15 1.27,3.81; 16 -1.27,3.81; 17 -3.81,3.81; 18 -6.35,3.81; 19 -8.89,3.81; 20 -11.43,3.81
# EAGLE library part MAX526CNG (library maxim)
DIGITAL/ANALOG CONVERTER

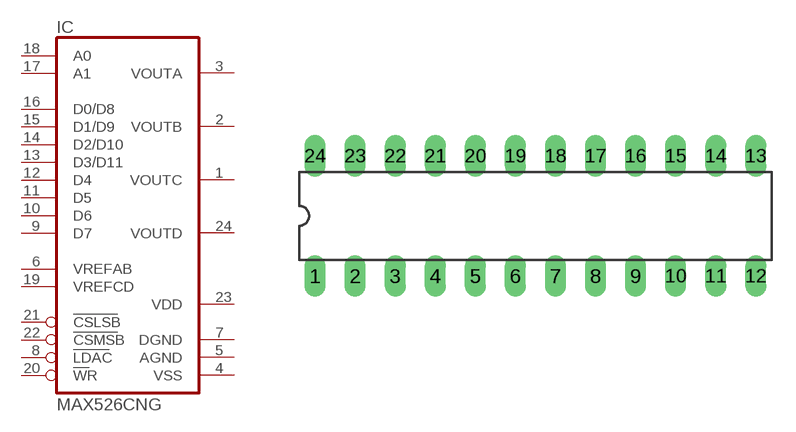
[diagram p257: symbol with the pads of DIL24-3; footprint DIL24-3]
Designator prefix IC

## MAX526CNG (OC_FARNELL: unknown; OC_NEWARK: unknown)  [DIL24-3]
1  VOUTC  out
2  VOUTB  out
3  VOUTA  out
4  VSS  pwr
5  AGND  pwr
6  VREFAB  in
7  DGND  pwr
8  LDAC  in
9  D7  in
10  D6  in
11  D5  in
12  D4  in
13  D3/D11  in
14  D2/D10  in
15  D1/D9  in
16  D0/D8  in
17  A1  in
18  A0  in
19  VREFCD  in
20  WR  in
21  CSLSB  in
22  CSMSB  in
23  VDD  pwr
24  VOUTD  out

## Footprint DIL24-3 (pad centres in mm)
Dual In Line Package 0.3 inch
drill 0.813 long: 1 -13.97,-3.81; 2 -11.43,-3.81; 3 -8.89,-3.81; 4 -6.35,-3.81; 5 -3.81,-3.81; 6 -1.27,-3.81; 7 1.27,-3.81; 8 3.81,-3.81; 9 6.35,-3.81; 10 8.89,-3.81; 11 11.43,-3.81; 12 13.97,-3.81; 13 13.97,3.81; 14 11.43,3.81; 15 8.89,3.81; 16 6.35,3.81; 17 3.81,3.81; 18 1.27,3.81; 19 -1.27,3.81; 20 -3.81,3.81; 21 -6.35,3.81; 22 -8.89,3.81; 23 -11.43,3.81; 24 -13.97,3.81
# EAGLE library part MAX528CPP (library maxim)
DIGITAL/ANALOG CONVERTER

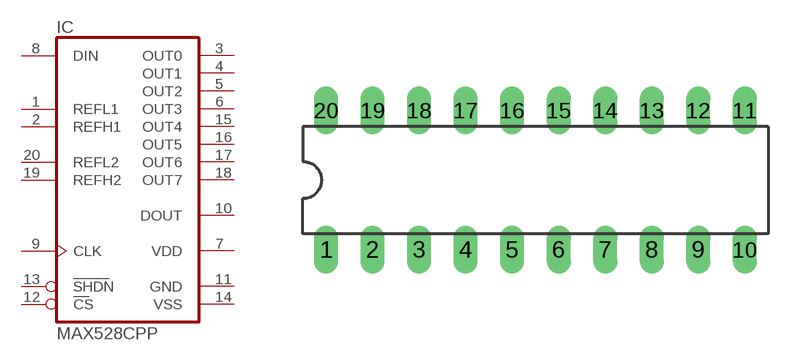
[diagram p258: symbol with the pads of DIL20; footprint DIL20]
Designator prefix IC

## MAX528CPP (MPN: MAX528CPP; OC_FARNELL: 1379992; OC_NEWARK: 78C2818)  [DIL20]
1  REFL1  in
2  REFH1  in
3  OUT0  out
4  OUT1  out
5  OUT2  out
6  OUT3  out
7  VDD  pwr
8  DIN  in
9  CLK  in
10  DOUT  out
11  GND  pwr
12  CS  in
13  SHDN  in
14  VSS  pwr
15  OUT4  out
16  OUT5  out
17  OUT6  out
18  OUT7  out
19  REFH2  in
20  REFL2  in

## Footprint DIL20 (pad centres in mm)
Dual In Line Package
drill 0.813 long: 1 -11.43,-3.81; 2 -8.89,-3.81; 3 -6.35,-3.81; 4 -3.81,-3.81; 5 -1.27,-3.81; 6 1.27,-3.81; 7 3.81,-3.81; 8 6.35,-3.81; 9 8.89,-3.81; 10 11.43,-3.81; 11 11.43,3.81; 12 8.89,3.81; 13 6.35,3.81; 14 3.81,3.81; 15 1.27,3.81; 16 -1.27,3.81; 17 -3.81,3.81; 18 -6.35,3.81; 19 -8.89,3.81; 20 -11.43,3.81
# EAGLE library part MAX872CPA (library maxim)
VOLTAGE REFERENCE

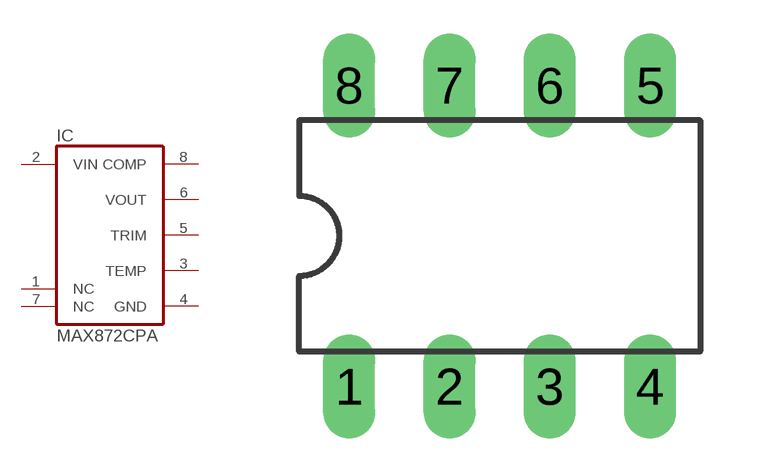
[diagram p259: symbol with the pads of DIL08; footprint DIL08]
Designator prefix IC

## MAX872CPA (OC_FARNELL: unknown; OC_NEWARK: unknown)  [DIL08]
1  NC  nc
2  VIN  in
3  TEMP  out
4  GND  pwr
5  TRIM  pas
6  VOUT  out
7  NC  nc
8  COMP  pas

## Footprint DIL08 (pad centres in mm)
Dual In Line Package
drill 0.813 long: 1 -3.81,-3.81; 2 -1.27,-3.81; 3 1.27,-3.81; 4 3.81,-3.81; 5 3.81,3.81; 6 1.27,3.81; 7 -1.27,3.81; 8 -3.81,3.81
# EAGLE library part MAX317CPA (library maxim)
ANALOG SWITCH

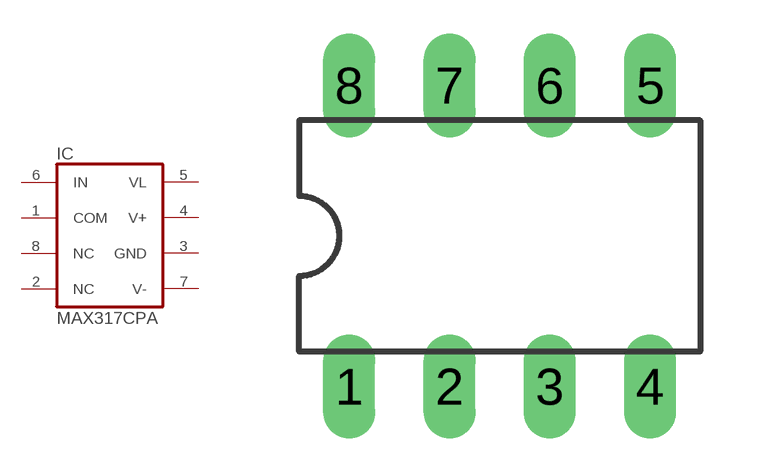
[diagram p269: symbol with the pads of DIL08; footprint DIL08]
Designator prefix IC

## MAX317CPA (MPN: MAX317CPA; OC_FARNELL: unknown; OC_NEWARK: 77C9073)  [DIL08]
1  COM  pas
2  NC  nc
3  GND  pwr
4  V+  pwr
5  VL  pwr
6  IN  in
7  V-  pwr
8  NC  pas

## Footprint DIL08 (pad centres in mm)
Dual In Line Package
drill 0.813 long: 1 -3.81,-3.81; 2 -1.27,-3.81; 3 1.27,-3.81; 4 3.81,-3.81; 5 3.81,3.81; 6 1.27,3.81; 7 -1.27,3.81; 8 -3.81,3.81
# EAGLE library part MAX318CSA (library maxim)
ANALOG SWITCH

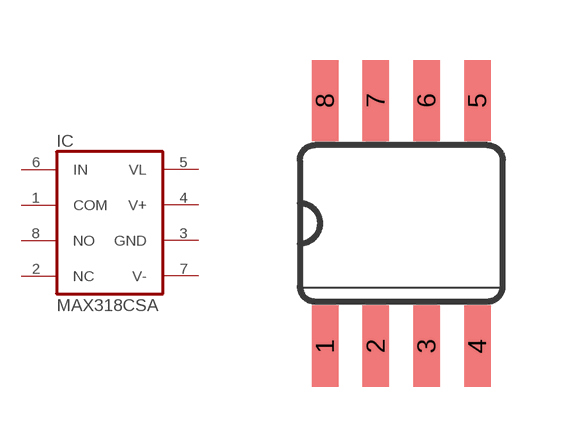
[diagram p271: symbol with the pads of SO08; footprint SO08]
Designator prefix IC

## MAX318CSA (MF: MAXIM; MPN: MAX318CSA+; OC_FARNELL: unknown; OC_NEWARK: 37K7911)  [SO08]
1  COM  pas
2  NC  nc
3  GND  pwr
4  V+  pwr
5  VL  pwr
6  IN  in
7  V-  pwr
8  NO  pas

## Footprint SO08 (pad centres in mm)
Small Outline Package SOIC 150 mil
smd 0.66 x 2.032: 1 -1.905,-3.073; 2 -0.635,-3.073; 3 0.635,-3.073; 4 1.905,-3.073; 5 1.905,3.073; 6 0.635,3.073; 7 -0.635,3.073; 8 -1.905,3.073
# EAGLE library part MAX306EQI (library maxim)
MULTIPLEXER

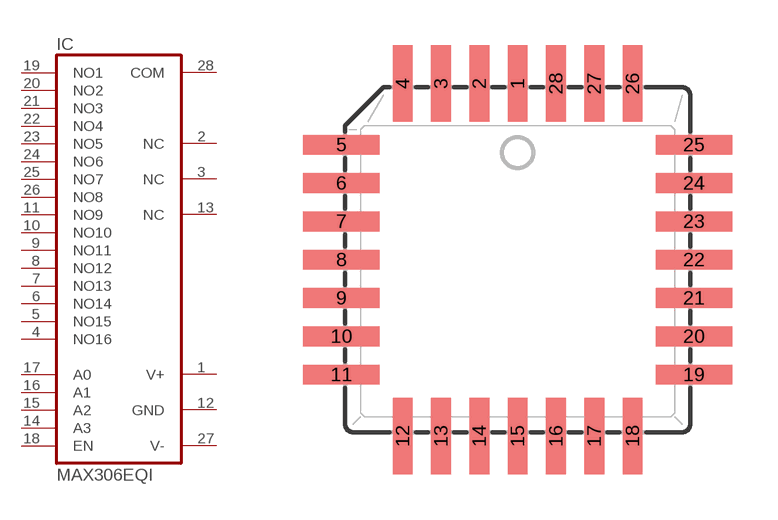
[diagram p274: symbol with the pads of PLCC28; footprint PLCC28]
Designator prefix IC

## MAX306EQI (MPN: MAX306EQI; OC_FARNELL: unknown; OC_NEWARK: 90C2558)  [PLCC28]
1  V+  pwr
2  NC  nc
3  NC  nc
4  NO16  pas
5  NO15  pas
6  NO14  pas
7  NO13  pas
8  NO12  pas
9  NO11  pas
10  NO10  pas
11  NO9  pas
12  GND  pwr
13  NC  nc
14  A3  in
15  A2  in
16  A1  in
17  A0  in
18  EN  in
19  NO1  pas
20  NO2  pas
21  NO3  pas
22  NO4  pas
23  NO5  pas
24  NO6  pas
25  NO7  pas
26  NO8  pas
27  V-  pwr
28  COM  pas

## Footprint PLCC28 (pad centres in mm)
PLASTIC LEADED CHIP CARRIER square
smd 0.66 x 2.54: 1 0,5.842; 2 -1.27,5.842; 3 -2.54,5.842; 4 -3.81,5.842; 12 -3.81,-5.842; 13 -2.54,-5.842; 14 -1.27,-5.842; 15 0,-5.842; 16 1.27,-5.842; 17 2.54,-5.842; 18 3.81,-5.842; 26 3.81,5.842; 27 2.54,5.842; 28 1.27,5.842
smd 2.54 x 0.66: 5 -5.842,3.81; 6 -5.842,2.54; 7 -5.842,1.27; 8 -5.842,0; 9 -5.842,-1.27; 10 -5.842,-2.54; 11 -5.842,-3.81; 19 5.842,-3.81; 20 5.842,-2.54; 21 5.842,-1.27; 22 5.842,0; 23 5.842,1.27; 24 5.842,2.54; 25 5.842,3.81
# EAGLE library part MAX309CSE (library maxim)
MULTIPLEXER

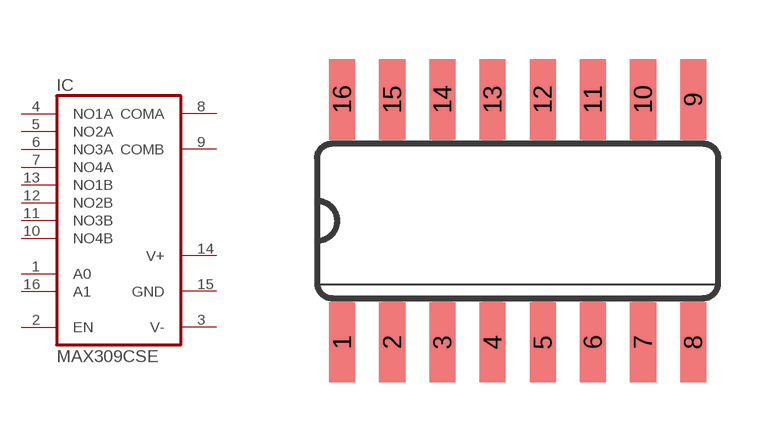
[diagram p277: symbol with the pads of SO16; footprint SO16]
Designator prefix IC

## MAX309CSE (MF: MAXIM; MPN: MAX309CSE+; OC_FARNELL: 1606630; OC_NEWARK: 67K4725)  [SO16]
1  A0  in
2  EN  in
3  V-  pwr
4  NO1A  pas
5  NO2A  pas
6  NO3A  pas
7  NO4A  pas
8  COMA  pas
9  COMB  pas
10  NO4B  pas
11  NO3B  pas
12  NO2B  pas
13  NO1B  pas
14  V+  pwr
15  GND  pwr
16  A1  in

## Footprint SO16 (pad centres in mm)
Small Outline Package .150 SIOC Source: http://www.maxim-ic.com/package_drawings/21-0041B.pdf
smd 0.66 x 2.032: 1 -4.445,-3.073; 2 -3.175,-3.073; 3 -1.905,-3.073; 4 -0.635,-3.073; 5 0.635,-3.073; 6 1.905,-3.073; 7 3.175,-3.073; 8 4.445,-3.073; 9 4.445,3.073; 10 3.175,3.073; 11 1.905,3.073; 12 0.635,3.073; 13 -0.635,3.073; 14 -1.905,3.073; 15 -3.175,3.073; 16 -4.445,3.073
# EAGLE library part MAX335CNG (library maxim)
ANALOG SWITCH

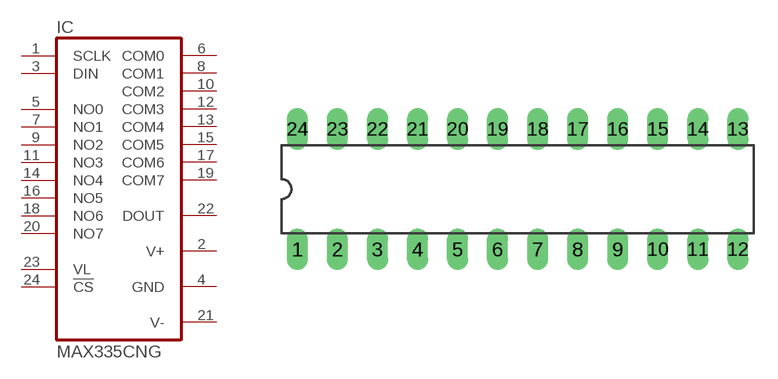
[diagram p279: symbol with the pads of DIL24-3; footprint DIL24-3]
Designator prefix IC

## MAX335CNG (MF: MAXIM; MPN: MAX335CNG; OC_FARNELL: 1188014; OC_NEWARK: 34C3880)  [DIL24-3]
1  SCLK  in
2  V+  pwr
3  DIN  in
4  GND  pwr
5  NO0  pas
6  COM0  pas
7  NO1  pas
8  COM1  pas
9  NO2  pas
10  COM2  pas
11  NO3  pas
12  COM3  pas
13  COM4  pas
14  NO4  pas
15  COM5  pas
16  NO5  pas
17  COM6  pas
18  NO6  pas
19  COM7  pas
20  NO7  pas
21  V-  pwr
22  DOUT  out
23  VL  in
24  !CS  in

## Footprint DIL24-3 (pad centres in mm)
Dual In Line Package 0.3 inch
drill 0.813 long: 1 -13.97,-3.81; 2 -11.43,-3.81; 3 -8.89,-3.81; 4 -6.35,-3.81; 5 -3.81,-3.81; 6 -1.27,-3.81; 7 1.27,-3.81; 8 3.81,-3.81; 9 6.35,-3.81; 10 8.89,-3.81; 11 11.43,-3.81; 12 13.97,-3.81; 13 13.97,3.81; 14 11.43,3.81; 15 8.89,3.81; 16 6.35,3.81; 17 3.81,3.81; 18 1.27,3.81; 19 -1.27,3.81; 20 -3.81,3.81; 21 -6.35,3.81; 22 -8.89,3.81; 23 -11.43,3.81; 24 -13.97,3.81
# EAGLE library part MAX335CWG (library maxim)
ANALOG SWITCH

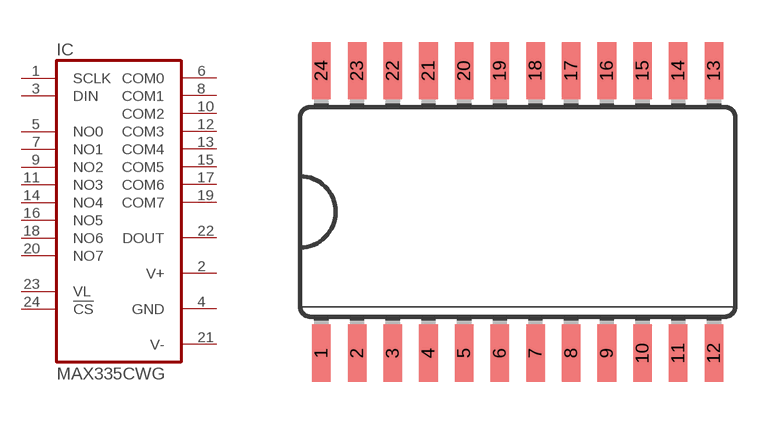
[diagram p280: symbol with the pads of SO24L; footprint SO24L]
Designator prefix IC

## MAX335CWG (MF: MAXIM; MPN: MAX335CWG; OC_FARNELL: 9725555; OC_NEWARK: 34C3881)  [SO24L]
1  SCLK  in
2  V+  pwr
3  DIN  in
4  GND  pwr
5  NO0  pas
6  COM0  pas
7  NO1  pas
8  COM1  pas
9  NO2  pas
10  COM2  pas
11  NO3  pas
12  COM3  pas
13  COM4  pas
14  NO4  pas
15  COM5  pas
16  NO5  pas
17  COM6  pas
18  NO6  pas
19  COM7  pas
20  NO7  pas
21  V-  pwr
22  DOUT  out
23  VL  in
24  !CS  in

## Footprint SO24L (pad centres in mm)
Small Outline Package
smd 0.66 x 2.032: 1 -6.985,-5.029; 2 -5.715,-5.029; 3 -4.445,-5.029; 4 -3.175,-5.029; 5 -1.905,-5.029; 6 -0.635,-5.029; 7 0.635,-5.029; 8 1.905,-5.029; 9 3.175,-5.029; 10 4.445,-5.029; 11 5.715,-5.029; 12 6.985,-5.029; 13 6.985,5.029; 14 5.715,5.029; 15 4.445,5.029; 16 3.175,5.029; 17 1.905,5.029; 18 0.635,5.029; 19 -0.635,5.029; 20 -1.905,5.029; 21 -3.175,5.029; 22 -4.445,5.029; 23 -5.715,5.029; 24 -6.985,5.029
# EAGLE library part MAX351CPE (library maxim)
ANALOG SWITCH

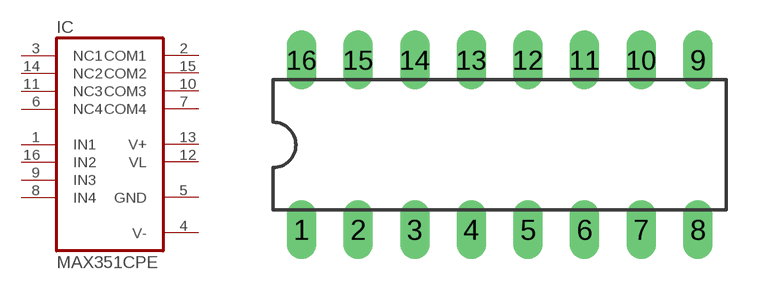
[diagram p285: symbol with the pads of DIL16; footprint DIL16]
Designator prefix IC

## MAX351CPE (MPN: MAX351CPE+; OC_FARNELL: unknown; OC_NEWARK: 73K8561)  [DIL16]
1  IN1  in
2  COM1  pas
3  NC1  pas
4  V-  pwr
5  GND  pwr
6  NC4  pas
7  COM4  pas
8  IN4  in
9  IN3  in
10  COM3  pas
11  NC3  pas
12  VL  pwr
13  V+  pwr
14  NC2  pas
15  COM2  pas
16  IN2  in

## Footprint DIL16 (pad centres in mm)
Dual In Line Package
drill 0.813 long: 1 -8.89,-3.81; 2 -6.35,-3.81; 3 -3.81,-3.81; 4 -1.27,-3.81; 5 1.27,-3.81; 6 3.81,-3.81; 7 6.35,-3.81; 8 8.89,-3.81; 9 8.89,3.81; 10 6.35,3.81; 11 3.81,3.81; 12 1.27,3.81; 13 -1.27,3.81; 14 -3.81,3.81; 15 -6.35,3.81; 16 -8.89,3.81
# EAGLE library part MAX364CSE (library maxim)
ANALOG SWITCH

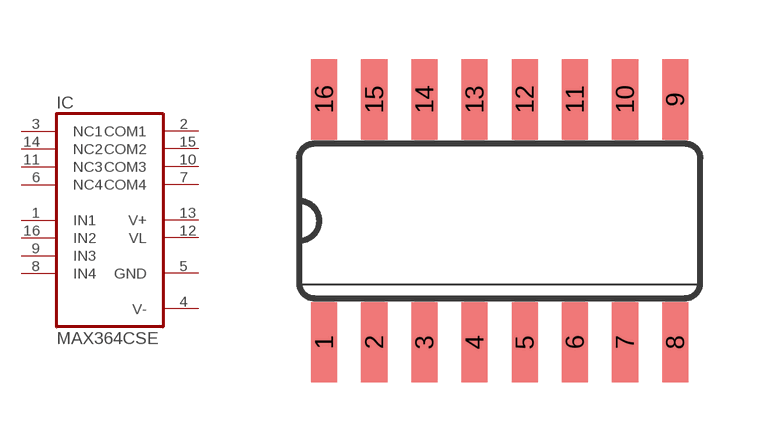
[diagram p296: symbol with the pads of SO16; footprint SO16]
Designator prefix IC

## MAX364CSE (MF: MAXIM; MPN: MAX364CSE+; OC_FARNELL: unknown; OC_NEWARK: 28K3314)  [SO16]
1  IN1  in
2  COM1  pas
3  NC1  pas
4  V-  pwr
5  GND  pwr
6  NC4  pas
7  COM4  pas
8  IN4  in
9  IN3  in
10  COM3  pas
11  NC3  pas
12  VL  pwr
13  V+  pwr
14  NC2  pas
15  COM2  pas
16  IN2  in

## Footprint SO16 (pad centres in mm)
Small Outline Package .150 SIOC Source: http://www.maxim-ic.com/package_drawings/21-0041B.pdf
smd 0.66 x 2.032: 1 -4.445,-3.073; 2 -3.175,-3.073; 3 -1.905,-3.073; 4 -0.635,-3.073; 5 0.635,-3.073; 6 1.905,-3.073; 7 3.175,-3.073; 8 4.445,-3.073; 9 4.445,3.073; 10 3.175,3.073; 11 1.905,3.073; 12 0.635,3.073; 13 -0.635,3.073; 14 -1.905,3.073; 15 -3.175,3.073; 16 -4.445,3.073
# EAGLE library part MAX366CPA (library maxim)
Signal-line CIRCUIT PROTECTOR

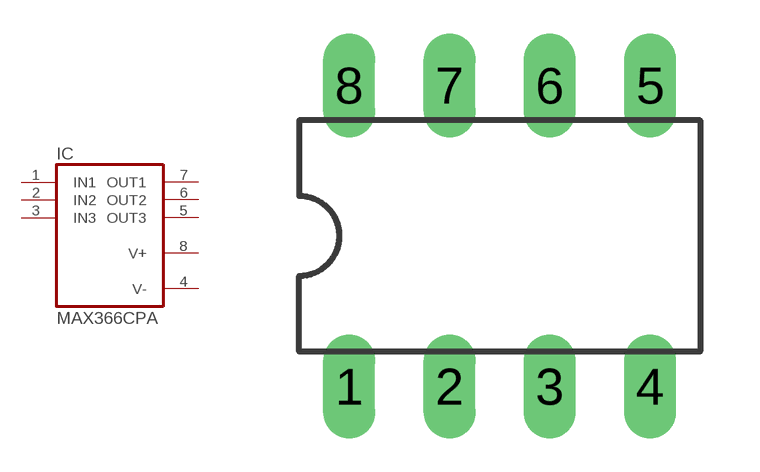
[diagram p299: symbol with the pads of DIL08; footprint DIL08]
Designator prefix IC

## MAX366CPA (MPN: MAX366CPA+; OC_FARNELL: unknown; OC_NEWARK: 99K3305)  [DIL08]
1  IN1  pas
2  IN2  pas
3  IN3  pas
4  V-  pwr
5  OUT3  pas
6  OUT2  pas
7  OUT1  pas
8  V+  pwr

## Footprint DIL08 (pad centres in mm)
Dual In Line Package
drill 0.813 long: 1 -3.81,-3.81; 2 -1.27,-3.81; 3 1.27,-3.81; 4 3.81,-3.81; 5 3.81,3.81; 6 1.27,3.81; 7 -1.27,3.81; 8 -3.81,3.81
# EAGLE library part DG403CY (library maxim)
ANALOG SWITCH

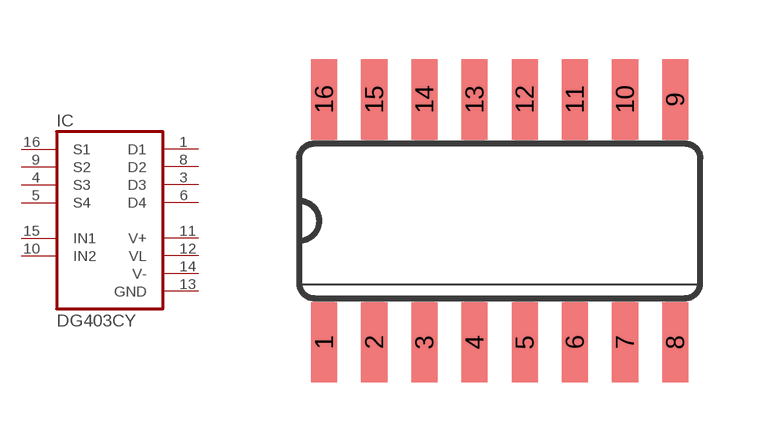
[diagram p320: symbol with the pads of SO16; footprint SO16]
Designator prefix IC

## DG403CY (MF: MAXIM; MPN: DG403CY; OC_FARNELL: 1379790; OC_NEWARK: 77C6446)  [SO16]
1  D1  pas
3  D3  pas
4  S3  pas
5  S4  pas
6  D4  pas
8  D2  pas
9  S2  pas
10  IN2  in
11  V+  pwr
12  VL  pwr
13  GND  pwr
14  V-  pwr
15  IN1  in
16  S1  pas

## Footprint SO16 (pad centres in mm)
Small Outline Package .150 SIOC Source: http://www.maxim-ic.com/package_drawings/21-0041B.pdf
smd 0.66 x 2.032: 1 -4.445,-3.073; 2 -3.175,-3.073; 3 -1.905,-3.073; 4 -0.635,-3.073; 5 0.635,-3.073; 6 1.905,-3.073; 7 3.175,-3.073; 8 4.445,-3.073; 9 4.445,3.073; 10 3.175,3.073; 11 1.905,3.073; 12 0.635,3.073; 13 -0.635,3.073; 14 -1.905,3.073; 15 -3.175,3.073; 16 -4.445,3.073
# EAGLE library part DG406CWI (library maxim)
ANALOG MULTIPLEXER

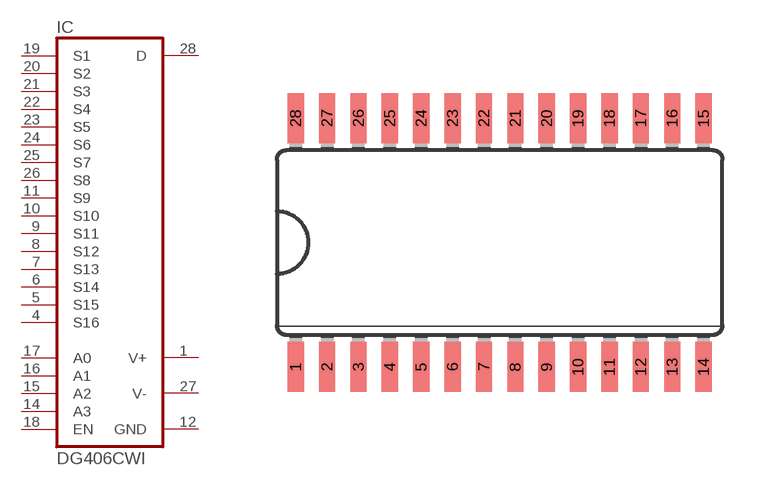
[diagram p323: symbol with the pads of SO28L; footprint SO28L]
Designator prefix IC

## DG406CWI (MF: MAXIM; MPN: DG406CWI; OC_FARNELL: unknown; OC_NEWARK: 77C6458)  [SO28L]
1  V+  pwr
4  S16  pas
5  S15  pas
6  S14  pas
7  S13  pas
8  S12  pas
9  S11  pas
10  S10  pas
11  S9  pas
12  GND  pwr
14  A3  in
15  A2  in
16  A1  in
17  A0  in
18  EN  in
19  S1  pas
20  S2  pas
21  S3  pas
22  S4  pas
23  S5  pas
24  S6  pas
25  S7  pas
26  S8  pas
27  V-  pwr
28  D  pas

## Footprint SO28L (pad centres in mm)
Small Outline Package MAX3221-MAX3243.pdf; SO28W
smd 0.66 x 2.032: 1 -8.255,-5.029; 2 -6.985,-5.029; 3 -5.715,-5.029; 4 -4.445,-5.029; 5 -3.175,-5.029; 6 -1.905,-5.029; 7 -0.635,-5.029; 8 0.635,-5.029; 9 1.905,-5.029; 10 3.175,-5.029; 11 4.445,-5.029; 12 5.715,-5.029; 13 6.985,-5.029; 14 8.255,-5.029; 15 8.255,5.029; 16 6.985,5.029; 17 5.715,5.029; 18 4.445,5.029; 19 3.175,5.029; 20 1.905,5.029; 21 0.635,5.029; 22 -0.635,5.029; 23 -1.905,5.029; 24 -3.175,5.029; 25 -4.445,5.029; 26 -5.715,5.029; 27 -6.985,5.029; 28 -8.255,5.029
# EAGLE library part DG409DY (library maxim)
ANALOG MULTIPLEXER

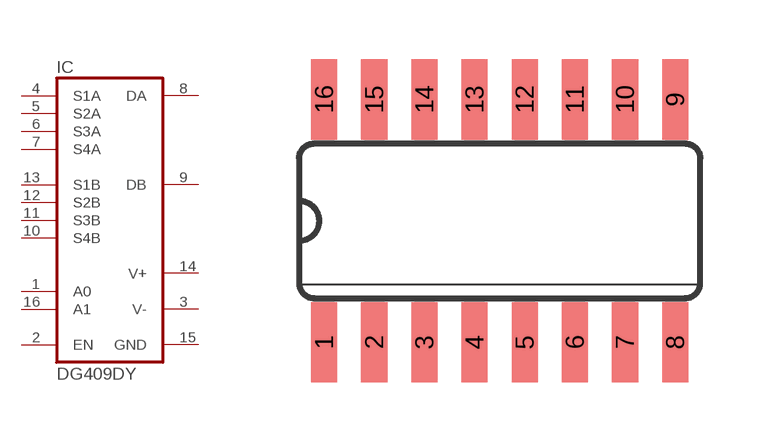
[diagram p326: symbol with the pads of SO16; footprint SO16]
Designator prefix IC

## DG409DY (MF: MAXIM; MPN: DG409DY; OC_FARNELL: 9663835; OC_NEWARK: 90C1278)  [SO16]
1  A0  in
2  EN  in
3  V-  pwr
4  S1A  pas
5  S2A  pas
6  S3A  pas
7  S4A  pas
8  DA  pas
9  DB  pas
10  S4B  pas
11  S3B  pas
12  S2B  pas
13  S1B  pas
14  V+  pwr
15  GND  pwr
16  A1  in

## Footprint SO16 (pad centres in mm)
Small Outline Package .150 SIOC Source: http://www.maxim-ic.com/package_drawings/21-0041B.pdf
smd 0.66 x 2.032: 1 -4.445,-3.073; 2 -3.175,-3.073; 3 -1.905,-3.073; 4 -0.635,-3.073; 5 0.635,-3.073; 6 1.905,-3.073; 7 3.175,-3.073; 8 4.445,-3.073; 9 4.445,3.073; 10 3.175,3.073; 11 1.905,3.073; 12 0.635,3.073; 13 -0.635,3.073; 14 -1.905,3.073; 15 -3.175,3.073; 16 -4.445,3.073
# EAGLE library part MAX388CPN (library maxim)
MULTIPLEXER

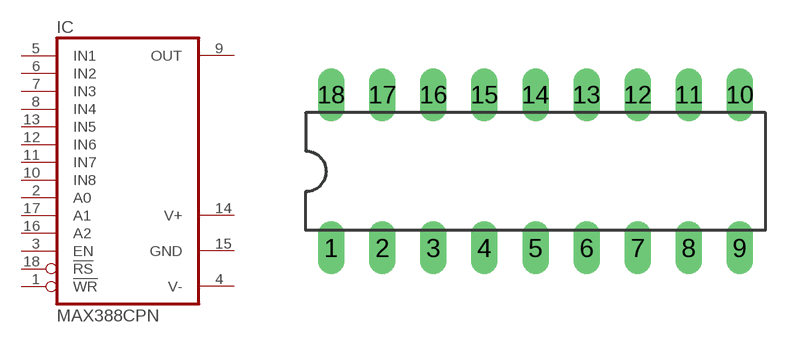
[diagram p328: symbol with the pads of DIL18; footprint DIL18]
Designator prefix IC

## MAX388CPN (MPN: MAX388CPN+; OC_FARNELL: unknown; OC_NEWARK: 73K8562)  [DIL18]
1  !WR  in
2  A0  in
3  EN  in
4  V-  pwr
5  IN1  pas
6  IN2  pas
7  IN3  pas
8  IN4  pas
9  OUT  pas
10  IN8  pas
11  IN7  pas
12  IN6  pas
13  IN5  pas
14  V+  pwr
15  GND  pwr
16  A2  in
17  A1  in
18  !RS  in

## Footprint DIL18 (pad centres in mm)
Dual In Line Package
drill 0.813 long: 1 -10.16,-3.81; 2 -7.62,-3.81; 3 -5.08,-3.81; 4 -2.54,-3.81; 5 0,-3.81; 6 2.54,-3.81; 7 5.08,-3.81; 8 7.62,-3.81; 9 10.16,-3.81; 10 10.16,3.81; 11 7.62,3.81; 12 5.08,3.81; 13 2.54,3.81; 14 0,3.81; 15 -2.54,3.81; 16 -5.08,3.81; 17 -7.62,3.81; 18 -10.16,3.81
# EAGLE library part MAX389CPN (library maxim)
MULTIPLEXER

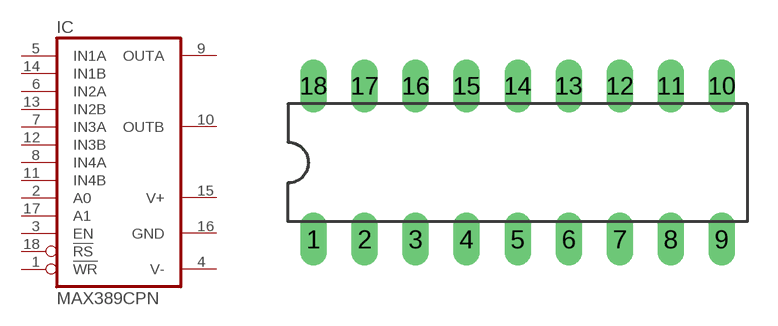
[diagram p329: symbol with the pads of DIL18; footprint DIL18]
Designator prefix IC

## MAX389CPN (MPN: MAX389CPN+; OC_FARNELL: unknown; OC_NEWARK: 13M2221)  [DIL18]
1  !WR  in
2  A0  in
3  EN  in
4  V-  pwr
5  IN1A  pas
6  IN2A  pas
7  IN3A  pas
8  IN4A  pas
9  OUTA  pas
10  OUTB  pas
11  IN4B  pas
12  IN3B  pas
13  IN2B  pas
14  IN1B  pas
15  V+  pwr
16  GND  pwr
17  A1  in
18  !RS  in

## Footprint DIL18 (pad centres in mm)
Dual In Line Package
drill 0.813 long: 1 -10.16,-3.81; 2 -7.62,-3.81; 3 -5.08,-3.81; 4 -2.54,-3.81; 5 0,-3.81; 6 2.54,-3.81; 7 5.08,-3.81; 8 7.62,-3.81; 9 10.16,-3.81; 10 10.16,3.81; 11 7.62,3.81; 12 5.08,3.81; 13 2.54,3.81; 14 0,3.81; 15 -2.54,3.81; 16 -5.08,3.81; 17 -7.62,3.81; 18 -10.16,3.81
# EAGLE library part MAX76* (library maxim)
DC-DC CONVERTER

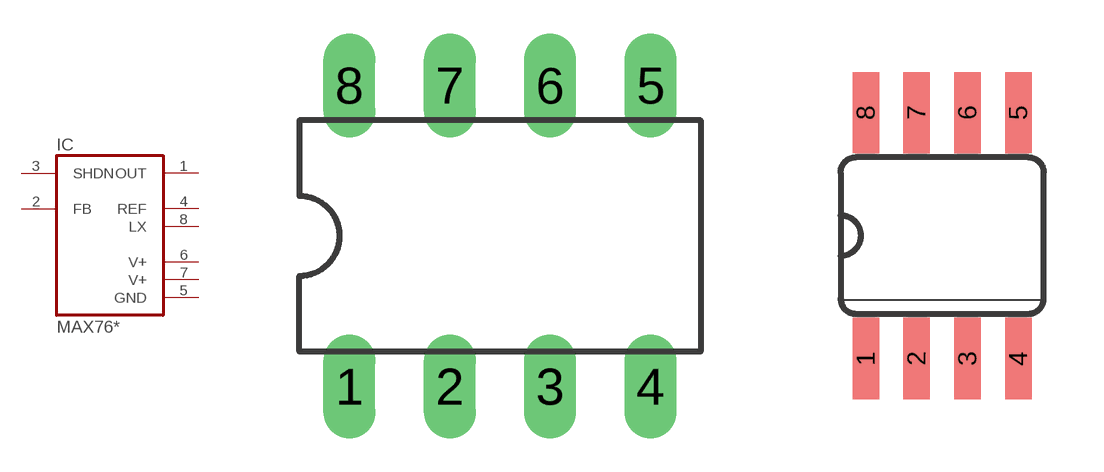
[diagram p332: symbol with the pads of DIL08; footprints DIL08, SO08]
Designator prefix IC

## MAX764CPA (MPN: MAX764CPA+; OC_FARNELL: 1422353; OC_NEWARK: 89K6221), MAX764EPA (MPN: MAX764EPA+; OC_FARNELL: unknown; OC_NEWARK: 61K0675), MAX765CPA (MPN: MAX765CPA+; OC_FARNELL: 1256394; OC_NEWARK: 06M0058), MAX765EPA (MPN: MAX765EPA+; OC_FARNELL: unknown; OC_NEWARK: 28M3073), MAX766CPA (MPN: MAX766CPA+; OC_FARNELL: unknown; OC_NEWARK: 89K6227), MAX766EPA (MPN: MAX766EPA+; OC_FARNELL: unknown; OC_NEWARK: 06M0059)  [DIL08]
1  OUT  out
2  FB  in
3  SHDN  in
4  REF  out
5  GND  pwr
6  V+  pwr
7  V+  pwr
8  LX  out

## MAX764CSA (MF: MAXIM; MPN: MAX764CSA+; OC_FARNELL: 9725032; OC_NEWARK: 23K6509), MAX764ESA (MF: MAXIM; MPN: MAX764ESA+; OC_FARNELL: 1422354; OC_NEWARK: 59J6527), MAX765CSA (MF: MAXIM; MPN: MAX765CSA+; OC_FARNELL: 9725059; OC_NEWARK: 33K2255), MAX765ESA (MF: MAXIM; MPN: MAX765ESA+; OC_FARNELL: 1673223; OC_NEWARK: 33K2256), MAX766CSA (MF: MAXIM; MPN: MAX766CSA+; OC_FARNELL: 1673224; OC_NEWARK: 59J6529), MAX766ESA (MF: MAXIM; MPN: MAX766ESA+; OC_FARNELL: 1422355; OC_NEWARK: 59J6531)  [SO08]
Pads as for DIL08

## Footprint DIL08 (pad centres in mm)
Dual In Line Package
drill 0.813 long: 1 -3.81,-3.81; 2 -1.27,-3.81; 3 1.27,-3.81; 4 3.81,-3.81; 5 3.81,3.81; 6 1.27,3.81; 7 -1.27,3.81; 8 -3.81,3.81

## Footprint SO08 (pad centres in mm)
Small Outline Package SOIC 150 mil
smd 0.66 x 2.032: 1 -1.905,-3.073; 2 -0.635,-3.073; 3 0.635,-3.073; 4 1.905,-3.073; 5 1.905,3.073; 6 0.635,3.073; 7 -0.635,3.073; 8 -1.905,3.073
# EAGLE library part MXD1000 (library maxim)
DELAY LINE

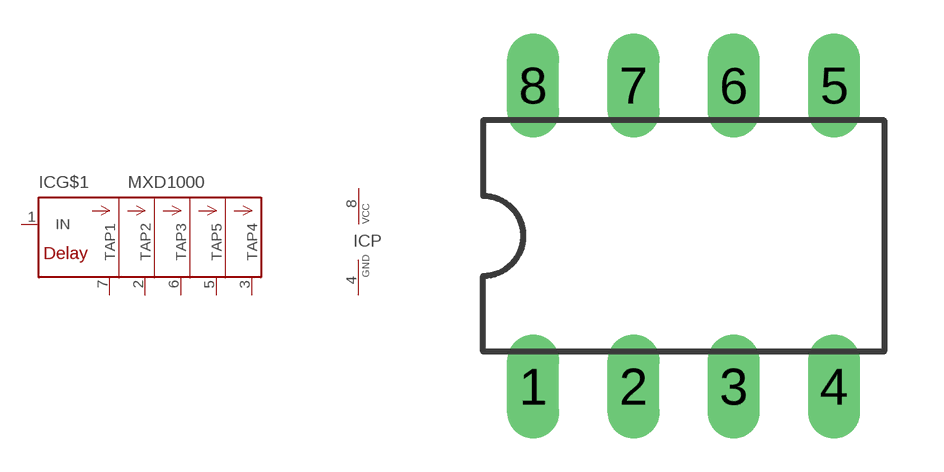
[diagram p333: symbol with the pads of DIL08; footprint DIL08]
Designator prefix IC; gates G$1=MXD1000 P=VCC-GND

## MXD1000 (OC_FARNELL: unknown; OC_NEWARK: unknown)  [DIL08]
1  G$1:IN  in
2  G$1:TAP2  out
3  G$1:TAP4  out
4  P:GND  pwr
5  G$1:TAP5  out
6  G$1:TAP3  out
7  G$1:TAP1  out
8  P:VCC  pwr

## Footprint DIL08 (pad centres in mm)
Dual In Line Package
drill 0.813 long: 1 -3.81,-3.81; 2 -1.27,-3.81; 3 1.27,-3.81; 4 3.81,-3.81; 5 3.81,3.81; 6 1.27,3.81; 7 -1.27,3.81; 8 -3.81,3.81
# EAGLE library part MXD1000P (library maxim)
DELAY LINE

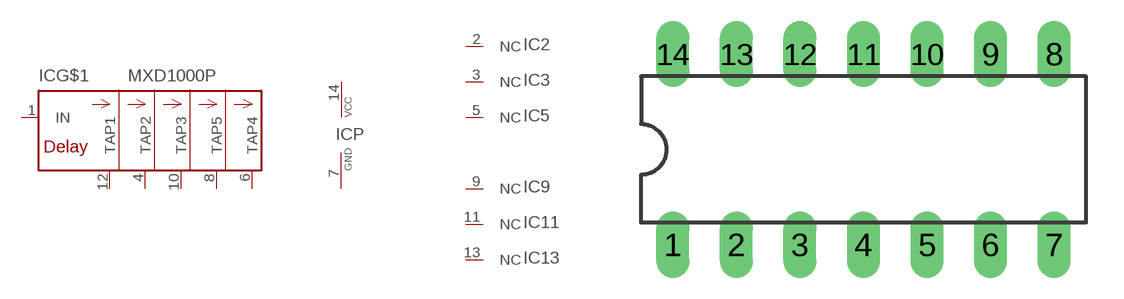
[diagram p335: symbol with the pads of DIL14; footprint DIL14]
Designator prefix IC; gates G$1=MXD1000 P=VCC-GND 2=NC 3=NC 5=NC 9=NC 11=NC 13=NC

## MXD1000P (OC_FARNELL: unknown; OC_NEWARK: unknown)  [DIL14]
1  G$1:IN  in
2  2:NC  nc
3  3:NC  nc
4  G$1:TAP2  out
5  5:NC  nc
6  G$1:TAP4  out
7  P:GND  pwr
8  G$1:TAP5  out
9  9:NC  nc
10  G$1:TAP3  out
11  11:NC  nc
12  G$1:TAP1  out
13  13:NC  nc
14  P:VCC  pwr

## Footprint DIL14 (pad centres in mm)
Dual In Line Package
drill 0.813 long: 1 -7.62,-3.81; 2 -5.08,-3.81; 3 -2.54,-3.81; 4 0,-3.81; 5 2.54,-3.81; 6 5.08,-3.81; 7 7.62,-3.81; 8 7.62,3.81; 9 5.08,3.81; 10 2.54,3.81; 11 0,3.81; 12 -2.54,3.81; 13 -5.08,3.81; 14 -7.62,3.81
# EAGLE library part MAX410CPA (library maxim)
OP AMP

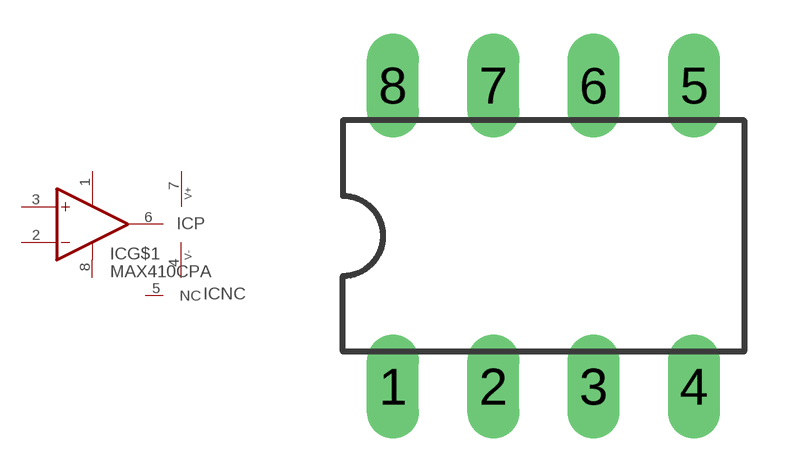
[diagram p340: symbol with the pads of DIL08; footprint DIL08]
Designator prefix IC; gates P=PWR+- NC=NC G$1=OPOFF

## MAX410CPA (MPN: MAX410CPA; OC_FARNELL: unknown; OC_NEWARK: 34C3886)  [DIL08]
1  G$1:OFF1  pas
2  G$1:-IN  in
3  G$1:+IN  in
4  P:V-  pwr
5  NC:NC  nc
6  G$1:OUT  out
7  P:V+  pwr
8  G$1:OFF2  pas

## Footprint DIL08 (pad centres in mm)
Dual In Line Package
drill 0.813 long: 1 -3.81,-3.81; 2 -1.27,-3.81; 3 1.27,-3.81; 4 3.81,-3.81; 5 3.81,3.81; 6 1.27,3.81; 7 -1.27,3.81; 8 -3.81,3.81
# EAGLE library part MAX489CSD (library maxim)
RS485 TRANSEIVER

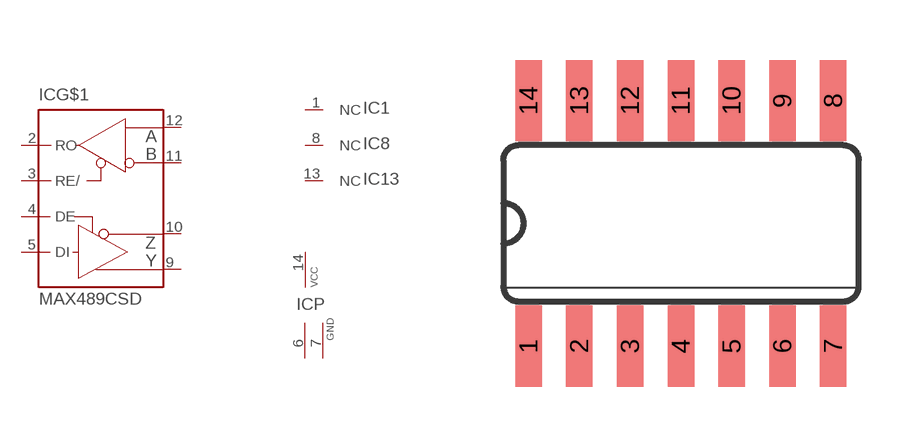
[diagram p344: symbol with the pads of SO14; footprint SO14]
Designator prefix IC; gates G$1=MAX489 1=NC 8=NC 13=NC P=PWR2GND

## MAX489CSD (MF: MAXIM; MPN: MAX489CSD; OC_FARNELL: 9724559; OC_NEWARK: 34C3923)  [SO14]
1  1:NC  nc
2  G$1:RO  out
3  G$1:RE/  in
4  G$1:DE  in
5  G$1:DI  in
6  P:GND  pwr
7  P:GND  pwr
8  8:NC  nc
9  G$1:Y  pas
10  G$1:Z  pas
11  G$1:B  pas
12  G$1:A  pas
13  13:NC  nc
14  P:VCC  pwr

## Footprint SO14 (pad centres in mm)
Small Outline Package
smd 0.66 x 2.032: 1 -3.81,-3.073; 2 -2.54,-3.073; 3 -1.27,-3.073; 4 0,-3.073; 5 1.27,-3.073; 6 2.54,-3.073; 7 3.81,-3.073; 8 3.81,3.073; 9 2.54,3.073; 10 1.27,3.073; 11 0,3.073; 12 -1.27,3.073; 13 -2.54,3.073; 14 -3.81,3.073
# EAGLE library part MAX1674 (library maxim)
DC/DC CONVERTER

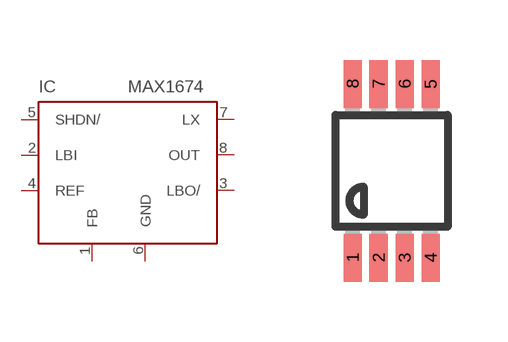
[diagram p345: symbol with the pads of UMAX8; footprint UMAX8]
Designator prefix IC

## MAX1674 (MF: MAXIM; MPN: MAX1674EUA+; OC_FARNELL: 1379864; OC_NEWARK: 23K5719)  [UMAX8]
1  FB  in
2  LBI  in
3  LBO/  out
4  REF  pas
5  SHDN/  in
6  GND  pwr
7  LX  pas
8  OUT  out

## Footprint UMAX8 (pad centres in mm)
micro MAX Package
smd 0.45 x 1.2: 1 -0.975,-2.175; 2 -0.325,-2.175; 3 0.325,-2.175; 4 0.975,-2.175; 5 0.975,2.175; 6 0.325,2.175; 7 -0.325,2.175; 8 -0.975,2.175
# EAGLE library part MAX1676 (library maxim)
DC/DC CONVERTER

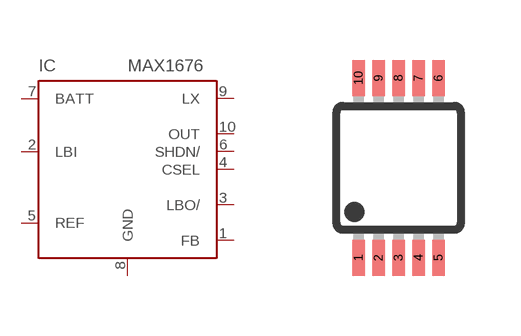
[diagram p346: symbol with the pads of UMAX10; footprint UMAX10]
Designator prefix IC

## MAX1676 (MF: MAXIM; MPN: MAX1676EUB+; OC_FARNELL: 9724079; OC_NEWARK: 59J2827)  [UMAX10]
1  FB  in
2  LBI  in
3  LBO/  out
4  CSEL  in
5  REF  pas
6  SHDN/  in
7  BATT  in
8  GND  pwr
9  LX  pas
10  OUT  out

## Footprint UMAX10 (pad centres in mm)
micro MAX Package
smd 0.32 x 0.9: 1 -1,-2.25; 2 -0.5,-2.25; 3 0,-2.25; 4 0.5,-2.25; 5 1,-2.25; 6 1,2.25; 7 0.5,2.25; 8 0,2.25; 9 -0.5,2.25; 10 -1,2.25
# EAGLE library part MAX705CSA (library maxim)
WATCHDOG

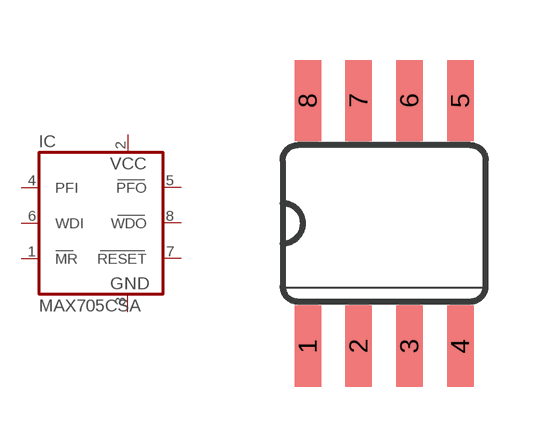
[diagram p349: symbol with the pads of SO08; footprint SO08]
Designator prefix IC

## MAX705CSA (MF: MAXIM; MPN: MAX705CSA; OC_FARNELL: 9726012; OC_NEWARK: 34C4003)  [SO08]
1  MR  in
2  VCC  pwr
3  GND  pwr
4  PFI  in
5  PFO  out
6  WDI  in
7  RESET  out
8  WDO  out

## Footprint SO08 (pad centres in mm)
Small Outline Package SOIC 150 mil
smd 0.66 x 2.032: 1 -1.905,-3.073; 2 -0.635,-3.073; 3 0.635,-3.073; 4 1.905,-3.073; 5 1.905,3.073; 6 0.635,3.073; 7 -0.635,3.073; 8 -1.905,3.073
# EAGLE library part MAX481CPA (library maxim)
RS485 TRANSEIVER

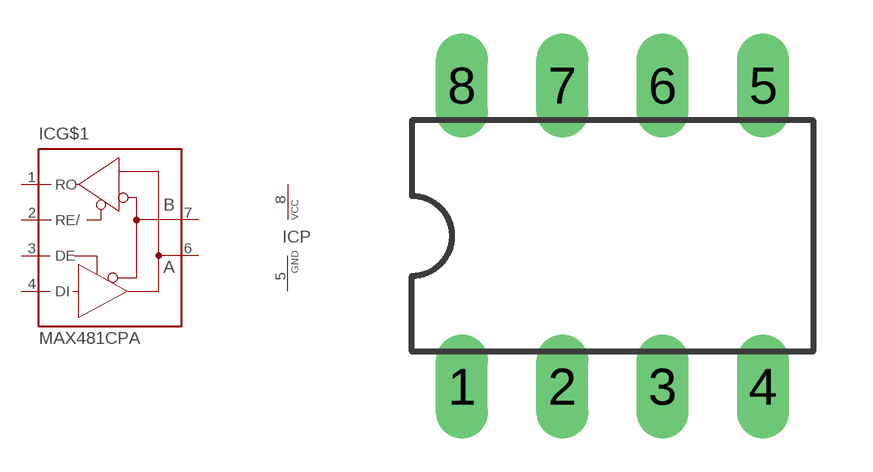
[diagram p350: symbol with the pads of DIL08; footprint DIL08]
Designator prefix IC; gates G$1=MAX481 P=VCC-GND

## MAX481CPA (MPN: MAX481CPA+; OC_FARNELL: unknown; OC_NEWARK: 99K3445)  [DIL08]
1  G$1:RO  out
2  G$1:RE/  in
3  G$1:DE  in
4  G$1:DI  in
5  P:GND  pwr
6  G$1:A  pas
7  G$1:B  pas
8  P:VCC  pwr

## Footprint DIL08 (pad centres in mm)
Dual In Line Package
drill 0.813 long: 1 -3.81,-3.81; 2 -1.27,-3.81; 3 1.27,-3.81; 4 3.81,-3.81; 5 3.81,3.81; 6 1.27,3.81; 7 -1.27,3.81; 8 -3.81,3.81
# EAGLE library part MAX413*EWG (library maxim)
1-Input/4-Output Video Distribution Amplifiers Source: http://pdfserv.maxim-ic.com/en/ds/MAX4137-MAX4138.pdf

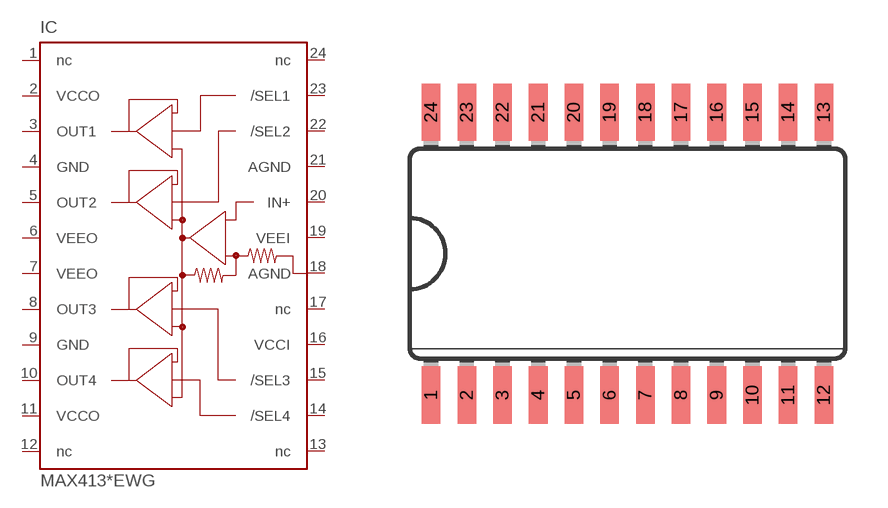
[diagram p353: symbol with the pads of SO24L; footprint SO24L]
Designator prefix IC

## MAX4137EWG (OC_FARNELL: unknown; OC_NEWARK: unknown), MAX4138EWG (OC_FARNELL: unknown; OC_NEWARK: unknown)  [SO24L]
1  NC1  nc
2  VCCO  pwr
3  OUT1  out
4  GND  pwr
5  OUT2  out
6  VEEO  pwr
7  VEEO  pwr
8  OUT3  out
9  GND  pwr
10  OUT4  out
11  VCCO  pwr
12  NC12  nc
13  NC13  nc
14  /SEL4  in
15  /SEL3  in
16  VCCI  pwr
17  NC17  nc
18  AGND  pwr
19  VEEI  pwr
20  IN+  in
21  AGND  pwr
22  /SEL2  in
23  /SEL1  in
24  NC24  nc

## Footprint SO24L (pad centres in mm)
Small Outline Package
smd 0.66 x 2.032: 1 -6.985,-5.029; 2 -5.715,-5.029; 3 -4.445,-5.029; 4 -3.175,-5.029; 5 -1.905,-5.029; 6 -0.635,-5.029; 7 0.635,-5.029; 8 1.905,-5.029; 9 3.175,-5.029; 10 4.445,-5.029; 11 5.715,-5.029; 12 6.985,-5.029; 13 6.985,5.029; 14 5.715,5.029; 15 4.445,5.029; 16 3.175,5.029; 17 1.905,5.029; 18 0.635,5.029; 19 -0.635,5.029; 20 -1.905,5.029; 21 -3.175,5.029; 22 -4.445,5.029; 23 -5.715,5.029; 24 -6.985,5.029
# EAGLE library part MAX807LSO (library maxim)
WATCHDOG

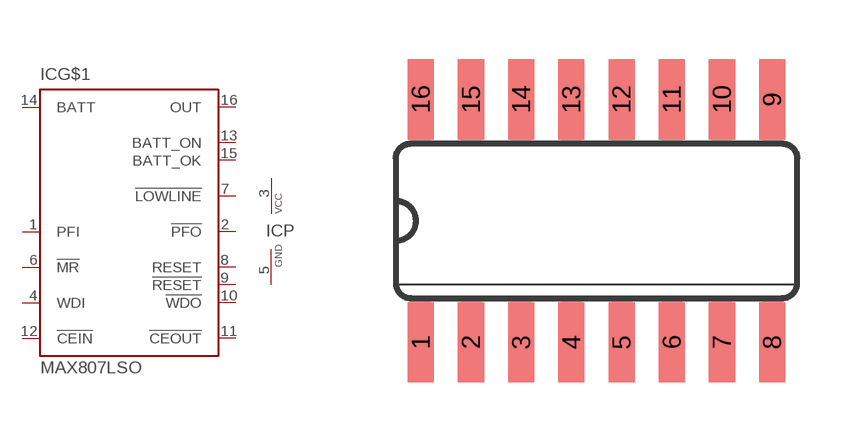
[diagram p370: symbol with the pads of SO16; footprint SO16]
Designator prefix IC; gates G$1=MAX807 P=VCC-GND

## MAX807LSO (OC_FARNELL: unknown; OC_NEWARK: unknown)  [SO16]
1  G$1:PFI  in
2  G$1:!PFO  out
3  P:VCC  pwr
4  G$1:WDI  in
5  P:GND  pwr
6  G$1:!MR  in
7  G$1:!LOWLINE  out
8  G$1:RESET  out
9  G$1:!RESET  out
10  G$1:!WDO  out
11  G$1:!CEOUT  out
12  G$1:!CEIN  in
13  G$1:BATT_ON  out
14  G$1:BATT  in
15  G$1:BATT_OK  out
16  G$1:OUT  out

## Footprint SO16 (pad centres in mm)
Small Outline Package .150 SIOC Source: http://www.maxim-ic.com/package_drawings/21-0041B.pdf
smd 0.66 x 2.032: 1 -4.445,-3.073; 2 -3.175,-3.073; 3 -1.905,-3.073; 4 -0.635,-3.073; 5 0.635,-3.073; 6 1.905,-3.073; 7 3.175,-3.073; 8 4.445,-3.073; 9 4.445,3.073; 10 3.175,3.073; 11 1.905,3.073; 12 0.635,3.073; 13 -0.635,3.073; 14 -1.905,3.073; 15 -3.175,3.073; 16 -4.445,3.073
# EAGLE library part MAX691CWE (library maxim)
WATCHDOG

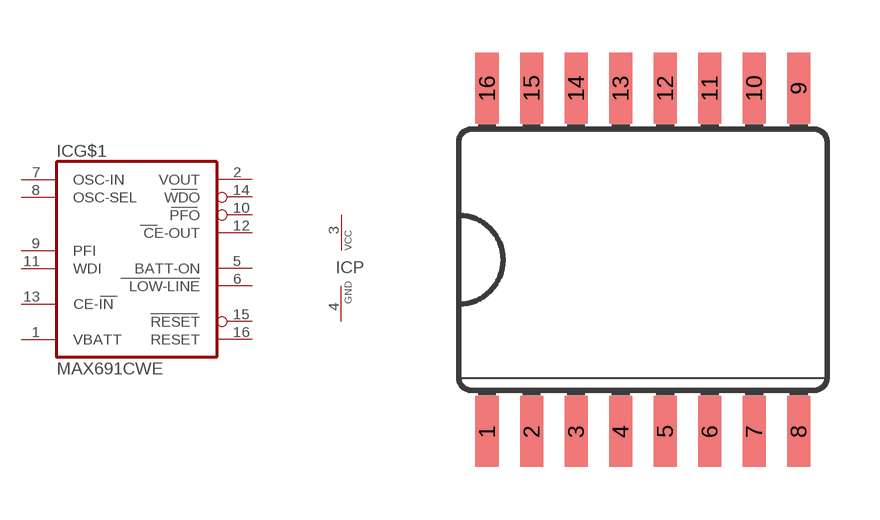
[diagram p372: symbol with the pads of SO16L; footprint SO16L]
Designator prefix IC; gates G$1=MAX691 P=VCC-GND

## MAX691CWE (MF: MAXIM; MPN: MAX691CWE; OC_FARNELL: 9724184; OC_NEWARK: 34C3984)  [SO16L]
1  G$1:VBATT  in
2  G$1:VOUT  out
3  P:VCC  pwr
4  P:GND  pwr
5  G$1:BATT-ON  out
6  G$1:LOW-LINE  out
7  G$1:OSC-IN  pas
8  G$1:OSC-SEL  pas
9  G$1:PFI  in
10  G$1:PFO  out
11  G$1:WDI  in
12  G$1:CE-OUT  out
13  G$1:CE-IN  in
14  G$1:WDO  out
15  G$1:RESET  out
16  G$1:RESET  out

## Footprint SO16L (pad centres in mm)
Small Outline Package .300 SIOC Source: http://www.maxim-ic.com/cgi-bin/packages?pkg=16%2FSOIC%2E300&Type=Max
smd 0.66 x 2.032: 1 -4.445,-4.902; 2 -3.175,-4.902; 3 -1.905,-4.902; 4 -0.635,-4.902; 5 0.635,-4.902; 6 1.905,-4.902; 7 3.175,-4.902; 8 4.445,-4.902; 9 4.445,4.902; 10 3.175,4.902; 11 1.905,4.902; 12 0.635,4.902; 13 -0.635,4.902; 14 -1.905,4.902; 15 -3.175,4.902; 16 -4.445,4.902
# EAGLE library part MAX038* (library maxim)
HIGH FREQUENCY WAVEFORM GENERATOR

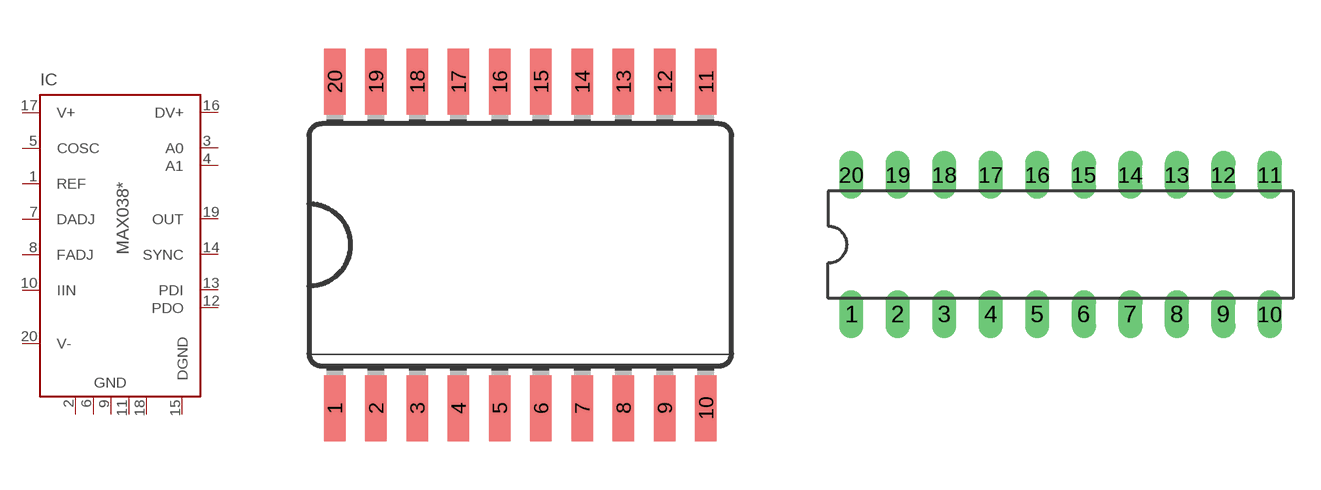
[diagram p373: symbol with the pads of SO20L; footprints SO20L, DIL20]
Designator prefix IC

## MAX038CWP (OC_FARNELL: unknown; OC_NEWARK: unknown), MAX038EWP (OC_FARNELL: unknown; OC_NEWARK: unknown)  [SO20L]
1  REF  out
2  GND  pwr
3  A0  in
4  A1  in
5  COSC  pas
6  GND  pwr
7  DADJ  in
8  FADJ  in
9  GND  pwr
10  IIN  pas
11  GND  pwr
12  PDO  out
13  PDI  in
14  SYNC  out
15  DGND  pwr
16  DV+  pwr
17  V+  pwr
18  GND  pwr
19  OUT  out
20  V-  pwr

## MAX038CPP (OC_FARNELL: unknown; OC_NEWARK: unknown), MAX038EPP (OC_FARNELL: unknown; OC_NEWARK: unknown)  [DIL20]
Pads as for SO20L

## Footprint SO20L (pad centres in mm)
Small Outline Package
smd 0.66 x 2.032: 1 -5.715,-5.029; 2 -4.445,-5.029; 3 -3.175,-5.029; 4 -1.905,-5.029; 5 -0.635,-5.029; 6 0.635,-5.029; 7 1.905,-5.029; 8 3.175,-5.029; 9 4.445,-5.029; 10 5.715,-5.029; 11 5.715,5.029; 12 4.445,5.029; 13 3.175,5.029; 14 1.905,5.029; 15 0.635,5.029; 16 -0.635,5.029; 17 -1.905,5.029; 18 -3.175,5.029; 19 -4.445,5.029; 20 -5.715,5.029

## Footprint DIL20 (pad centres in mm)
Dual In Line Package
drill 0.813 long: 1 -11.43,-3.81; 2 -8.89,-3.81; 3 -6.35,-3.81; 4 -3.81,-3.81; 5 -1.27,-3.81; 6 1.27,-3.81; 7 3.81,-3.81; 8 6.35,-3.81; 9 8.89,-3.81; 10 11.43,-3.81; 11 11.43,3.81; 12 8.89,3.81; 13 6.35,3.81; 14 3.81,3.81; 15 1.27,3.81; 16 -1.27,3.81; 17 -3.81,3.81; 18 -6.35,3.81; 19 -8.89,3.81; 20 -11.43,3.81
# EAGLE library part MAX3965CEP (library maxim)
OP AMP

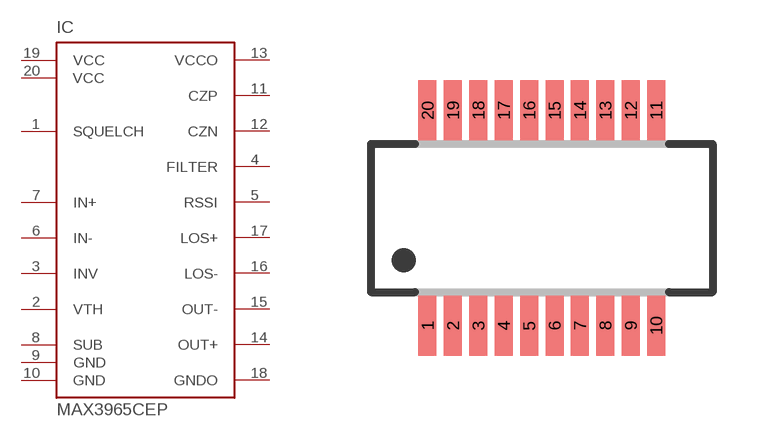
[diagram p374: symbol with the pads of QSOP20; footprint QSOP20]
Designator prefix IC

## MAX3965CEP (OC_FARNELL: unknown; OC_NEWARK: unknown)  [QSOP20]
1  SQUELCH  in
2  VTH  out
3  INV  in
4  FILTER  out
5  RSSI  out
6  IN-  in
7  IN+  in
8  SUB  pas
9  GND  pwr
10  GND  pwr
11  CZP  pas
12  CZN  pas
13  VCCO  pwr
14  OUT+  out
15  OUT-  out
16  LOS-  out
17  LOS+  out
18  GNDO  pwr
19  VCC  pwr
20  VCC  pwr

## Footprint QSOP20 (pad centres in mm)
Small Outline Package
smd 0.45 x 1.5: 1 -2.857,-2.69; 2 -2.223,-2.69; 3 -1.587,-2.69; 4 -0.953,-2.69; 5 -0.318,-2.69; 6 0.318,-2.69; 7 0.953,-2.69; 8 1.587,-2.69; 9 2.223,-2.69; 10 2.857,-2.69; 11 2.857,2.69; 12 2.223,2.69; 13 1.587,2.69; 14 0.953,2.69; 15 0.318,2.69; 16 -0.318,2.69; 17 -0.953,2.69; 18 -1.587,2.69; 19 -2.223,2.69; 20 -2.857,2.69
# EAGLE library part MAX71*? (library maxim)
NiCd/NiMH Battery Fast-Charge Controller

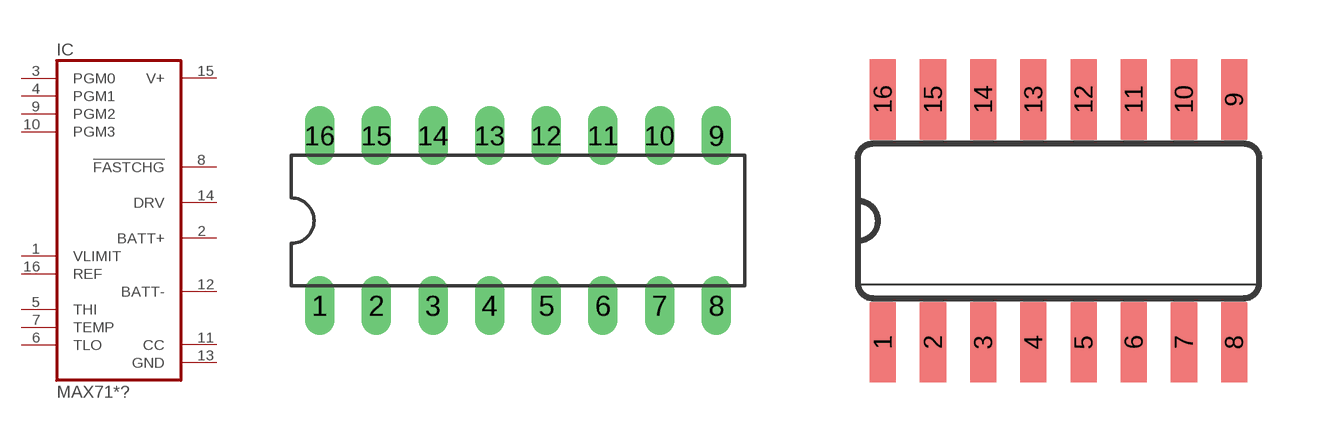
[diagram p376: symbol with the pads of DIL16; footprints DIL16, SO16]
Designator prefix IC

## MAX712CPE (MPN: MAX712CPE+; OC_FARNELL: 1187977; OC_NEWARK: 89K6069), MAX712EPE (MPN: MAX712EPE+; OC_FARNELL: unknown; OC_NEWARK: 89K6070), MAX713CPE (MF: MAXIM; MPN: MAX713CPE+; OC_FARNELL: 1187938; OC_NEWARK: 89K6074), MAX713EPE (MPN: MAX713EPE+; OC_FARNELL: unknown; OC_NEWARK: 89K6075)  [DIL16]
1  VLIMIT  in
2  BATT+  in
3  PGM0  in
4  PGM1  in
5  THI  in
6  TLO  in
7  TEMP  in
8  !FASTCHG  oc
9  PGM2  in
10  PGM3  in
11  CC  in
12  BATT-  in
13  GND  pwr
14  DRV  out
15  V+  pwr
16  REF  in

## MAX712CSE (MF: MAXIM; MPN: MAX712CSE+; OC_FARNELL: unknown; OC_NEWARK: 49H9633), MAX712ESE (MF: MAXIM; MPN: MAX712ESE+; OC_FARNELL: unknown; OC_NEWARK: 43K3866), MAX713CSE (MF: MAXIM; MPN: MAX713CSE+; OC_FARNELL: 9726403; OC_NEWARK: 28K3561), MAX713ESE (MF: MAXIM; MPN: MAX713ESE+; OC_FARNELL: unknown; OC_NEWARK: 53K7264)  [SO16]
Pads as for DIL16

## Footprint DIL16 (pad centres in mm)
Dual In Line Package
drill 0.813 long: 1 -8.89,-3.81; 2 -6.35,-3.81; 3 -3.81,-3.81; 4 -1.27,-3.81; 5 1.27,-3.81; 6 3.81,-3.81; 7 6.35,-3.81; 8 8.89,-3.81; 9 8.89,3.81; 10 6.35,3.81; 11 3.81,3.81; 12 1.27,3.81; 13 -1.27,3.81; 14 -3.81,3.81; 15 -6.35,3.81; 16 -8.89,3.81

## Footprint SO16 (pad centres in mm)
Small Outline Package .150 SIOC Source: http://www.maxim-ic.com/package_drawings/21-0041B.pdf
smd 0.66 x 2.032: 1 -4.445,-3.073; 2 -3.175,-3.073; 3 -1.905,-3.073; 4 -0.635,-3.073; 5 0.635,-3.073; 6 1.905,-3.073; 7 3.175,-3.073; 8 4.445,-3.073; 9 4.445,3.073; 10 3.175,3.073; 11 1.905,3.073; 12 0.635,3.073; 13 -0.635,3.073; 14 -1.905,3.073; 15 -3.175,3.073; 16 -4.445,3.073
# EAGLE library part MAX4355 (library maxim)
16x16 Nonblocking Video Crosspoint Switch with I/O Buffers

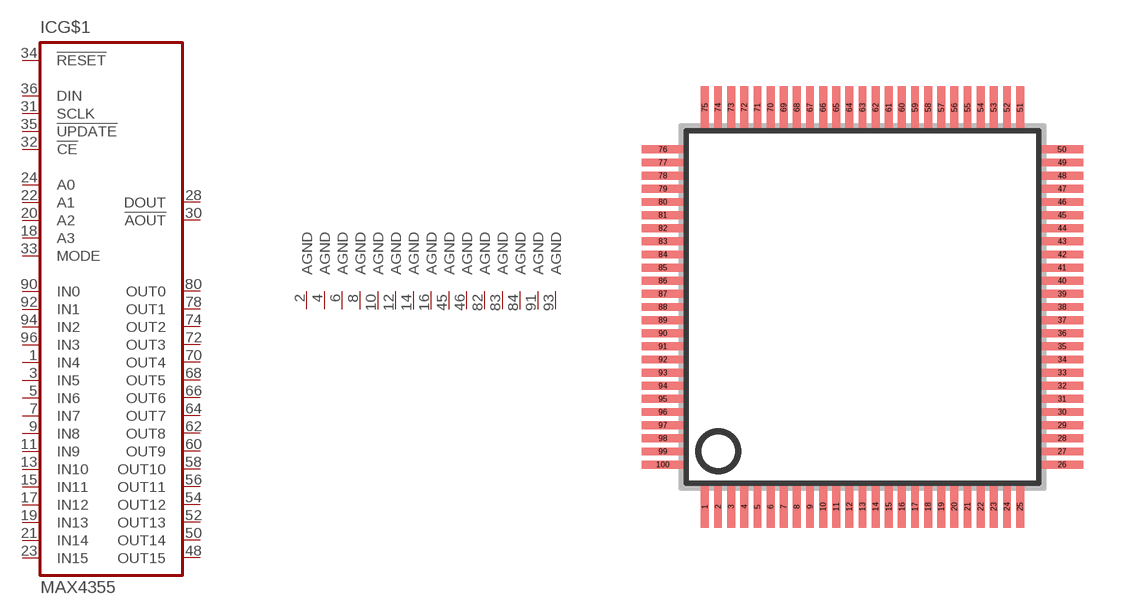
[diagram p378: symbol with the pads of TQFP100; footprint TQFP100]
Designator prefix IC; gates G$1=MAX4355 G1=AGND G2=AGND G3=AGND G4=AGND G5=AGND G6=AGND G7=AGND G8=AGND G9=AGND G10=AGND G11=AGND G12=AGND G13=AGND G14=AGND G15=AGND G16=AGND G17=AGND G18=DGND G19=VCC G20=VCC G21=VCC G22=VCC G23=VCC G24=VCC G25=VCC G26=VCC G27=VCC G28=VCC V1=VEE V2=VEE V3=VEE V4=VEE V5=VEE V6=VEE V7=VEE V8=VEE N1=NC N2=NC N3=NC N4=NC N5=NC N6=NC N7=NC N8=NC N9=NC N10=NC N11=NC N12=NC N13=NC N14=NC N15=NC N16=NC N17=NC N18=NC V9=VEE N19=VDD

## MAX4355ECQ (OC_FARNELL: unknown; OC_NEWARK: unknown)  [TQFP100]
1  G$1:IN4  in
2  G1:AGND  pwr
3  G$1:IN5  in
4  G2:AGND  pwr
5  G$1:IN6  in
6  G3:AGND  pwr
7  G$1:IN7  in
8  G4:AGND  pwr
9  G$1:IN8  in
10  G5:AGND  pwr
11  G$1:IN9  in
12  G6:AGND  pwr
13  G$1:IN10  in
14  G7:AGND  pwr
15  G$1:IN11  in
16  G8:AGND  pwr
17  G$1:IN12  in
18  G$1:A3  in
19  G$1:IN13  in
20  G$1:A2  in
21  G$1:IN14  in
22  G$1:A1  in
23  G$1:IN15  in
24  G$1:A0  in
25  G19:VCC  pwr
26  N1:NC  nc
27  N2:NC  nc
28  G$1:DOUT  out
29  G18:DGND  pwr
30  G$1:!AOUT  out
31  G$1:SCLK  in
32  G$1:!CE  in
33  G$1:MODE  in
34  G$1:!RESET  in
35  G$1:!UPDATE  in
36  G$1:DIN  in
37  N19:VDD  pwr
38  N3:NC  nc
39  N4:NC  nc
40  N5:NC  nc
41  N6:NC  nc
42  N7:NC  nc
43  N8:NC  nc
44  N9:NC  nc
45  G9:AGND  pwr
46  G10:AGND  pwr
47  G20:VCC  pwr
48  G$1:OUT15  out
49  V1:VEE  pwr
50  G$1:OUT14  out
51  G21:VCC  pwr
52  G$1:OUT13  out
53  V2:VEE  pwr
54  G$1:OUT12  out
55  G22:VCC  pwr
56  G$1:OUT11  out
57  V3:VEE  pwr
58  G$1:OUT10  out
59  G23:VCC  pwr
60  G$1:OUT9  out
61  V4:VEE  pwr
62  G$1:OUT8  out
63  G24:VCC  pwr
64  G$1:OUT7  out
65  V5:VEE  pwr
66  G$1:OUT6  out
67  G25:VCC  pwr
68  G$1:OUT5  out
69  V6:VEE  pwr
70  G$1:OUT4  out
71  G26:VCC  pwr
72  G$1:OUT3  out
73  V7:VEE  pwr
74  G$1:OUT2  out
75  G27:VCC  pwr
76  N10:NC  nc
77  N11:NC  nc
78  G$1:OUT1  out
79  V8:VEE  pwr
80  G$1:OUT0  out
81  G28:VCC  pwr
82  G11:AGND  pwr
83  G12:AGND  pwr
84  G13:AGND  pwr
85  N12:NC  nc
86  N13:NC  nc
87  N14:NC  nc
88  N15:NC  nc
89  N16:NC  nc
90  G$1:IN0  in
91  G14:AGND  pwr
92  G$1:IN1  in
93  G15:AGND  pwr
94  G$1:IN2  in
95  G16:AGND  pwr
96  G$1:IN3  in
97  G17:AGND  pwr
98  V9:VEE  pwr
99  N17:NC  nc
100  N18:NC  nc

## Footprint TQFP100 (pad centres in mm)
TQFP100 thin quad flat pack, square 14 x14 mm
smd 0.3 x 1.6: 1 -6,-7.6; 2 -5.5,-7.6; 3 -5,-7.6; 4 -4.5,-7.6; 5 -4,-7.6; 6 -3.5,-7.6; 7 -3,-7.6; 8 -2.5,-7.6; 9 -2,-7.6; 10 -1.5,-7.6; 11 -1,-7.6; 12 -0.5,-7.6; 13 0,-7.6; 14 0.5,-7.6; 15 1,-7.6; 16 1.5,-7.6; 17 2,-7.6; 18 2.5,-7.6; 19 3,-7.6; 20 3.5,-7.6; 21 4,-7.6; 22 4.5,-7.6; 23 5,-7.6; 24 5.5,-7.6; 25 6,-7.6; 51 6,7.6; 52 5.5,7.6; 53 5,7.6; 54 4.5,7.6; 55 4,7.6; 56 3.5,7.6; 57 3,7.6; 58 2.5,7.6; 59 2,7.6; 60 1.5,7.6; 61 1,7.6; 62 0.5,7.6; 63 0,7.6; 64 -0.5,7.6; 65 -1,7.6; 66 -1.5,7.6; 67 -2,7.6; 68 -2.5,7.6; 69 -3,7.6; 70 -3.5,7.6; 71 -4,7.6; 72 -4.5,7.6; 73 -5,7.6; 74 -5.5,7.6; 75 -6,7.6
smd 1.6 x 0.3: 26 7.6,-6; 27 7.6,-5.5; 28 7.6,-5; 29 7.6,-4.5; 30 7.6,-4; 31 7.6,-3.5; 32 7.6,-3; 33 7.6,-2.5; 34 7.6,-2; 35 7.6,-1.5; 36 7.6,-1; 37 7.6,-0.5; 38 7.6,0; 39 7.6,0.5; 40 7.6,1; 41 7.6,1.5; 42 7.6,2; 43 7.6,2.5; 44 7.6,3; 45 7.6,3.5; 46 7.6,4; 47 7.6,4.5; 48 7.6,5; 49 7.6,5.5; 50 7.6,6; 76 -7.6,6; 77 -7.6,5.5; 78 -7.6,5; 79 -7.6,4.5; 80 -7.6,4; 81 -7.6,3.5; 82 -7.6,3; 83 -7.6,2.5; 84 -7.6,2; 85 -7.6,1.5; 86 -7.6,1; 87 -7.6,0.5; 88 -7.6,0; 89 -7.6,-0.5; 90 -7.6,-1; 91 -7.6,-1.5; 92 -7.6,-2; 93 -7.6,-2.5; 94 -7.6,-3; 95 -7.6,-3.5; 96 -7.6,-4; 97 -7.6,-4.5; 98 -7.6,-5; 99 -7.6,-5.5; 100 -7.6,-6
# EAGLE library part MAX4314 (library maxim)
Video Multiplexer-Amplifier High-Speed, Low-Power, Single-Supply, Multichannel

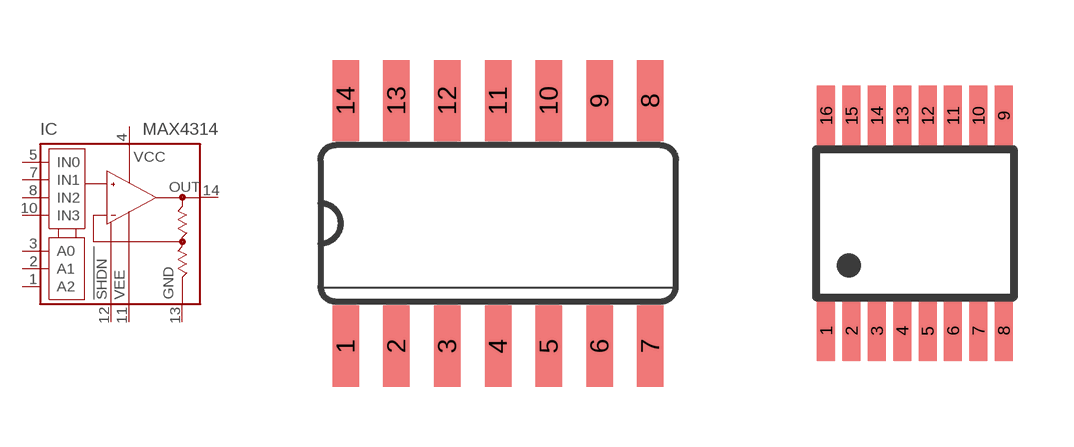
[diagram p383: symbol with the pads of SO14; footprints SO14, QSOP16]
Designator prefix IC

## MAX4314ESD (MF: MAXIM; MPN: MAX4314ESD+; OC_FARNELL: unknown; OC_NEWARK: 61K0443)  [SO14]
1  A2  in
2  A1  in
3  A0  in
4  V+  pwr
5  IN0  in
7  IN1  in
8  IN2  in
10  IN3  in
11  V-  pwr
12  !SHDN  pas
13  GND  pwr
14  OUT  out

## MAX4314EEE (MPN: MAX4314EEE+; OC_FARNELL: unknown; OC_NEWARK: 57K8865)  [QSOP16]
1  A2  in
2  A1  in
3  A0  in
4  V+  pwr
5  IN0  in
7  IN1  in
10  IN2  in
12  IN3  in
13  V-  pwr
14  !SHDN  pas
15  GND  pwr
16  OUT  out

## Footprint SO14 (pad centres in mm)
Small Outline Package
smd 0.66 x 2.032: 1 -3.81,-3.073; 2 -2.54,-3.073; 3 -1.27,-3.073; 4 0,-3.073; 5 1.27,-3.073; 6 2.54,-3.073; 7 3.81,-3.073; 8 3.81,3.073; 9 2.54,3.073; 10 1.27,3.073; 11 0,3.073; 12 -1.27,3.073; 13 -2.54,3.073; 14 -3.81,3.073

## Footprint QSOP16 (pad centres in mm)
Small Outline Package
smd 0.45 x 1.5: 1 -2.223,-2.69; 2 -1.587,-2.69; 3 -0.953,-2.69; 4 -0.318,-2.69; 5 0.318,-2.69; 6 0.953,-2.69; 7 1.587,-2.69; 8 2.223,-2.69; 9 2.223,2.69; 10 1.587,2.69; 11 0.953,2.69; 12 0.318,2.69; 13 -0.318,2.69; 14 -0.953,2.69; 15 -1.587,2.69; 16 -2.223,2.69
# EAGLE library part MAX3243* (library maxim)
RS-232 Transceivers with AutoShutdown 1µA Supply-Current, True +3V to +5.5V http://dbserv.maxim-ic.com/

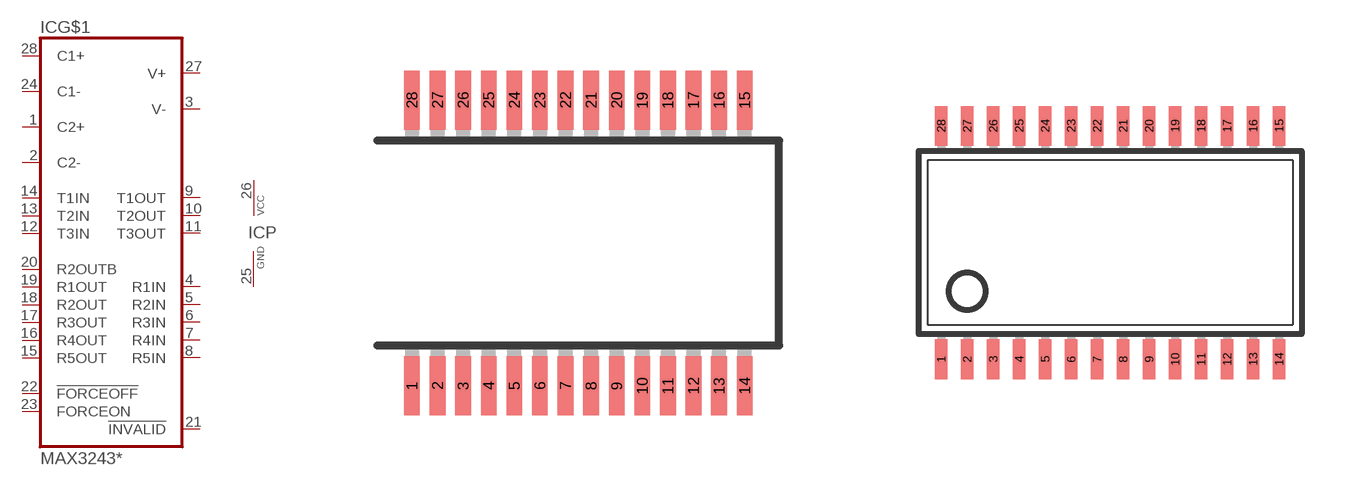
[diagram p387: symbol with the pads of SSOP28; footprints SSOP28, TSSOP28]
Designator prefix IC; gates G$1=MAX3243 P=VCC-GND

## MAX3243CAI (MF: MAXIM; MPN: MAX3243CAI+; OC_FARNELL: 1379933; OC_NEWARK: 59K9409), MAX3243EAI (MF: MAXIM; MPN: MAX3243EAI+; OC_FARNELL: unknown; OC_NEWARK: 67K4901)  [SSOP28]
1  G$1:C2+  pas
2  G$1:C2-  pas
3  G$1:V-  pas
4  G$1:R1IN  in
5  G$1:R2IN  in
6  G$1:R3IN  in
7  G$1:R4IN  in
8  G$1:R5IN  in
9  G$1:T1OUT  out
10  G$1:T2OUT  out
11  G$1:T3OUT  out
12  G$1:T3IN  in
13  G$1:T2IN  in
14  G$1:T1IN  in
15  G$1:R5OUT  out
16  G$1:R4OUT  out
17  G$1:R3OUT  out
18  G$1:R2OUT  out
19  G$1:R1OUT  out
20  G$1:R2OUTB  out
21  G$1:!INVALID  in
22  G$1:!FORCEOFF  in
23  G$1:FORCEON  in
24  G$1:C1-  pas
25  P:GND  pwr
26  P:VCC  pwr
27  G$1:V+  pas
28  G$1:C1+  pas

## MAX3243UI (OC_FARNELL: unknown; OC_NEWARK: unknown)  [TSSOP28]
Pads as for SSOP28

## MAX3243WI (OC_FARNELL: unknown; OC_NEWARK: unknown)  [SO28L]
Pads as for SSOP28

## Footprint SSOP28 (pad centres in mm)
Shrink Small Outline Package package type SS
smd 0.4 x 1.5: 1 -4.225,-3.625; 2 -3.575,-3.625; 3 -2.925,-3.625; 4 -2.275,-3.625; 5 -1.625,-3.625; 6 -0.975,-3.625; 7 -0.325,-3.625; 8 0.325,-3.625; 9 0.975,-3.625; 10 1.625,-3.625; 11 2.275,-3.625; 12 2.925,-3.625; 13 3.575,-3.625; 14 4.225,-3.625; 15 4.225,3.625; 16 3.575,3.625; 17 2.925,3.625; 18 2.275,3.625; 19 1.625,3.625; 20 0.975,3.625; 21 0.325,3.625; 22 -0.325,3.625; 23 -0.975,3.625; 24 -1.625,3.625; 25 -2.275,3.625; 26 -2.925,3.625; 27 -3.575,3.625; 28 -4.225,3.625

## Footprint TSSOP28 (pad centres in mm)
Thin Shrink Small Outline Plastic 28 MAX3223-MAX3243.pdf
smd 0.305 x 0.991: 1 -4.225,-2.918; 2 -3.575,-2.918; 3 -2.925,-2.918; 4 -2.275,-2.918; 5 -1.625,-2.918; 6 -0.975,-2.918; 7 -0.325,-2.918; 8 0.325,-2.918; 9 0.975,-2.918; 10 1.625,-2.918; 11 2.275,-2.918; 12 2.925,-2.918; 13 3.575,-2.918; 14 4.225,-2.918; 15 4.225,2.918; 16 3.575,2.918; 17 2.925,2.918; 18 2.275,2.918; 19 1.625,2.918; 20 0.975,2.918; 21 0.325,2.918; 22 -0.325,2.918; 23 -0.975,2.918; 24 -1.625,2.918; 25 -2.275,2.918; 26 -2.925,2.918; 27 -3.575,2.918; 28 -4.225,2.918

## Footprint SO28L (pad centres in mm)
Small Outline Package MAX3221-MAX3243.pdf; SO28W
smd 0.66 x 2.032: 1 -8.255,-5.029; 2 -6.985,-5.029; 3 -5.715,-5.029; 4 -4.445,-5.029; 5 -3.175,-5.029; 6 -1.905,-5.029; 7 -0.635,-5.029; 8 0.635,-5.029; 9 1.905,-5.029; 10 3.175,-5.029; 11 4.445,-5.029; 12 5.715,-5.029; 13 6.985,-5.029; 14 8.255,-5.029; 15 8.255,5.029; 16 6.985,5.029; 17 5.715,5.029; 18 4.445,5.029; 19 3.175,5.029; 20 1.905,5.029; 21 0.635,5.029; 22 -0.635,5.029; 23 -1.905,5.029; 24 -3.175,5.029; 25 -4.445,5.029; 26 -5.715,5.029; 27 -6.985,5.029; 28 -8.255,5.029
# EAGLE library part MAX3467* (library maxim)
+5V, Fail-Safe, 40Mbps, Profibus RS-485/RS-422 Transceivers Source: MAX3465-MAX3469.pdf

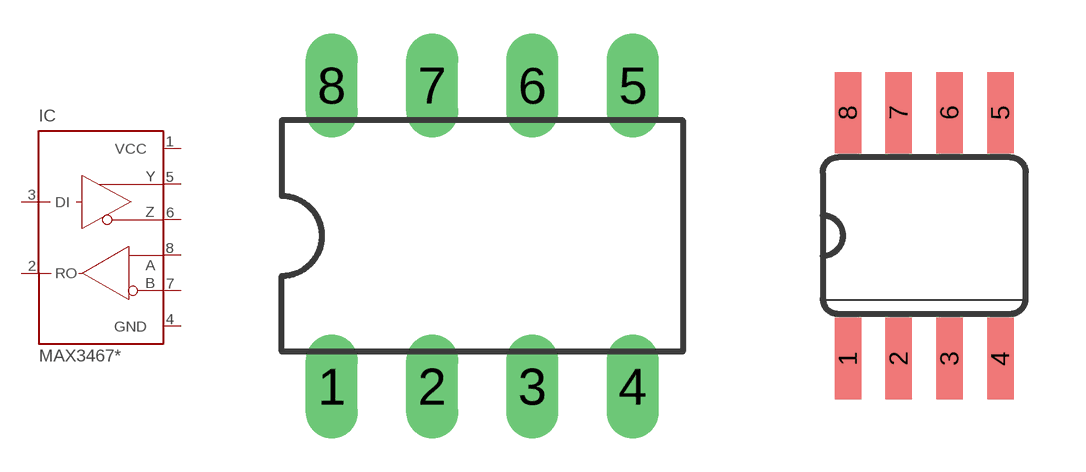
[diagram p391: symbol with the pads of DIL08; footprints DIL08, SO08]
Designator prefix IC

## MAX3467CSA (OC_FARNELL: unknown; OC_NEWARK: unknown), MAX3467ESA (OC_FARNELL: unknown; OC_NEWARK: unknown)  [DIL08]
1  VCC  pwr
2  RO  out
3  DI  in
4  GND  pwr
5  Y  pas
6  Z  pas
7  B  pas
8  A  pas

## MAX3467CPA (OC_FARNELL: unknown; OC_NEWARK: unknown), MAX3467EPA (OC_FARNELL: unknown; OC_NEWARK: unknown)  [SO08]
Pads as for DIL08

## Footprint DIL08 (pad centres in mm)
Dual In Line Package
drill 0.813 long: 1 -3.81,-3.81; 2 -1.27,-3.81; 3 1.27,-3.81; 4 3.81,-3.81; 5 3.81,3.81; 6 1.27,3.81; 7 -1.27,3.81; 8 -3.81,3.81

## Footprint SO08 (pad centres in mm)
Small Outline Package SOIC 150 mil
smd 0.66 x 2.032: 1 -1.905,-3.073; 2 -0.635,-3.073; 3 0.635,-3.073; 4 1.905,-3.073; 5 1.905,3.073; 6 0.635,3.073; 7 -0.635,3.073; 8 -1.905,3.073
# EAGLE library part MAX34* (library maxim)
+5V, Fail-Safe, 40Mbps, Profibus RS-485/RS-422 Transceivers Source: MAX3465-MAX3469.pdf

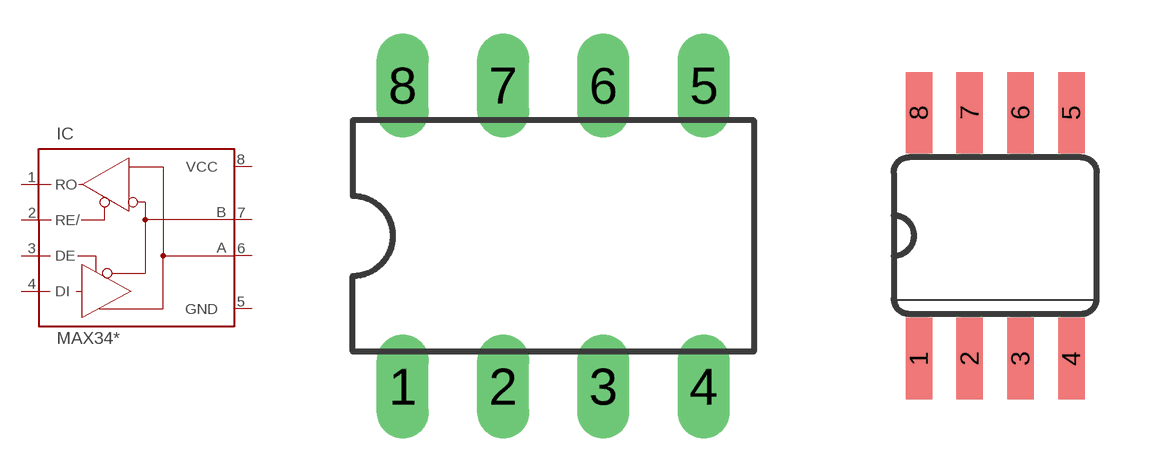
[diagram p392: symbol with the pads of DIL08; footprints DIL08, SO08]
Designator prefix IC

## MAX3468CPA (OC_FARNELL: unknown; OC_NEWARK: unknown), MAX3468EPA (MPN: MAX3468EPA+; OC_FARNELL: unknown; OC_NEWARK: 78M5804), MAX3469CPA (OC_FARNELL: unknown; OC_NEWARK: unknown), MAX3469EPA (OC_FARNELL: unknown; OC_NEWARK: unknown)  [DIL08]
1  RO  out
2  RE/  in
3  DE  in
4  DI  in
5  GND  pwr
6  A  pas
7  B  pas
8  VCC  pwr

## MAX3468CSA (MPN: MAX3468CSA+; OC_FARNELL: unknown; OC_NEWARK: 76K6721), MAX3468ESA (MPN: MAX3468ESA+T; OC_FARNELL: unknown; OC_NEWARK: 76K6724), MAX3469CSA (MPN: MAX3469CSA+; OC_FARNELL: unknown; OC_NEWARK: 05M8548), MAX3469ESA (MPN: MAX3469ESA+; OC_FARNELL: unknown; OC_NEWARK: 67K5012)  [SO08]
Pads as for DIL08

## Footprint DIL08 (pad centres in mm)
Dual In Line Package
drill 0.813 long: 1 -3.81,-3.81; 2 -1.27,-3.81; 3 1.27,-3.81; 4 3.81,-3.81; 5 3.81,3.81; 6 1.27,3.81; 7 -1.27,3.81; 8 -3.81,3.81

## Footprint SO08 (pad centres in mm)
Small Outline Package SOIC 150 mil
smd 0.66 x 2.032: 1 -1.905,-3.073; 2 -0.635,-3.073; 3 0.635,-3.073; 4 1.905,-3.073; 5 1.905,3.073; 6 0.635,3.073; 7 -0.635,3.073; 8 -1.905,3.073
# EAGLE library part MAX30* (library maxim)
±10kV ESD-Protected, Quad 5V RS-485/RS-422 Transmitters Source: www.maxim-ic.com .. MAX3040-MAX3045.pdf

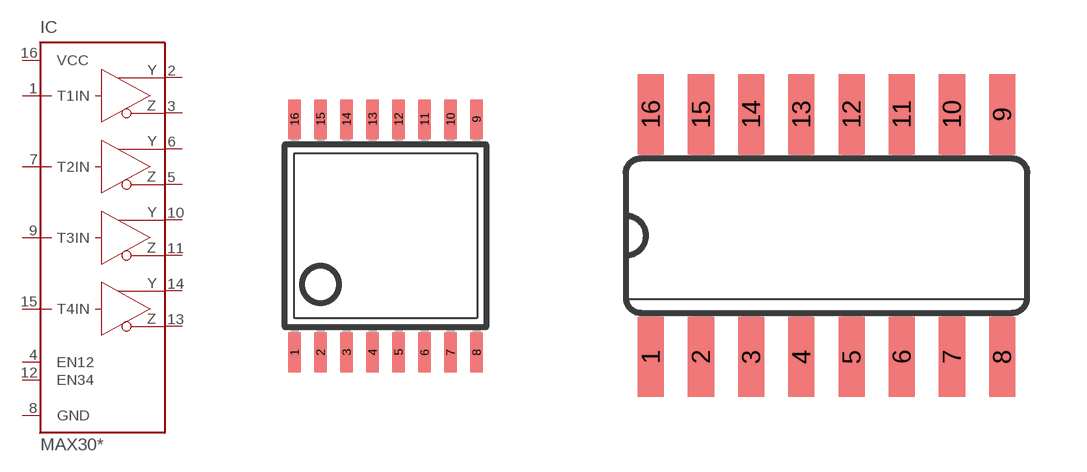
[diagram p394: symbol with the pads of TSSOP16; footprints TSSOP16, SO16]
Designator prefix IC

## MAX3040CUE (MPN: MAX3040CUE+; OC_FARNELL: unknown; OC_NEWARK: 61K0320), MAX3040EUE (MPN: MAX3040EUE+; OC_FARNELL: unknown; OC_NEWARK: 61K0322), MAX3041CUE (MPN: MAX3041CUE+; OC_FARNELL: unknown; OC_NEWARK: 73K8525), MAX3041EUE (MPN: MAX3041EUE+; OC_FARNELL: unknown; OC_NEWARK: 73K8527), MAX3042BCUE (MF: MAXIM; MPN: MAX3042BCUE; OC_FARNELL: unknown; OC_NEWARK: 77C8906), MAX3042BEUE (MPN: MAX3042BEUE+; OC_FARNELL: unknown; OC_NEWARK: 57K8796)  [TSSOP16]
1  T1IN  in
2  Y1  out
3  Z1  out
4  EN12  in
5  Z2  out
6  Y2  out
7  T2IN  in
8  GND  pwr
9  T3IN  in
10  Y3  out
11  Z3  out
12  EN34  in
13  Z4  out
14  Y4  out
15  T4IN  in
16  VCC  pwr

## MAX3040CSE (MF: MAXIM; MPN: MAX3040CSE+; OC_FARNELL: unknown; OC_NEWARK: 53K6603), MAX3040ESE (MPN: MAX3040ESE+; OC_FARNELL: unknown; OC_NEWARK: 53K6605), MAX3041CSE (MPN: MAX3041CSE+; OC_FARNELL: unknown; OC_NEWARK: 61K0324), MAX3041ESE (MPN: MAX3041ESE+; OC_FARNELL: unknown; OC_NEWARK: 61K0326), MAX3042BCSE (MF: MAXIM; MPN: MAX3042BCSE; OC_FARNELL: unknown; OC_NEWARK: 77C8904), MAX3042BESE (MF: MAXIM; MPN: MAX3042BESE+; OC_FARNELL: unknown; OC_NEWARK: 33K2044)  [SO16]
Pads as for TSSOP16

## MAX3040CWE (MPN: MAX3040CWE+; OC_FARNELL: unknown; OC_NEWARK: 68K4574), MAX3040EWE (MPN: MAX3040EWE+; OC_FARNELL: unknown; OC_NEWARK: 68K4576), MAX3041CWE (OC_FARNELL: unknown; OC_NEWARK: unknown), MAX3041EWE (MPN: MAX3041EWE+; OC_FARNELL: unknown; OC_NEWARK: 13M2181), MAX3042BCWE (OC_FARNELL: unknown; OC_NEWARK: unknown), MAX3042BEWE (OC_FARNELL: unknown; OC_NEWARK: unknown)  [SO16L]
Pads as for TSSOP16

## Footprint TSSOP16 (pad centres in mm)
Thin Shrink Small Outline Plastic 16 http://www.maxim-ic.com .. MAX3223-MAX3243.pdf
smd 0.305 x 0.991: 1 -2.275,-2.918; 2 -1.625,-2.918; 3 -0.975,-2.918; 4 -0.325,-2.918; 5 0.325,-2.918; 6 0.975,-2.918; 7 1.625,-2.918; 8 2.275,-2.918; 9 2.275,2.918; 10 1.625,2.918; 11 0.975,2.918; 12 0.325,2.918; 13 -0.325,2.918; 14 -0.975,2.918; 15 -1.625,2.918; 16 -2.275,2.918

## Footprint SO16 (pad centres in mm)
Small Outline Package .150 SIOC Source: http://www.maxim-ic.com/package_drawings/21-0041B.pdf
smd 0.66 x 2.032: 1 -4.445,-3.073; 2 -3.175,-3.073; 3 -1.905,-3.073; 4 -0.635,-3.073; 5 0.635,-3.073; 6 1.905,-3.073; 7 3.175,-3.073; 8 4.445,-3.073; 9 4.445,3.073; 10 3.175,3.073; 11 1.905,3.073; 12 0.635,3.073; 13 -0.635,3.073; 14 -1.905,3.073; 15 -3.175,3.073; 16 -4.445,3.073

## Footprint SO16L (pad centres in mm)
Small Outline Package .300 SIOC Source: http://www.maxim-ic.com/cgi-bin/packages?pkg=16%2FSOIC%2E300&Type=Max
smd 0.66 x 2.032: 1 -4.445,-4.902; 2 -3.175,-4.902; 3 -1.905,-4.902; 4 -0.635,-4.902; 5 0.635,-4.902; 6 1.905,-4.902; 7 3.175,-4.902; 8 4.445,-4.902; 9 4.445,4.902; 10 3.175,4.902; 11 1.905,4.902; 12 0.635,4.902; 13 -0.635,4.902; 14 -1.905,4.902; 15 -3.175,4.902; 16 -4.445,4.902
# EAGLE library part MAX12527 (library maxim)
Dual, 65Msps, 12-Bit, IF/Baseband ADC Source: http://pdfserv.maxim-ic.com/en/ds/MAX12527.pdf

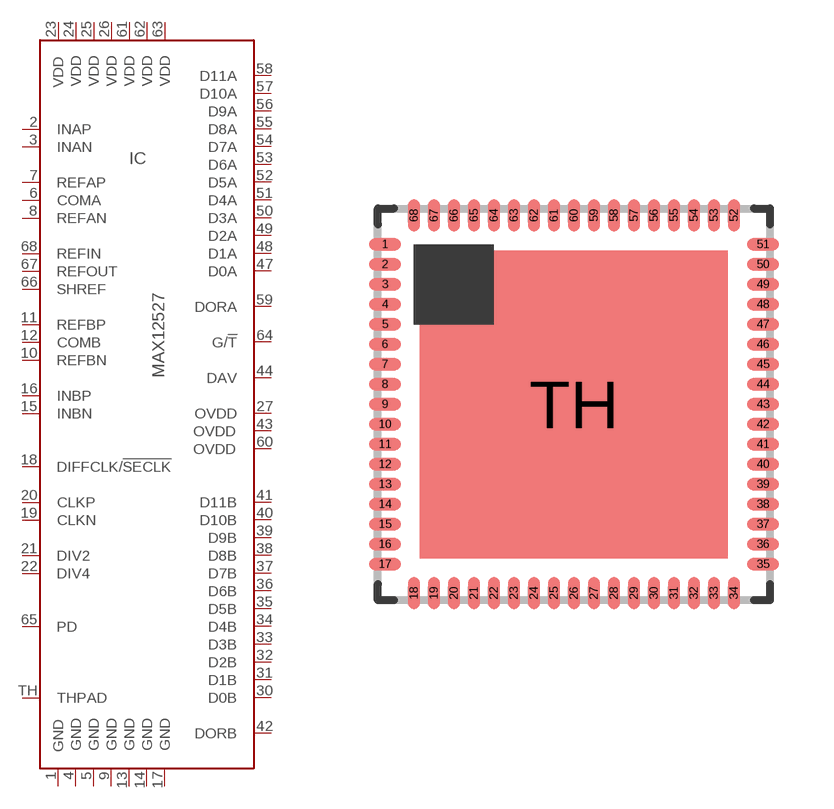
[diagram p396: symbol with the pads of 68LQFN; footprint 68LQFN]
Designator prefix IC

## MAX12527 (OC_FARNELL: unknown; OC_NEWARK: unknown)  [68LQFN]
1  GND  pwr
2  INAP  in
3  INAN  in
4  GND  pwr
5  GND  pwr
6  COMA  pas
7  REFAP  pas
8  REFAN  pas
9  GND  pwr
10  REFBN  pas
11  REFBP  pas
12  COMB  pas
13  GND  pwr
14  GND  pwr
15  INBN  in
16  INBP  in
17  GND  pwr
18  DIFFCLK/!SECLK  in
19  CLKN  in
20  CLKP  in
21  DIV2  in
22  DIV4  in
23  VDD  pwr
24  VDD  pwr
25  VDD  pwr
26  VDD  pwr
27  OVDD  pwr
30  D0B  out
31  D1B  out
32  D2B  out
33  D3B  out
34  D4B  out
35  D5B  out
36  D6B  out
37  D7B  out
38  D8B  out
39  D9B  out
40  D10B  out
41  D11B  out
42  DORB  out
43  OVDD  pwr
44  DAV  out
47  D0A  out
48  D1A  out
49  D2A  out
50  D3A  out
51  D4A  out
52  D5A  out
53  D6A  out
54  D7A  out
55  D8A  out
56  D9A  out
57  D10A  out
58  D11A  out
59  DORA  out
60  OVDD  pwr
61  VDD  pwr
62  VDD  pwr
63  VDD  pwr
64  G/!T  in
65  PD  in
66  SHREF  in
67  REFOUT  out
68  REFIN  in
TH  THPAD  pas

## Footprint 68LQFN (pad centres in mm)
68L QFN Source: http://pdfserv.maxim-ic.com/en/ds/MAX12527.pdf http://pdfserv.maxim-ic.com/package_dwgs/21-0142D.PDF
smd 0.8 x 0.3: 1 -4.725,4; 2 -4.725,3.5; 3 -4.725,3; 4 -4.725,2.5; 5 -4.725,2; 6 -4.725,1.5; 7 -4.725,1; 8 -4.725,0.5; 9 -4.725,0; 10 -4.725,-0.5; 11 -4.725,-1; 12 -4.725,-1.5; 13 -4.725,-2; 14 -4.725,-2.5; 15 -4.725,-3; 16 -4.725,-3.5; 17 -4.725,-4; 35 4.725,-4; 36 4.725,-3.5; 37 4.725,-3; 38 4.725,-2.5; 39 4.725,-2; 40 4.725,-1.5; 41 4.725,-1; 42 4.725,-0.5; 43 4.725,0; 44 4.725,0.5; 45 4.725,1; 46 4.725,1.5; 47 4.725,2; 48 4.725,2.5; 49 4.725,3; 50 4.725,3.5; 51 4.725,4
smd 0.3 x 0.8: 18 -4,-4.725; 19 -3.5,-4.725; 20 -3,-4.725; 21 -2.5,-4.725; 22 -2,-4.725; 23 -1.5,-4.725; 24 -1,-4.725; 25 -0.5,-4.725; 26 0,-4.725; 27 0.5,-4.725; 28 1,-4.725; 29 1.5,-4.725; 30 2,-4.725; 31 2.5,-4.725; 32 3,-4.725; 33 3.5,-4.725; 34 4,-4.725; 52 4,4.725; 53 3.5,4.725; 54 3,4.725; 55 2.5,4.725; 56 2,4.725; 57 1.5,4.725; 58 1,4.725; 59 0.5,4.725; 60 0,4.725; 61 -0.5,4.725; 62 -1,4.725; 63 -1.5,4.725; 64 -2,4.725; 65 -2.5,4.725; 66 -3,4.725; 67 -3.5,4.725; 68 -4,4.725
smd 7.7 x 7.7: TH 0,0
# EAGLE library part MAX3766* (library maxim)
622Mbps LAN/WAN Laser Driver with Automatic Power Control and Safety Shutdown Source: http://pdfserv.maxim-ic.com/en/ds/MAX3766.pdf

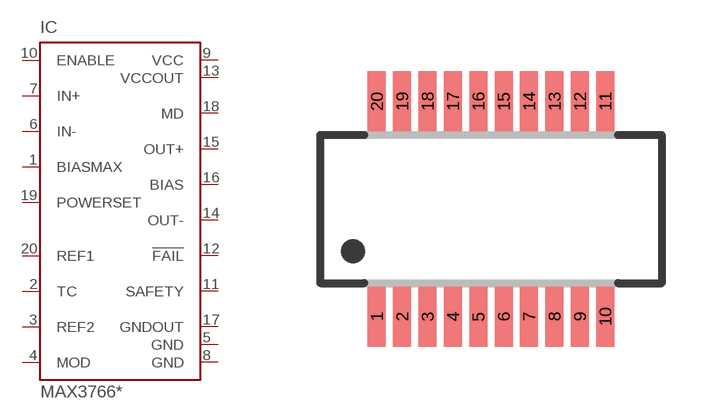
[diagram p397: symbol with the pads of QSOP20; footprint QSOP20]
Designator prefix IC

## MAX3766EEP (MF: MAXIM; MPN: MAX3766EEP+; OC_FARNELL: unknown; OC_NEWARK: 59J3051), MAX3766EEP+ (MF: MAXIM; MPN: MAX3766EEP+; OC_FARNELL: unknown; OC_NEWARK: 59J3051)  [QSOP20]
1  BIASMAX  in
2  TC  pas
3  REF2  pas
4  MOD  in
5  GND  pwr
6  IN-  in
7  IN+  in
8  GND  pwr
9  VCC  pwr
10  ENABLE  in
11  SAFETY  in
12  !FAIL  out
13  VCCOUT  pas
14  OUT-  out
15  OUT+  out
16  BIAS  pas
17  GNDOUT  pas
18  MD  in
19  POWERSET  in
20  REF1  pas

## Footprint QSOP20 (pad centres in mm)
Small Outline Package
smd 0.45 x 1.5: 1 -2.857,-2.69; 2 -2.223,-2.69; 3 -1.587,-2.69; 4 -0.953,-2.69; 5 -0.318,-2.69; 6 0.318,-2.69; 7 0.953,-2.69; 8 1.587,-2.69; 9 2.223,-2.69; 10 2.857,-2.69; 11 2.857,2.69; 12 2.223,2.69; 13 1.587,2.69; 14 0.953,2.69; 15 0.318,2.69; 16 -0.318,2.69; 17 -0.953,2.69; 18 -1.587,2.69; 19 -2.223,2.69; 20 -2.857,2.69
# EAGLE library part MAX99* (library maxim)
Micropower, Low-Voltage Rail-to-Rail I/O Comparators Source: http://pdfserv.maxim-ic.com/en/ds/MAX985-MAX994.pdf

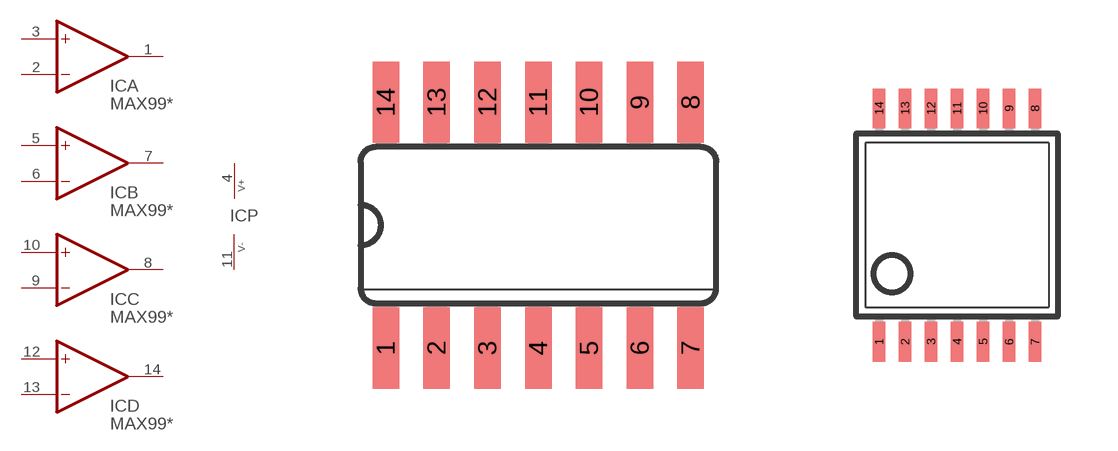
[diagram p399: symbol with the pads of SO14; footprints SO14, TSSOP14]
Designator prefix IC; gates A=OP B=OP C=OP D=OP P=PWR+-

## MAX99ESD (OC_FARNELL: unknown; OC_NEWARK: unknown)  [SO14]
1  A:OUT  out
2  A:-IN  in
3  A:+IN  in
4  P:V+  pwr
5  B:+IN  in
6  B:-IN  in
7  B:OUT  out
8  C:OUT  out
9  C:-IN  in
10  C:+IN  in
11  P:V-  pwr
12  D:+IN  in
13  D:-IN  in
14  D:OUT  out

## MAX99EUD (OC_FARNELL: unknown; OC_NEWARK: unknown)  [TSSOP14]
Pads as for SO14

## Footprint SO14 (pad centres in mm)
Small Outline Package
smd 0.66 x 2.032: 1 -3.81,-3.073; 2 -2.54,-3.073; 3 -1.27,-3.073; 4 0,-3.073; 5 1.27,-3.073; 6 2.54,-3.073; 7 3.81,-3.073; 8 3.81,3.073; 9 2.54,3.073; 10 1.27,3.073; 11 0,3.073; 12 -1.27,3.073; 13 -2.54,3.073; 14 -3.81,3.073

## Footprint TSSOP14 (pad centres in mm)
Thin Shrink Small Outline Plastic 14 MAX3223-MAX3243.pdf
smd 0.305 x 0.991: 1 -1.95,-2.918; 2 -1.3,-2.918; 3 -0.65,-2.918; 4 0,-2.918; 5 0.65,-2.918; 6 1.3,-2.918; 7 1.95,-2.918; 8 1.95,2.918; 9 1.3,2.918; 10 0.65,2.918; 11 0,2.918; 12 -0.65,2.918; 13 -1.3,2.918; 14 -1.95,2.918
